VERSION 5.8 ;
BUSBITCHARS "[]" ;
DIVIDERCHAR "/" ;
UNITS
    DATABASE MICRONS 1000 ;
END UNITS

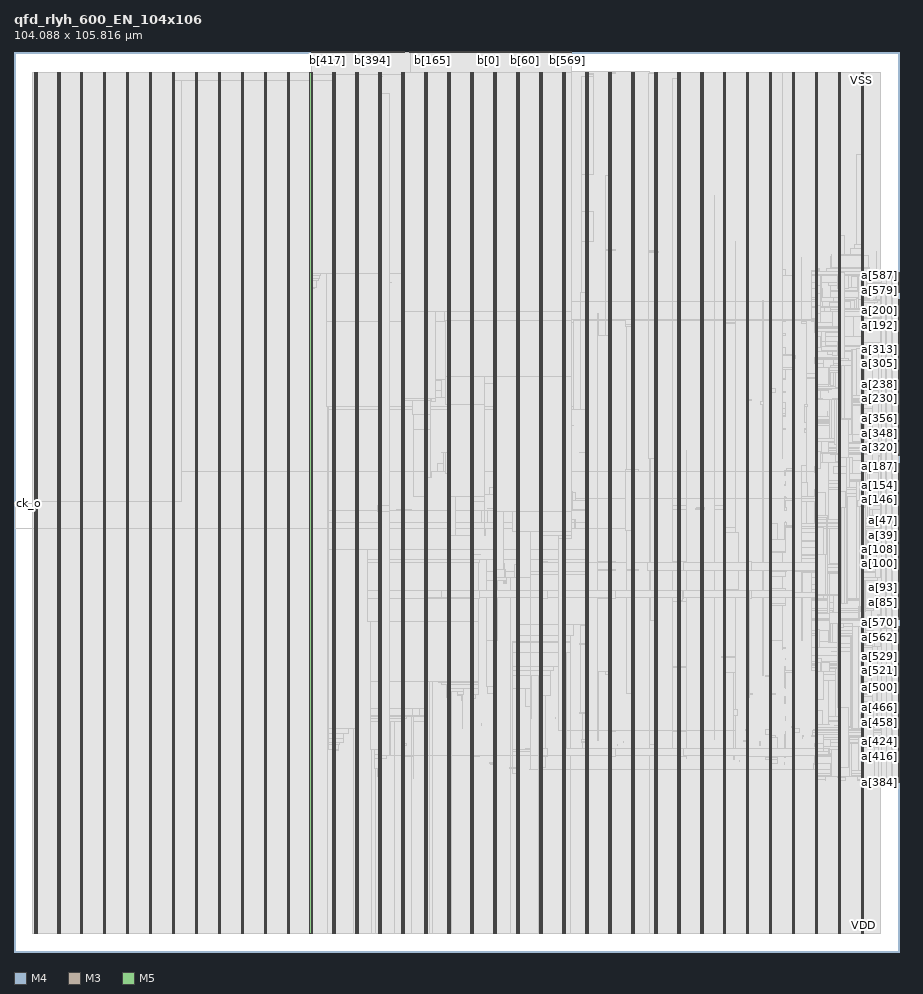
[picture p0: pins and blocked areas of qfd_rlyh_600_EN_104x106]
MACRO qfd_rlyh_600_EN_104x106
  FOREIGN qfd_rlyh_600_EN_104x106 0 0 ;
  CLASS BLOCK ;
  SIZE 104.088 BY 105.816 ;
  PIN a[0]
    DIRECTION INPUT ;
    USE SIGNAL ;
    PORT
      LAYER M4 ;
        RECT  104.004 42.192 104.088 42.216 ;
    END
  END a[0]
  PIN a[100]
    DIRECTION INPUT ;
    USE SIGNAL ;
    PORT
      LAYER M4 ;
        RECT  104.004 45.648 104.088 45.672 ;
    END
  END a[100]
  PIN a[101]
    DIRECTION INPUT ;
    USE SIGNAL ;
    PORT
      LAYER M4 ;
        RECT  104.004 45.744 104.088 45.768 ;
    END
  END a[101]
  PIN a[102]
    DIRECTION INPUT ;
    USE SIGNAL ;
    PORT
      LAYER M4 ;
        RECT  104.004 45.84 104.088 45.864 ;
    END
  END a[102]
  PIN a[103]
    DIRECTION INPUT ;
    USE SIGNAL ;
    PORT
      LAYER M4 ;
        RECT  104.004 45.936 104.088 45.96 ;
    END
  END a[103]
  PIN a[104]
    DIRECTION INPUT ;
    USE SIGNAL ;
    PORT
      LAYER M4 ;
        RECT  104.004 46.032 104.088 46.056 ;
    END
  END a[104]
  PIN a[105]
    DIRECTION INPUT ;
    USE SIGNAL ;
    PORT
      LAYER M4 ;
        RECT  104.004 46.128 104.088 46.152 ;
    END
  END a[105]
  PIN a[106]
    DIRECTION INPUT ;
    USE SIGNAL ;
    PORT
      LAYER M4 ;
        RECT  104.004 46.224 104.088 46.248 ;
    END
  END a[106]
  PIN a[107]
    DIRECTION INPUT ;
    USE SIGNAL ;
    PORT
      LAYER M4 ;
        RECT  104.004 46.32 104.088 46.344 ;
    END
  END a[107]
  PIN a[108]
    DIRECTION INPUT ;
    USE SIGNAL ;
    PORT
      LAYER M4 ;
        RECT  104.004 46.416 104.088 46.44 ;
    END
  END a[108]
  PIN a[109]
    DIRECTION INPUT ;
    USE SIGNAL ;
    PORT
      LAYER M4 ;
        RECT  104.004 46.512 104.088 46.536 ;
    END
  END a[109]
  PIN a[10]
    DIRECTION INPUT ;
    USE SIGNAL ;
    PORT
      LAYER M4 ;
        RECT  104.004 43.152 104.088 43.176 ;
    END
  END a[10]
  PIN a[110]
    DIRECTION INPUT ;
    USE SIGNAL ;
    PORT
      LAYER M4 ;
        RECT  104.004 46.608 104.088 46.632 ;
    END
  END a[110]
  PIN a[111]
    DIRECTION INPUT ;
    USE SIGNAL ;
    PORT
      LAYER M4 ;
        RECT  104.004 46.704 104.088 46.728 ;
    END
  END a[111]
  PIN a[112]
    DIRECTION INPUT ;
    USE SIGNAL ;
    PORT
      LAYER M4 ;
        RECT  104.004 46.8 104.088 46.824 ;
    END
  END a[112]
  PIN a[113]
    DIRECTION INPUT ;
    USE SIGNAL ;
    PORT
      LAYER M4 ;
        RECT  104.004 46.896 104.088 46.92 ;
    END
  END a[113]
  PIN a[114]
    DIRECTION INPUT ;
    USE SIGNAL ;
    PORT
      LAYER M4 ;
        RECT  104.004 46.992 104.088 47.016 ;
    END
  END a[114]
  PIN a[115]
    DIRECTION INPUT ;
    USE SIGNAL ;
    PORT
      LAYER M4 ;
        RECT  104.004 47.088 104.088 47.112 ;
    END
  END a[115]
  PIN a[116]
    DIRECTION INPUT ;
    USE SIGNAL ;
    PORT
      LAYER M4 ;
        RECT  104.004 47.184 104.088 47.208 ;
    END
  END a[116]
  PIN a[117]
    DIRECTION INPUT ;
    USE SIGNAL ;
    PORT
      LAYER M4 ;
        RECT  104.004 47.28 104.088 47.304 ;
    END
  END a[117]
  PIN a[118]
    DIRECTION INPUT ;
    USE SIGNAL ;
    PORT
      LAYER M4 ;
        RECT  104.004 47.376 104.088 47.4 ;
    END
  END a[118]
  PIN a[119]
    DIRECTION INPUT ;
    USE SIGNAL ;
    PORT
      LAYER M4 ;
        RECT  104.004 47.472 104.088 47.496 ;
    END
  END a[119]
  PIN a[11]
    DIRECTION INPUT ;
    USE SIGNAL ;
    PORT
      LAYER M4 ;
        RECT  104.004 43.248 104.088 43.272 ;
    END
  END a[11]
  PIN a[120]
    DIRECTION INPUT ;
    USE SIGNAL ;
    PORT
      LAYER M4 ;
        RECT  104.004 47.568 104.088 47.592 ;
    END
  END a[120]
  PIN a[121]
    DIRECTION INPUT ;
    USE SIGNAL ;
    PORT
      LAYER M4 ;
        RECT  104.004 47.664 104.088 47.688 ;
    END
  END a[121]
  PIN a[122]
    DIRECTION INPUT ;
    USE SIGNAL ;
    PORT
      LAYER M4 ;
        RECT  104.004 47.76 104.088 47.784 ;
    END
  END a[122]
  PIN a[123]
    DIRECTION INPUT ;
    USE SIGNAL ;
    PORT
      LAYER M4 ;
        RECT  104.004 47.856 104.088 47.88 ;
    END
  END a[123]
  PIN a[124]
    DIRECTION INPUT ;
    USE SIGNAL ;
    PORT
      LAYER M4 ;
        RECT  104.004 47.952 104.088 47.976 ;
    END
  END a[124]
  PIN a[125]
    DIRECTION INPUT ;
    USE SIGNAL ;
    PORT
      LAYER M4 ;
        RECT  104.004 48.048 104.088 48.072 ;
    END
  END a[125]
  PIN a[126]
    DIRECTION INPUT ;
    USE SIGNAL ;
    PORT
      LAYER M4 ;
        RECT  104.004 48.144 104.088 48.168 ;
    END
  END a[126]
  PIN a[127]
    DIRECTION INPUT ;
    USE SIGNAL ;
    PORT
      LAYER M4 ;
        RECT  104.004 48.24 104.088 48.264 ;
    END
  END a[127]
  PIN a[128]
    DIRECTION INPUT ;
    USE SIGNAL ;
    PORT
      LAYER M4 ;
        RECT  104.004 51.408 104.088 51.432 ;
    END
  END a[128]
  PIN a[129]
    DIRECTION INPUT ;
    USE SIGNAL ;
    PORT
      LAYER M4 ;
        RECT  104.004 51.504 104.088 51.528 ;
    END
  END a[129]
  PIN a[12]
    DIRECTION INPUT ;
    USE SIGNAL ;
    PORT
      LAYER M4 ;
        RECT  104.004 43.344 104.088 43.368 ;
    END
  END a[12]
  PIN a[130]
    DIRECTION INPUT ;
    USE SIGNAL ;
    PORT
      LAYER M4 ;
        RECT  104.004 51.6 104.088 51.624 ;
    END
  END a[130]
  PIN a[131]
    DIRECTION INPUT ;
    USE SIGNAL ;
    PORT
      LAYER M4 ;
        RECT  104.004 51.696 104.088 51.72 ;
    END
  END a[131]
  PIN a[132]
    DIRECTION INPUT ;
    USE SIGNAL ;
    PORT
      LAYER M4 ;
        RECT  104.004 51.792 104.088 51.816 ;
    END
  END a[132]
  PIN a[133]
    DIRECTION INPUT ;
    USE SIGNAL ;
    PORT
      LAYER M4 ;
        RECT  104.004 51.888 104.088 51.912 ;
    END
  END a[133]
  PIN a[134]
    DIRECTION INPUT ;
    USE SIGNAL ;
    PORT
      LAYER M4 ;
        RECT  104.004 51.984 104.088 52.008 ;
    END
  END a[134]
  PIN a[135]
    DIRECTION INPUT ;
    USE SIGNAL ;
    PORT
      LAYER M4 ;
        RECT  104.004 52.08 104.088 52.104 ;
    END
  END a[135]
  PIN a[136]
    DIRECTION INPUT ;
    USE SIGNAL ;
    PORT
      LAYER M4 ;
        RECT  104.004 52.176 104.088 52.2 ;
    END
  END a[136]
  PIN a[137]
    DIRECTION INPUT ;
    USE SIGNAL ;
    PORT
      LAYER M4 ;
        RECT  104.004 52.272 104.088 52.296 ;
    END
  END a[137]
  PIN a[138]
    DIRECTION INPUT ;
    USE SIGNAL ;
    PORT
      LAYER M4 ;
        RECT  104.004 52.368 104.088 52.392 ;
    END
  END a[138]
  PIN a[139]
    DIRECTION INPUT ;
    USE SIGNAL ;
    PORT
      LAYER M4 ;
        RECT  104.004 52.464 104.088 52.488 ;
    END
  END a[139]
  PIN a[13]
    DIRECTION INPUT ;
    USE SIGNAL ;
    PORT
      LAYER M4 ;
        RECT  104.004 43.44 104.088 43.464 ;
    END
  END a[13]
  PIN a[140]
    DIRECTION INPUT ;
    USE SIGNAL ;
    PORT
      LAYER M4 ;
        RECT  104.004 52.56 104.088 52.584 ;
    END
  END a[140]
  PIN a[141]
    DIRECTION INPUT ;
    USE SIGNAL ;
    PORT
      LAYER M4 ;
        RECT  104.004 52.656 104.088 52.68 ;
    END
  END a[141]
  PIN a[142]
    DIRECTION INPUT ;
    USE SIGNAL ;
    PORT
      LAYER M4 ;
        RECT  104.004 52.752 104.088 52.776 ;
    END
  END a[142]
  PIN a[143]
    DIRECTION INPUT ;
    USE SIGNAL ;
    PORT
      LAYER M4 ;
        RECT  104.004 52.848 104.088 52.872 ;
    END
  END a[143]
  PIN a[144]
    DIRECTION INPUT ;
    USE SIGNAL ;
    PORT
      LAYER M4 ;
        RECT  104.004 52.944 104.088 52.968 ;
    END
  END a[144]
  PIN a[145]
    DIRECTION INPUT ;
    USE SIGNAL ;
    PORT
      LAYER M4 ;
        RECT  104.004 53.04 104.088 53.064 ;
    END
  END a[145]
  PIN a[146]
    DIRECTION INPUT ;
    USE SIGNAL ;
    PORT
      LAYER M4 ;
        RECT  104.004 53.136 104.088 53.16 ;
    END
  END a[146]
  PIN a[147]
    DIRECTION INPUT ;
    USE SIGNAL ;
    PORT
      LAYER M4 ;
        RECT  104.004 53.232 104.088 53.256 ;
    END
  END a[147]
  PIN a[148]
    DIRECTION INPUT ;
    USE SIGNAL ;
    PORT
      LAYER M4 ;
        RECT  104.004 53.328 104.088 53.352 ;
    END
  END a[148]
  PIN a[149]
    DIRECTION INPUT ;
    USE SIGNAL ;
    PORT
      LAYER M4 ;
        RECT  104.004 53.424 104.088 53.448 ;
    END
  END a[149]
  PIN a[14]
    DIRECTION INPUT ;
    USE SIGNAL ;
    PORT
      LAYER M4 ;
        RECT  104.004 43.536 104.088 43.56 ;
    END
  END a[14]
  PIN a[150]
    DIRECTION INPUT ;
    USE SIGNAL ;
    PORT
      LAYER M4 ;
        RECT  104.004 53.52 104.088 53.544 ;
    END
  END a[150]
  PIN a[151]
    DIRECTION INPUT ;
    USE SIGNAL ;
    PORT
      LAYER M4 ;
        RECT  104.004 53.616 104.088 53.64 ;
    END
  END a[151]
  PIN a[152]
    DIRECTION INPUT ;
    USE SIGNAL ;
    PORT
      LAYER M4 ;
        RECT  104.004 53.712 104.088 53.736 ;
    END
  END a[152]
  PIN a[153]
    DIRECTION INPUT ;
    USE SIGNAL ;
    PORT
      LAYER M4 ;
        RECT  104.004 53.808 104.088 53.832 ;
    END
  END a[153]
  PIN a[154]
    DIRECTION INPUT ;
    USE SIGNAL ;
    PORT
      LAYER M4 ;
        RECT  104.004 53.904 104.088 53.928 ;
    END
  END a[154]
  PIN a[155]
    DIRECTION INPUT ;
    USE SIGNAL ;
    PORT
      LAYER M4 ;
        RECT  104.004 54 104.088 54.024 ;
    END
  END a[155]
  PIN a[156]
    DIRECTION INPUT ;
    USE SIGNAL ;
    PORT
      LAYER M4 ;
        RECT  104.004 54.096 104.088 54.12 ;
    END
  END a[156]
  PIN a[157]
    DIRECTION INPUT ;
    USE SIGNAL ;
    PORT
      LAYER M4 ;
        RECT  104.004 54.192 104.088 54.216 ;
    END
  END a[157]
  PIN a[158]
    DIRECTION INPUT ;
    USE SIGNAL ;
    PORT
      LAYER M4 ;
        RECT  104.004 54.288 104.088 54.312 ;
    END
  END a[158]
  PIN a[159]
    DIRECTION INPUT ;
    USE SIGNAL ;
    PORT
      LAYER M4 ;
        RECT  104.004 54.384 104.088 54.408 ;
    END
  END a[159]
  PIN a[15]
    DIRECTION INPUT ;
    USE SIGNAL ;
    PORT
      LAYER M4 ;
        RECT  104.004 43.632 104.088 43.656 ;
    END
  END a[15]
  PIN a[160]
    DIRECTION INPUT ;
    USE SIGNAL ;
    PORT
      LAYER M4 ;
        RECT  104.004 54.48 104.088 54.504 ;
    END
  END a[160]
  PIN a[161]
    DIRECTION INPUT ;
    USE SIGNAL ;
    PORT
      LAYER M4 ;
        RECT  104.004 54.576 104.088 54.6 ;
    END
  END a[161]
  PIN a[162]
    DIRECTION INPUT ;
    USE SIGNAL ;
    PORT
      LAYER M4 ;
        RECT  104.004 54.672 104.088 54.696 ;
    END
  END a[162]
  PIN a[163]
    DIRECTION INPUT ;
    USE SIGNAL ;
    PORT
      LAYER M4 ;
        RECT  104.004 54.768 104.088 54.792 ;
    END
  END a[163]
  PIN a[164]
    DIRECTION INPUT ;
    USE SIGNAL ;
    PORT
      LAYER M4 ;
        RECT  104.004 54.864 104.088 54.888 ;
    END
  END a[164]
  PIN a[165]
    DIRECTION INPUT ;
    USE SIGNAL ;
    PORT
      LAYER M4 ;
        RECT  104.004 54.96 104.088 54.984 ;
    END
  END a[165]
  PIN a[166]
    DIRECTION INPUT ;
    USE SIGNAL ;
    PORT
      LAYER M4 ;
        RECT  104.004 55.056 104.088 55.08 ;
    END
  END a[166]
  PIN a[167]
    DIRECTION INPUT ;
    USE SIGNAL ;
    PORT
      LAYER M4 ;
        RECT  104.004 55.152 104.088 55.176 ;
    END
  END a[167]
  PIN a[168]
    DIRECTION INPUT ;
    USE SIGNAL ;
    PORT
      LAYER M4 ;
        RECT  104.004 55.248 104.088 55.272 ;
    END
  END a[168]
  PIN a[169]
    DIRECTION INPUT ;
    USE SIGNAL ;
    PORT
      LAYER M4 ;
        RECT  104.004 55.344 104.088 55.368 ;
    END
  END a[169]
  PIN a[16]
    DIRECTION INPUT ;
    USE SIGNAL ;
    PORT
      LAYER M4 ;
        RECT  104.004 43.728 104.088 43.752 ;
    END
  END a[16]
  PIN a[170]
    DIRECTION INPUT ;
    USE SIGNAL ;
    PORT
      LAYER M4 ;
        RECT  104.004 55.44 104.088 55.464 ;
    END
  END a[170]
  PIN a[171]
    DIRECTION INPUT ;
    USE SIGNAL ;
    PORT
      LAYER M4 ;
        RECT  104.004 55.536 104.088 55.56 ;
    END
  END a[171]
  PIN a[172]
    DIRECTION INPUT ;
    USE SIGNAL ;
    PORT
      LAYER M4 ;
        RECT  104.004 55.632 104.088 55.656 ;
    END
  END a[172]
  PIN a[173]
    DIRECTION INPUT ;
    USE SIGNAL ;
    PORT
      LAYER M4 ;
        RECT  104.004 55.728 104.088 55.752 ;
    END
  END a[173]
  PIN a[174]
    DIRECTION INPUT ;
    USE SIGNAL ;
    PORT
      LAYER M4 ;
        RECT  104.004 55.824 104.088 55.848 ;
    END
  END a[174]
  PIN a[175]
    DIRECTION INPUT ;
    USE SIGNAL ;
    PORT
      LAYER M4 ;
        RECT  104.004 55.92 104.088 55.944 ;
    END
  END a[175]
  PIN a[176]
    DIRECTION INPUT ;
    USE SIGNAL ;
    PORT
      LAYER M4 ;
        RECT  104.004 56.016 104.088 56.04 ;
    END
  END a[176]
  PIN a[177]
    DIRECTION INPUT ;
    USE SIGNAL ;
    PORT
      LAYER M4 ;
        RECT  104.004 56.112 104.088 56.136 ;
    END
  END a[177]
  PIN a[178]
    DIRECTION INPUT ;
    USE SIGNAL ;
    PORT
      LAYER M4 ;
        RECT  104.004 56.208 104.088 56.232 ;
    END
  END a[178]
  PIN a[179]
    DIRECTION INPUT ;
    USE SIGNAL ;
    PORT
      LAYER M4 ;
        RECT  104.004 56.304 104.088 56.328 ;
    END
  END a[179]
  PIN a[17]
    DIRECTION INPUT ;
    USE SIGNAL ;
    PORT
      LAYER M4 ;
        RECT  104.004 43.824 104.088 43.848 ;
    END
  END a[17]
  PIN a[180]
    DIRECTION INPUT ;
    USE SIGNAL ;
    PORT
      LAYER M4 ;
        RECT  104.004 56.4 104.088 56.424 ;
    END
  END a[180]
  PIN a[181]
    DIRECTION INPUT ;
    USE SIGNAL ;
    PORT
      LAYER M4 ;
        RECT  104.004 56.496 104.088 56.52 ;
    END
  END a[181]
  PIN a[182]
    DIRECTION INPUT ;
    USE SIGNAL ;
    PORT
      LAYER M4 ;
        RECT  104.004 56.592 104.088 56.616 ;
    END
  END a[182]
  PIN a[183]
    DIRECTION INPUT ;
    USE SIGNAL ;
    PORT
      LAYER M4 ;
        RECT  104.004 56.688 104.088 56.712 ;
    END
  END a[183]
  PIN a[184]
    DIRECTION INPUT ;
    USE SIGNAL ;
    PORT
      LAYER M4 ;
        RECT  104.004 56.784 104.088 56.808 ;
    END
  END a[184]
  PIN a[185]
    DIRECTION INPUT ;
    USE SIGNAL ;
    PORT
      LAYER M4 ;
        RECT  104.004 56.88 104.088 56.904 ;
    END
  END a[185]
  PIN a[186]
    DIRECTION INPUT ;
    USE SIGNAL ;
    PORT
      LAYER M4 ;
        RECT  104.004 56.976 104.088 57 ;
    END
  END a[186]
  PIN a[187]
    DIRECTION INPUT ;
    USE SIGNAL ;
    PORT
      LAYER M4 ;
        RECT  104.004 57.072 104.088 57.096 ;
    END
  END a[187]
  PIN a[188]
    DIRECTION INPUT ;
    USE SIGNAL ;
    PORT
      LAYER M4 ;
        RECT  104.004 57.168 104.088 57.192 ;
    END
  END a[188]
  PIN a[189]
    DIRECTION INPUT ;
    USE SIGNAL ;
    PORT
      LAYER M4 ;
        RECT  104.004 57.264 104.088 57.288 ;
    END
  END a[189]
  PIN a[18]
    DIRECTION INPUT ;
    USE SIGNAL ;
    PORT
      LAYER M4 ;
        RECT  104.004 43.92 104.088 43.944 ;
    END
  END a[18]
  PIN a[190]
    DIRECTION INPUT ;
    USE SIGNAL ;
    PORT
      LAYER M4 ;
        RECT  104.004 57.36 104.088 57.384 ;
    END
  END a[190]
  PIN a[191]
    DIRECTION INPUT ;
    USE SIGNAL ;
    PORT
      LAYER M4 ;
        RECT  104.004 57.456 104.088 57.48 ;
    END
  END a[191]
  PIN a[192]
    DIRECTION INPUT ;
    USE SIGNAL ;
    PORT
      LAYER M4 ;
        RECT  104.004 73.68 104.088 73.704 ;
    END
  END a[192]
  PIN a[193]
    DIRECTION INPUT ;
    USE SIGNAL ;
    PORT
      LAYER M4 ;
        RECT  104.004 73.776 104.088 73.8 ;
    END
  END a[193]
  PIN a[194]
    DIRECTION INPUT ;
    USE SIGNAL ;
    PORT
      LAYER M4 ;
        RECT  104.004 73.872 104.088 73.896 ;
    END
  END a[194]
  PIN a[195]
    DIRECTION INPUT ;
    USE SIGNAL ;
    PORT
      LAYER M4 ;
        RECT  104.004 73.968 104.088 73.992 ;
    END
  END a[195]
  PIN a[196]
    DIRECTION INPUT ;
    USE SIGNAL ;
    PORT
      LAYER M4 ;
        RECT  104.004 74.064 104.088 74.088 ;
    END
  END a[196]
  PIN a[197]
    DIRECTION INPUT ;
    USE SIGNAL ;
    PORT
      LAYER M4 ;
        RECT  104.004 74.16 104.088 74.184 ;
    END
  END a[197]
  PIN a[198]
    DIRECTION INPUT ;
    USE SIGNAL ;
    PORT
      LAYER M4 ;
        RECT  104.004 74.256 104.088 74.28 ;
    END
  END a[198]
  PIN a[199]
    DIRECTION INPUT ;
    USE SIGNAL ;
    PORT
      LAYER M4 ;
        RECT  104.004 74.352 104.088 74.376 ;
    END
  END a[199]
  PIN a[19]
    DIRECTION INPUT ;
    USE SIGNAL ;
    PORT
      LAYER M4 ;
        RECT  104.004 44.016 104.088 44.04 ;
    END
  END a[19]
  PIN a[1]
    DIRECTION INPUT ;
    USE SIGNAL ;
    PORT
      LAYER M4 ;
        RECT  104.004 42.288 104.088 42.312 ;
    END
  END a[1]
  PIN a[200]
    DIRECTION INPUT ;
    USE SIGNAL ;
    PORT
      LAYER M4 ;
        RECT  104.004 74.448 104.088 74.472 ;
    END
  END a[200]
  PIN a[201]
    DIRECTION INPUT ;
    USE SIGNAL ;
    PORT
      LAYER M4 ;
        RECT  104.004 74.544 104.088 74.568 ;
    END
  END a[201]
  PIN a[202]
    DIRECTION INPUT ;
    USE SIGNAL ;
    PORT
      LAYER M4 ;
        RECT  104.004 74.64 104.088 74.664 ;
    END
  END a[202]
  PIN a[203]
    DIRECTION INPUT ;
    USE SIGNAL ;
    PORT
      LAYER M4 ;
        RECT  104.004 74.736 104.088 74.76 ;
    END
  END a[203]
  PIN a[204]
    DIRECTION INPUT ;
    USE SIGNAL ;
    PORT
      LAYER M4 ;
        RECT  104.004 74.832 104.088 74.856 ;
    END
  END a[204]
  PIN a[205]
    DIRECTION INPUT ;
    USE SIGNAL ;
    PORT
      LAYER M4 ;
        RECT  104.004 74.928 104.088 74.952 ;
    END
  END a[205]
  PIN a[206]
    DIRECTION INPUT ;
    USE SIGNAL ;
    PORT
      LAYER M4 ;
        RECT  104.004 75.024 104.088 75.048 ;
    END
  END a[206]
  PIN a[207]
    DIRECTION INPUT ;
    USE SIGNAL ;
    PORT
      LAYER M4 ;
        RECT  104.004 75.12 104.088 75.144 ;
    END
  END a[207]
  PIN a[208]
    DIRECTION INPUT ;
    USE SIGNAL ;
    PORT
      LAYER M4 ;
        RECT  104.004 75.216 104.088 75.24 ;
    END
  END a[208]
  PIN a[209]
    DIRECTION INPUT ;
    USE SIGNAL ;
    PORT
      LAYER M4 ;
        RECT  104.004 75.312 104.088 75.336 ;
    END
  END a[209]
  PIN a[20]
    DIRECTION INPUT ;
    USE SIGNAL ;
    PORT
      LAYER M4 ;
        RECT  104.004 44.112 104.088 44.136 ;
    END
  END a[20]
  PIN a[210]
    DIRECTION INPUT ;
    USE SIGNAL ;
    PORT
      LAYER M4 ;
        RECT  104.004 75.408 104.088 75.432 ;
    END
  END a[210]
  PIN a[211]
    DIRECTION INPUT ;
    USE SIGNAL ;
    PORT
      LAYER M4 ;
        RECT  104.004 75.504 104.088 75.528 ;
    END
  END a[211]
  PIN a[212]
    DIRECTION INPUT ;
    USE SIGNAL ;
    PORT
      LAYER M4 ;
        RECT  104.004 75.6 104.088 75.624 ;
    END
  END a[212]
  PIN a[213]
    DIRECTION INPUT ;
    USE SIGNAL ;
    PORT
      LAYER M4 ;
        RECT  104.004 75.696 104.088 75.72 ;
    END
  END a[213]
  PIN a[214]
    DIRECTION INPUT ;
    USE SIGNAL ;
    PORT
      LAYER M4 ;
        RECT  104.004 75.792 104.088 75.816 ;
    END
  END a[214]
  PIN a[215]
    DIRECTION INPUT ;
    USE SIGNAL ;
    PORT
      LAYER M4 ;
        RECT  104.004 75.888 104.088 75.912 ;
    END
  END a[215]
  PIN a[216]
    DIRECTION INPUT ;
    USE SIGNAL ;
    PORT
      LAYER M4 ;
        RECT  104.004 75.984 104.088 76.008 ;
    END
  END a[216]
  PIN a[217]
    DIRECTION INPUT ;
    USE SIGNAL ;
    PORT
      LAYER M4 ;
        RECT  104.004 76.08 104.088 76.104 ;
    END
  END a[217]
  PIN a[218]
    DIRECTION INPUT ;
    USE SIGNAL ;
    PORT
      LAYER M4 ;
        RECT  104.004 76.176 104.088 76.2 ;
    END
  END a[218]
  PIN a[219]
    DIRECTION INPUT ;
    USE SIGNAL ;
    PORT
      LAYER M4 ;
        RECT  104.004 76.272 104.088 76.296 ;
    END
  END a[219]
  PIN a[21]
    DIRECTION INPUT ;
    USE SIGNAL ;
    PORT
      LAYER M4 ;
        RECT  104.004 44.208 104.088 44.232 ;
    END
  END a[21]
  PIN a[220]
    DIRECTION INPUT ;
    USE SIGNAL ;
    PORT
      LAYER M4 ;
        RECT  104.004 76.368 104.088 76.392 ;
    END
  END a[220]
  PIN a[221]
    DIRECTION INPUT ;
    USE SIGNAL ;
    PORT
      LAYER M4 ;
        RECT  104.004 76.464 104.088 76.488 ;
    END
  END a[221]
  PIN a[222]
    DIRECTION INPUT ;
    USE SIGNAL ;
    PORT
      LAYER M4 ;
        RECT  104.004 76.56 104.088 76.584 ;
    END
  END a[222]
  PIN a[223]
    DIRECTION INPUT ;
    USE SIGNAL ;
    PORT
      LAYER M4 ;
        RECT  104.004 76.656 104.088 76.68 ;
    END
  END a[223]
  PIN a[224]
    DIRECTION INPUT ;
    USE SIGNAL ;
    PORT
      LAYER M4 ;
        RECT  104.004 64.464 104.088 64.488 ;
    END
  END a[224]
  PIN a[225]
    DIRECTION INPUT ;
    USE SIGNAL ;
    PORT
      LAYER M4 ;
        RECT  104.004 64.56 104.088 64.584 ;
    END
  END a[225]
  PIN a[226]
    DIRECTION INPUT ;
    USE SIGNAL ;
    PORT
      LAYER M4 ;
        RECT  104.004 64.656 104.088 64.68 ;
    END
  END a[226]
  PIN a[227]
    DIRECTION INPUT ;
    USE SIGNAL ;
    PORT
      LAYER M4 ;
        RECT  104.004 64.752 104.088 64.776 ;
    END
  END a[227]
  PIN a[228]
    DIRECTION INPUT ;
    USE SIGNAL ;
    PORT
      LAYER M4 ;
        RECT  104.004 64.848 104.088 64.872 ;
    END
  END a[228]
  PIN a[229]
    DIRECTION INPUT ;
    USE SIGNAL ;
    PORT
      LAYER M4 ;
        RECT  104.004 64.944 104.088 64.968 ;
    END
  END a[229]
  PIN a[22]
    DIRECTION INPUT ;
    USE SIGNAL ;
    PORT
      LAYER M4 ;
        RECT  104.004 44.304 104.088 44.328 ;
    END
  END a[22]
  PIN a[230]
    DIRECTION INPUT ;
    USE SIGNAL ;
    PORT
      LAYER M4 ;
        RECT  104.004 65.04 104.088 65.064 ;
    END
  END a[230]
  PIN a[231]
    DIRECTION INPUT ;
    USE SIGNAL ;
    PORT
      LAYER M4 ;
        RECT  104.004 65.136 104.088 65.16 ;
    END
  END a[231]
  PIN a[232]
    DIRECTION INPUT ;
    USE SIGNAL ;
    PORT
      LAYER M4 ;
        RECT  104.004 65.232 104.088 65.256 ;
    END
  END a[232]
  PIN a[233]
    DIRECTION INPUT ;
    USE SIGNAL ;
    PORT
      LAYER M4 ;
        RECT  104.004 65.328 104.088 65.352 ;
    END
  END a[233]
  PIN a[234]
    DIRECTION INPUT ;
    USE SIGNAL ;
    PORT
      LAYER M4 ;
        RECT  104.004 65.424 104.088 65.448 ;
    END
  END a[234]
  PIN a[235]
    DIRECTION INPUT ;
    USE SIGNAL ;
    PORT
      LAYER M4 ;
        RECT  104.004 65.52 104.088 65.544 ;
    END
  END a[235]
  PIN a[236]
    DIRECTION INPUT ;
    USE SIGNAL ;
    PORT
      LAYER M4 ;
        RECT  104.004 65.616 104.088 65.64 ;
    END
  END a[236]
  PIN a[237]
    DIRECTION INPUT ;
    USE SIGNAL ;
    PORT
      LAYER M4 ;
        RECT  104.004 65.712 104.088 65.736 ;
    END
  END a[237]
  PIN a[238]
    DIRECTION INPUT ;
    USE SIGNAL ;
    PORT
      LAYER M4 ;
        RECT  104.004 65.808 104.088 65.832 ;
    END
  END a[238]
  PIN a[239]
    DIRECTION INPUT ;
    USE SIGNAL ;
    PORT
      LAYER M4 ;
        RECT  104.004 65.904 104.088 65.928 ;
    END
  END a[239]
  PIN a[23]
    DIRECTION INPUT ;
    USE SIGNAL ;
    PORT
      LAYER M4 ;
        RECT  104.004 44.4 104.088 44.424 ;
    END
  END a[23]
  PIN a[240]
    DIRECTION INPUT ;
    USE SIGNAL ;
    PORT
      LAYER M4 ;
        RECT  104.004 66 104.088 66.024 ;
    END
  END a[240]
  PIN a[241]
    DIRECTION INPUT ;
    USE SIGNAL ;
    PORT
      LAYER M4 ;
        RECT  104.004 66.096 104.088 66.12 ;
    END
  END a[241]
  PIN a[242]
    DIRECTION INPUT ;
    USE SIGNAL ;
    PORT
      LAYER M4 ;
        RECT  104.004 66.192 104.088 66.216 ;
    END
  END a[242]
  PIN a[243]
    DIRECTION INPUT ;
    USE SIGNAL ;
    PORT
      LAYER M4 ;
        RECT  104.004 66.288 104.088 66.312 ;
    END
  END a[243]
  PIN a[244]
    DIRECTION INPUT ;
    USE SIGNAL ;
    PORT
      LAYER M4 ;
        RECT  104.004 66.384 104.088 66.408 ;
    END
  END a[244]
  PIN a[245]
    DIRECTION INPUT ;
    USE SIGNAL ;
    PORT
      LAYER M4 ;
        RECT  104.004 66.48 104.088 66.504 ;
    END
  END a[245]
  PIN a[246]
    DIRECTION INPUT ;
    USE SIGNAL ;
    PORT
      LAYER M4 ;
        RECT  104.004 66.576 104.088 66.6 ;
    END
  END a[246]
  PIN a[247]
    DIRECTION INPUT ;
    USE SIGNAL ;
    PORT
      LAYER M4 ;
        RECT  104.004 66.672 104.088 66.696 ;
    END
  END a[247]
  PIN a[248]
    DIRECTION INPUT ;
    USE SIGNAL ;
    PORT
      LAYER M4 ;
        RECT  104.004 66.768 104.088 66.792 ;
    END
  END a[248]
  PIN a[249]
    DIRECTION INPUT ;
    USE SIGNAL ;
    PORT
      LAYER M4 ;
        RECT  104.004 66.864 104.088 66.888 ;
    END
  END a[249]
  PIN a[24]
    DIRECTION INPUT ;
    USE SIGNAL ;
    PORT
      LAYER M4 ;
        RECT  104.004 44.496 104.088 44.52 ;
    END
  END a[24]
  PIN a[250]
    DIRECTION INPUT ;
    USE SIGNAL ;
    PORT
      LAYER M4 ;
        RECT  104.004 66.96 104.088 66.984 ;
    END
  END a[250]
  PIN a[251]
    DIRECTION INPUT ;
    USE SIGNAL ;
    PORT
      LAYER M4 ;
        RECT  104.004 67.056 104.088 67.08 ;
    END
  END a[251]
  PIN a[252]
    DIRECTION INPUT ;
    USE SIGNAL ;
    PORT
      LAYER M4 ;
        RECT  104.004 67.152 104.088 67.176 ;
    END
  END a[252]
  PIN a[253]
    DIRECTION INPUT ;
    USE SIGNAL ;
    PORT
      LAYER M4 ;
        RECT  104.004 67.248 104.088 67.272 ;
    END
  END a[253]
  PIN a[254]
    DIRECTION INPUT ;
    USE SIGNAL ;
    PORT
      LAYER M4 ;
        RECT  104.004 67.344 104.088 67.368 ;
    END
  END a[254]
  PIN a[255]
    DIRECTION INPUT ;
    USE SIGNAL ;
    PORT
      LAYER M4 ;
        RECT  104.004 67.44 104.088 67.464 ;
    END
  END a[255]
  PIN a[256]
    DIRECTION INPUT ;
    USE SIGNAL ;
    PORT
      LAYER M4 ;
        RECT  104.004 70.608 104.088 70.632 ;
    END
  END a[256]
  PIN a[257]
    DIRECTION INPUT ;
    USE SIGNAL ;
    PORT
      LAYER M4 ;
        RECT  104.004 70.704 104.088 70.728 ;
    END
  END a[257]
  PIN a[258]
    DIRECTION INPUT ;
    USE SIGNAL ;
    PORT
      LAYER M4 ;
        RECT  104.004 70.8 104.088 70.824 ;
    END
  END a[258]
  PIN a[259]
    DIRECTION INPUT ;
    USE SIGNAL ;
    PORT
      LAYER M4 ;
        RECT  104.004 70.896 104.088 70.92 ;
    END
  END a[259]
  PIN a[25]
    DIRECTION INPUT ;
    USE SIGNAL ;
    PORT
      LAYER M4 ;
        RECT  104.004 44.592 104.088 44.616 ;
    END
  END a[25]
  PIN a[260]
    DIRECTION INPUT ;
    USE SIGNAL ;
    PORT
      LAYER M4 ;
        RECT  104.004 70.992 104.088 71.016 ;
    END
  END a[260]
  PIN a[261]
    DIRECTION INPUT ;
    USE SIGNAL ;
    PORT
      LAYER M4 ;
        RECT  104.004 71.088 104.088 71.112 ;
    END
  END a[261]
  PIN a[262]
    DIRECTION INPUT ;
    USE SIGNAL ;
    PORT
      LAYER M4 ;
        RECT  104.004 71.184 104.088 71.208 ;
    END
  END a[262]
  PIN a[263]
    DIRECTION INPUT ;
    USE SIGNAL ;
    PORT
      LAYER M4 ;
        RECT  104.004 71.28 104.088 71.304 ;
    END
  END a[263]
  PIN a[264]
    DIRECTION INPUT ;
    USE SIGNAL ;
    PORT
      LAYER M4 ;
        RECT  104.004 71.376 104.088 71.4 ;
    END
  END a[264]
  PIN a[265]
    DIRECTION INPUT ;
    USE SIGNAL ;
    PORT
      LAYER M4 ;
        RECT  104.004 71.472 104.088 71.496 ;
    END
  END a[265]
  PIN a[266]
    DIRECTION INPUT ;
    USE SIGNAL ;
    PORT
      LAYER M4 ;
        RECT  104.004 71.568 104.088 71.592 ;
    END
  END a[266]
  PIN a[267]
    DIRECTION INPUT ;
    USE SIGNAL ;
    PORT
      LAYER M4 ;
        RECT  104.004 71.664 104.088 71.688 ;
    END
  END a[267]
  PIN a[268]
    DIRECTION INPUT ;
    USE SIGNAL ;
    PORT
      LAYER M4 ;
        RECT  104.004 71.76 104.088 71.784 ;
    END
  END a[268]
  PIN a[269]
    DIRECTION INPUT ;
    USE SIGNAL ;
    PORT
      LAYER M4 ;
        RECT  104.004 71.856 104.088 71.88 ;
    END
  END a[269]
  PIN a[26]
    DIRECTION INPUT ;
    USE SIGNAL ;
    PORT
      LAYER M4 ;
        RECT  104.004 44.688 104.088 44.712 ;
    END
  END a[26]
  PIN a[270]
    DIRECTION INPUT ;
    USE SIGNAL ;
    PORT
      LAYER M4 ;
        RECT  104.004 71.952 104.088 71.976 ;
    END
  END a[270]
  PIN a[271]
    DIRECTION INPUT ;
    USE SIGNAL ;
    PORT
      LAYER M4 ;
        RECT  104.004 72.048 104.088 72.072 ;
    END
  END a[271]
  PIN a[272]
    DIRECTION INPUT ;
    USE SIGNAL ;
    PORT
      LAYER M4 ;
        RECT  104.004 72.144 104.088 72.168 ;
    END
  END a[272]
  PIN a[273]
    DIRECTION INPUT ;
    USE SIGNAL ;
    PORT
      LAYER M4 ;
        RECT  104.004 72.24 104.088 72.264 ;
    END
  END a[273]
  PIN a[274]
    DIRECTION INPUT ;
    USE SIGNAL ;
    PORT
      LAYER M4 ;
        RECT  104.004 72.336 104.088 72.36 ;
    END
  END a[274]
  PIN a[275]
    DIRECTION INPUT ;
    USE SIGNAL ;
    PORT
      LAYER M4 ;
        RECT  104.004 72.432 104.088 72.456 ;
    END
  END a[275]
  PIN a[276]
    DIRECTION INPUT ;
    USE SIGNAL ;
    PORT
      LAYER M4 ;
        RECT  104.004 72.528 104.088 72.552 ;
    END
  END a[276]
  PIN a[277]
    DIRECTION INPUT ;
    USE SIGNAL ;
    PORT
      LAYER M4 ;
        RECT  104.004 72.624 104.088 72.648 ;
    END
  END a[277]
  PIN a[278]
    DIRECTION INPUT ;
    USE SIGNAL ;
    PORT
      LAYER M4 ;
        RECT  104.004 72.72 104.088 72.744 ;
    END
  END a[278]
  PIN a[279]
    DIRECTION INPUT ;
    USE SIGNAL ;
    PORT
      LAYER M4 ;
        RECT  104.004 72.816 104.088 72.84 ;
    END
  END a[279]
  PIN a[27]
    DIRECTION INPUT ;
    USE SIGNAL ;
    PORT
      LAYER M4 ;
        RECT  104.004 44.784 104.088 44.808 ;
    END
  END a[27]
  PIN a[280]
    DIRECTION INPUT ;
    USE SIGNAL ;
    PORT
      LAYER M4 ;
        RECT  104.004 72.912 104.088 72.936 ;
    END
  END a[280]
  PIN a[281]
    DIRECTION INPUT ;
    USE SIGNAL ;
    PORT
      LAYER M4 ;
        RECT  104.004 73.008 104.088 73.032 ;
    END
  END a[281]
  PIN a[282]
    DIRECTION INPUT ;
    USE SIGNAL ;
    PORT
      LAYER M4 ;
        RECT  104.004 73.104 104.088 73.128 ;
    END
  END a[282]
  PIN a[283]
    DIRECTION INPUT ;
    USE SIGNAL ;
    PORT
      LAYER M4 ;
        RECT  104.004 73.2 104.088 73.224 ;
    END
  END a[283]
  PIN a[284]
    DIRECTION INPUT ;
    USE SIGNAL ;
    PORT
      LAYER M4 ;
        RECT  104.004 73.296 104.088 73.32 ;
    END
  END a[284]
  PIN a[285]
    DIRECTION INPUT ;
    USE SIGNAL ;
    PORT
      LAYER M4 ;
        RECT  104.004 73.392 104.088 73.416 ;
    END
  END a[285]
  PIN a[286]
    DIRECTION INPUT ;
    USE SIGNAL ;
    PORT
      LAYER M4 ;
        RECT  104.004 73.488 104.088 73.512 ;
    END
  END a[286]
  PIN a[287]
    DIRECTION INPUT ;
    USE SIGNAL ;
    PORT
      LAYER M4 ;
        RECT  104.004 73.584 104.088 73.608 ;
    END
  END a[287]
  PIN a[288]
    DIRECTION INPUT ;
    USE SIGNAL ;
    PORT
      LAYER M4 ;
        RECT  104.004 67.536 104.088 67.56 ;
    END
  END a[288]
  PIN a[289]
    DIRECTION INPUT ;
    USE SIGNAL ;
    PORT
      LAYER M4 ;
        RECT  104.004 67.632 104.088 67.656 ;
    END
  END a[289]
  PIN a[28]
    DIRECTION INPUT ;
    USE SIGNAL ;
    PORT
      LAYER M4 ;
        RECT  104.004 44.88 104.088 44.904 ;
    END
  END a[28]
  PIN a[290]
    DIRECTION INPUT ;
    USE SIGNAL ;
    PORT
      LAYER M4 ;
        RECT  104.004 67.728 104.088 67.752 ;
    END
  END a[290]
  PIN a[291]
    DIRECTION INPUT ;
    USE SIGNAL ;
    PORT
      LAYER M4 ;
        RECT  104.004 67.824 104.088 67.848 ;
    END
  END a[291]
  PIN a[292]
    DIRECTION INPUT ;
    USE SIGNAL ;
    PORT
      LAYER M4 ;
        RECT  104.004 67.92 104.088 67.944 ;
    END
  END a[292]
  PIN a[293]
    DIRECTION INPUT ;
    USE SIGNAL ;
    PORT
      LAYER M4 ;
        RECT  104.004 68.016 104.088 68.04 ;
    END
  END a[293]
  PIN a[294]
    DIRECTION INPUT ;
    USE SIGNAL ;
    PORT
      LAYER M4 ;
        RECT  104.004 68.112 104.088 68.136 ;
    END
  END a[294]
  PIN a[295]
    DIRECTION INPUT ;
    USE SIGNAL ;
    PORT
      LAYER M4 ;
        RECT  104.004 68.208 104.088 68.232 ;
    END
  END a[295]
  PIN a[296]
    DIRECTION INPUT ;
    USE SIGNAL ;
    PORT
      LAYER M4 ;
        RECT  104.004 68.304 104.088 68.328 ;
    END
  END a[296]
  PIN a[297]
    DIRECTION INPUT ;
    USE SIGNAL ;
    PORT
      LAYER M4 ;
        RECT  104.004 68.4 104.088 68.424 ;
    END
  END a[297]
  PIN a[298]
    DIRECTION INPUT ;
    USE SIGNAL ;
    PORT
      LAYER M4 ;
        RECT  104.004 68.496 104.088 68.52 ;
    END
  END a[298]
  PIN a[299]
    DIRECTION INPUT ;
    USE SIGNAL ;
    PORT
      LAYER M4 ;
        RECT  104.004 68.592 104.088 68.616 ;
    END
  END a[299]
  PIN a[29]
    DIRECTION INPUT ;
    USE SIGNAL ;
    PORT
      LAYER M4 ;
        RECT  104.004 44.976 104.088 45 ;
    END
  END a[29]
  PIN a[2]
    DIRECTION INPUT ;
    USE SIGNAL ;
    PORT
      LAYER M4 ;
        RECT  104.004 42.384 104.088 42.408 ;
    END
  END a[2]
  PIN a[300]
    DIRECTION INPUT ;
    USE SIGNAL ;
    PORT
      LAYER M4 ;
        RECT  104.004 68.688 104.088 68.712 ;
    END
  END a[300]
  PIN a[301]
    DIRECTION INPUT ;
    USE SIGNAL ;
    PORT
      LAYER M4 ;
        RECT  104.004 68.784 104.088 68.808 ;
    END
  END a[301]
  PIN a[302]
    DIRECTION INPUT ;
    USE SIGNAL ;
    PORT
      LAYER M4 ;
        RECT  104.004 68.88 104.088 68.904 ;
    END
  END a[302]
  PIN a[303]
    DIRECTION INPUT ;
    USE SIGNAL ;
    PORT
      LAYER M4 ;
        RECT  104.004 68.976 104.088 69 ;
    END
  END a[303]
  PIN a[304]
    DIRECTION INPUT ;
    USE SIGNAL ;
    PORT
      LAYER M4 ;
        RECT  104.004 69.072 104.088 69.096 ;
    END
  END a[304]
  PIN a[305]
    DIRECTION INPUT ;
    USE SIGNAL ;
    PORT
      LAYER M4 ;
        RECT  104.004 69.168 104.088 69.192 ;
    END
  END a[305]
  PIN a[306]
    DIRECTION INPUT ;
    USE SIGNAL ;
    PORT
      LAYER M4 ;
        RECT  104.004 69.264 104.088 69.288 ;
    END
  END a[306]
  PIN a[307]
    DIRECTION INPUT ;
    USE SIGNAL ;
    PORT
      LAYER M4 ;
        RECT  104.004 69.36 104.088 69.384 ;
    END
  END a[307]
  PIN a[308]
    DIRECTION INPUT ;
    USE SIGNAL ;
    PORT
      LAYER M4 ;
        RECT  104.004 69.456 104.088 69.48 ;
    END
  END a[308]
  PIN a[309]
    DIRECTION INPUT ;
    USE SIGNAL ;
    PORT
      LAYER M4 ;
        RECT  104.004 69.552 104.088 69.576 ;
    END
  END a[309]
  PIN a[30]
    DIRECTION INPUT ;
    USE SIGNAL ;
    PORT
      LAYER M4 ;
        RECT  104.004 45.072 104.088 45.096 ;
    END
  END a[30]
  PIN a[310]
    DIRECTION INPUT ;
    USE SIGNAL ;
    PORT
      LAYER M4 ;
        RECT  104.004 69.648 104.088 69.672 ;
    END
  END a[310]
  PIN a[311]
    DIRECTION INPUT ;
    USE SIGNAL ;
    PORT
      LAYER M4 ;
        RECT  104.004 69.744 104.088 69.768 ;
    END
  END a[311]
  PIN a[312]
    DIRECTION INPUT ;
    USE SIGNAL ;
    PORT
      LAYER M4 ;
        RECT  104.004 69.84 104.088 69.864 ;
    END
  END a[312]
  PIN a[313]
    DIRECTION INPUT ;
    USE SIGNAL ;
    PORT
      LAYER M4 ;
        RECT  104.004 69.936 104.088 69.96 ;
    END
  END a[313]
  PIN a[314]
    DIRECTION INPUT ;
    USE SIGNAL ;
    PORT
      LAYER M4 ;
        RECT  104.004 70.032 104.088 70.056 ;
    END
  END a[314]
  PIN a[315]
    DIRECTION INPUT ;
    USE SIGNAL ;
    PORT
      LAYER M4 ;
        RECT  104.004 70.128 104.088 70.152 ;
    END
  END a[315]
  PIN a[316]
    DIRECTION INPUT ;
    USE SIGNAL ;
    PORT
      LAYER M4 ;
        RECT  104.004 70.224 104.088 70.248 ;
    END
  END a[316]
  PIN a[317]
    DIRECTION INPUT ;
    USE SIGNAL ;
    PORT
      LAYER M4 ;
        RECT  104.004 70.32 104.088 70.344 ;
    END
  END a[317]
  PIN a[318]
    DIRECTION INPUT ;
    USE SIGNAL ;
    PORT
      LAYER M4 ;
        RECT  104.004 70.416 104.088 70.44 ;
    END
  END a[318]
  PIN a[319]
    DIRECTION INPUT ;
    USE SIGNAL ;
    PORT
      LAYER M4 ;
        RECT  104.004 70.512 104.088 70.536 ;
    END
  END a[319]
  PIN a[31]
    DIRECTION INPUT ;
    USE SIGNAL ;
    PORT
      LAYER M4 ;
        RECT  104.004 45.168 104.088 45.192 ;
    END
  END a[31]
  PIN a[320]
    DIRECTION INPUT ;
    USE SIGNAL ;
    PORT
      LAYER M4 ;
        RECT  104.004 58.32 104.088 58.344 ;
    END
  END a[320]
  PIN a[321]
    DIRECTION INPUT ;
    USE SIGNAL ;
    PORT
      LAYER M4 ;
        RECT  104.004 58.416 104.088 58.44 ;
    END
  END a[321]
  PIN a[322]
    DIRECTION INPUT ;
    USE SIGNAL ;
    PORT
      LAYER M4 ;
        RECT  104.004 58.512 104.088 58.536 ;
    END
  END a[322]
  PIN a[323]
    DIRECTION INPUT ;
    USE SIGNAL ;
    PORT
      LAYER M4 ;
        RECT  104.004 58.608 104.088 58.632 ;
    END
  END a[323]
  PIN a[324]
    DIRECTION INPUT ;
    USE SIGNAL ;
    PORT
      LAYER M4 ;
        RECT  104.004 58.704 104.088 58.728 ;
    END
  END a[324]
  PIN a[325]
    DIRECTION INPUT ;
    USE SIGNAL ;
    PORT
      LAYER M4 ;
        RECT  104.004 58.8 104.088 58.824 ;
    END
  END a[325]
  PIN a[326]
    DIRECTION INPUT ;
    USE SIGNAL ;
    PORT
      LAYER M4 ;
        RECT  104.004 58.896 104.088 58.92 ;
    END
  END a[326]
  PIN a[327]
    DIRECTION INPUT ;
    USE SIGNAL ;
    PORT
      LAYER M4 ;
        RECT  104.004 58.992 104.088 59.016 ;
    END
  END a[327]
  PIN a[328]
    DIRECTION INPUT ;
    USE SIGNAL ;
    PORT
      LAYER M4 ;
        RECT  104.004 59.088 104.088 59.112 ;
    END
  END a[328]
  PIN a[329]
    DIRECTION INPUT ;
    USE SIGNAL ;
    PORT
      LAYER M4 ;
        RECT  104.004 59.184 104.088 59.208 ;
    END
  END a[329]
  PIN a[32]
    DIRECTION INPUT ;
    USE SIGNAL ;
    PORT
      LAYER M4 ;
        RECT  104.004 48.336 104.088 48.36 ;
    END
  END a[32]
  PIN a[330]
    DIRECTION INPUT ;
    USE SIGNAL ;
    PORT
      LAYER M4 ;
        RECT  104.004 59.28 104.088 59.304 ;
    END
  END a[330]
  PIN a[331]
    DIRECTION INPUT ;
    USE SIGNAL ;
    PORT
      LAYER M4 ;
        RECT  104.004 59.376 104.088 59.4 ;
    END
  END a[331]
  PIN a[332]
    DIRECTION INPUT ;
    USE SIGNAL ;
    PORT
      LAYER M4 ;
        RECT  104.004 59.472 104.088 59.496 ;
    END
  END a[332]
  PIN a[333]
    DIRECTION INPUT ;
    USE SIGNAL ;
    PORT
      LAYER M4 ;
        RECT  104.004 59.568 104.088 59.592 ;
    END
  END a[333]
  PIN a[334]
    DIRECTION INPUT ;
    USE SIGNAL ;
    PORT
      LAYER M4 ;
        RECT  104.004 59.664 104.088 59.688 ;
    END
  END a[334]
  PIN a[335]
    DIRECTION INPUT ;
    USE SIGNAL ;
    PORT
      LAYER M4 ;
        RECT  104.004 59.76 104.088 59.784 ;
    END
  END a[335]
  PIN a[336]
    DIRECTION INPUT ;
    USE SIGNAL ;
    PORT
      LAYER M4 ;
        RECT  104.004 59.856 104.088 59.88 ;
    END
  END a[336]
  PIN a[337]
    DIRECTION INPUT ;
    USE SIGNAL ;
    PORT
      LAYER M4 ;
        RECT  104.004 59.952 104.088 59.976 ;
    END
  END a[337]
  PIN a[338]
    DIRECTION INPUT ;
    USE SIGNAL ;
    PORT
      LAYER M4 ;
        RECT  104.004 60.048 104.088 60.072 ;
    END
  END a[338]
  PIN a[339]
    DIRECTION INPUT ;
    USE SIGNAL ;
    PORT
      LAYER M4 ;
        RECT  104.004 60.144 104.088 60.168 ;
    END
  END a[339]
  PIN a[33]
    DIRECTION INPUT ;
    USE SIGNAL ;
    PORT
      LAYER M4 ;
        RECT  104.004 48.432 104.088 48.456 ;
    END
  END a[33]
  PIN a[340]
    DIRECTION INPUT ;
    USE SIGNAL ;
    PORT
      LAYER M4 ;
        RECT  104.004 60.24 104.088 60.264 ;
    END
  END a[340]
  PIN a[341]
    DIRECTION INPUT ;
    USE SIGNAL ;
    PORT
      LAYER M4 ;
        RECT  104.004 60.336 104.088 60.36 ;
    END
  END a[341]
  PIN a[342]
    DIRECTION INPUT ;
    USE SIGNAL ;
    PORT
      LAYER M4 ;
        RECT  104.004 60.432 104.088 60.456 ;
    END
  END a[342]
  PIN a[343]
    DIRECTION INPUT ;
    USE SIGNAL ;
    PORT
      LAYER M4 ;
        RECT  104.004 60.528 104.088 60.552 ;
    END
  END a[343]
  PIN a[344]
    DIRECTION INPUT ;
    USE SIGNAL ;
    PORT
      LAYER M4 ;
        RECT  104.004 60.624 104.088 60.648 ;
    END
  END a[344]
  PIN a[345]
    DIRECTION INPUT ;
    USE SIGNAL ;
    PORT
      LAYER M4 ;
        RECT  104.004 60.72 104.088 60.744 ;
    END
  END a[345]
  PIN a[346]
    DIRECTION INPUT ;
    USE SIGNAL ;
    PORT
      LAYER M4 ;
        RECT  104.004 60.816 104.088 60.84 ;
    END
  END a[346]
  PIN a[347]
    DIRECTION INPUT ;
    USE SIGNAL ;
    PORT
      LAYER M4 ;
        RECT  104.004 60.912 104.088 60.936 ;
    END
  END a[347]
  PIN a[348]
    DIRECTION INPUT ;
    USE SIGNAL ;
    PORT
      LAYER M4 ;
        RECT  104.004 61.008 104.088 61.032 ;
    END
  END a[348]
  PIN a[349]
    DIRECTION INPUT ;
    USE SIGNAL ;
    PORT
      LAYER M4 ;
        RECT  104.004 61.104 104.088 61.128 ;
    END
  END a[349]
  PIN a[34]
    DIRECTION INPUT ;
    USE SIGNAL ;
    PORT
      LAYER M4 ;
        RECT  104.004 48.528 104.088 48.552 ;
    END
  END a[34]
  PIN a[350]
    DIRECTION INPUT ;
    USE SIGNAL ;
    PORT
      LAYER M4 ;
        RECT  104.004 61.2 104.088 61.224 ;
    END
  END a[350]
  PIN a[351]
    DIRECTION INPUT ;
    USE SIGNAL ;
    PORT
      LAYER M4 ;
        RECT  104.004 61.296 104.088 61.32 ;
    END
  END a[351]
  PIN a[352]
    DIRECTION INPUT ;
    USE SIGNAL ;
    PORT
      LAYER M4 ;
        RECT  104.004 61.392 104.088 61.416 ;
    END
  END a[352]
  PIN a[353]
    DIRECTION INPUT ;
    USE SIGNAL ;
    PORT
      LAYER M4 ;
        RECT  104.004 61.488 104.088 61.512 ;
    END
  END a[353]
  PIN a[354]
    DIRECTION INPUT ;
    USE SIGNAL ;
    PORT
      LAYER M4 ;
        RECT  104.004 61.584 104.088 61.608 ;
    END
  END a[354]
  PIN a[355]
    DIRECTION INPUT ;
    USE SIGNAL ;
    PORT
      LAYER M4 ;
        RECT  104.004 61.68 104.088 61.704 ;
    END
  END a[355]
  PIN a[356]
    DIRECTION INPUT ;
    USE SIGNAL ;
    PORT
      LAYER M4 ;
        RECT  104.004 61.776 104.088 61.8 ;
    END
  END a[356]
  PIN a[357]
    DIRECTION INPUT ;
    USE SIGNAL ;
    PORT
      LAYER M4 ;
        RECT  104.004 61.872 104.088 61.896 ;
    END
  END a[357]
  PIN a[358]
    DIRECTION INPUT ;
    USE SIGNAL ;
    PORT
      LAYER M4 ;
        RECT  104.004 61.968 104.088 61.992 ;
    END
  END a[358]
  PIN a[359]
    DIRECTION INPUT ;
    USE SIGNAL ;
    PORT
      LAYER M4 ;
        RECT  104.004 62.064 104.088 62.088 ;
    END
  END a[359]
  PIN a[35]
    DIRECTION INPUT ;
    USE SIGNAL ;
    PORT
      LAYER M4 ;
        RECT  104.004 48.624 104.088 48.648 ;
    END
  END a[35]
  PIN a[360]
    DIRECTION INPUT ;
    USE SIGNAL ;
    PORT
      LAYER M4 ;
        RECT  104.004 62.16 104.088 62.184 ;
    END
  END a[360]
  PIN a[361]
    DIRECTION INPUT ;
    USE SIGNAL ;
    PORT
      LAYER M4 ;
        RECT  104.004 62.256 104.088 62.28 ;
    END
  END a[361]
  PIN a[362]
    DIRECTION INPUT ;
    USE SIGNAL ;
    PORT
      LAYER M4 ;
        RECT  104.004 62.352 104.088 62.376 ;
    END
  END a[362]
  PIN a[363]
    DIRECTION INPUT ;
    USE SIGNAL ;
    PORT
      LAYER M4 ;
        RECT  104.004 62.448 104.088 62.472 ;
    END
  END a[363]
  PIN a[364]
    DIRECTION INPUT ;
    USE SIGNAL ;
    PORT
      LAYER M4 ;
        RECT  104.004 62.544 104.088 62.568 ;
    END
  END a[364]
  PIN a[365]
    DIRECTION INPUT ;
    USE SIGNAL ;
    PORT
      LAYER M4 ;
        RECT  104.004 62.64 104.088 62.664 ;
    END
  END a[365]
  PIN a[366]
    DIRECTION INPUT ;
    USE SIGNAL ;
    PORT
      LAYER M4 ;
        RECT  104.004 62.736 104.088 62.76 ;
    END
  END a[366]
  PIN a[367]
    DIRECTION INPUT ;
    USE SIGNAL ;
    PORT
      LAYER M4 ;
        RECT  104.004 62.832 104.088 62.856 ;
    END
  END a[367]
  PIN a[368]
    DIRECTION INPUT ;
    USE SIGNAL ;
    PORT
      LAYER M4 ;
        RECT  104.004 62.928 104.088 62.952 ;
    END
  END a[368]
  PIN a[369]
    DIRECTION INPUT ;
    USE SIGNAL ;
    PORT
      LAYER M4 ;
        RECT  104.004 63.024 104.088 63.048 ;
    END
  END a[369]
  PIN a[36]
    DIRECTION INPUT ;
    USE SIGNAL ;
    PORT
      LAYER M4 ;
        RECT  104.004 48.72 104.088 48.744 ;
    END
  END a[36]
  PIN a[370]
    DIRECTION INPUT ;
    USE SIGNAL ;
    PORT
      LAYER M4 ;
        RECT  104.004 63.12 104.088 63.144 ;
    END
  END a[370]
  PIN a[371]
    DIRECTION INPUT ;
    USE SIGNAL ;
    PORT
      LAYER M4 ;
        RECT  104.004 63.216 104.088 63.24 ;
    END
  END a[371]
  PIN a[372]
    DIRECTION INPUT ;
    USE SIGNAL ;
    PORT
      LAYER M4 ;
        RECT  104.004 63.312 104.088 63.336 ;
    END
  END a[372]
  PIN a[373]
    DIRECTION INPUT ;
    USE SIGNAL ;
    PORT
      LAYER M4 ;
        RECT  104.004 63.408 104.088 63.432 ;
    END
  END a[373]
  PIN a[374]
    DIRECTION INPUT ;
    USE SIGNAL ;
    PORT
      LAYER M4 ;
        RECT  104.004 63.504 104.088 63.528 ;
    END
  END a[374]
  PIN a[375]
    DIRECTION INPUT ;
    USE SIGNAL ;
    PORT
      LAYER M4 ;
        RECT  104.004 63.6 104.088 63.624 ;
    END
  END a[375]
  PIN a[376]
    DIRECTION INPUT ;
    USE SIGNAL ;
    PORT
      LAYER M4 ;
        RECT  104.004 63.696 104.088 63.72 ;
    END
  END a[376]
  PIN a[377]
    DIRECTION INPUT ;
    USE SIGNAL ;
    PORT
      LAYER M4 ;
        RECT  104.004 63.792 104.088 63.816 ;
    END
  END a[377]
  PIN a[378]
    DIRECTION INPUT ;
    USE SIGNAL ;
    PORT
      LAYER M4 ;
        RECT  104.004 63.888 104.088 63.912 ;
    END
  END a[378]
  PIN a[379]
    DIRECTION INPUT ;
    USE SIGNAL ;
    PORT
      LAYER M4 ;
        RECT  104.004 63.984 104.088 64.008 ;
    END
  END a[379]
  PIN a[37]
    DIRECTION INPUT ;
    USE SIGNAL ;
    PORT
      LAYER M4 ;
        RECT  104.004 48.816 104.088 48.84 ;
    END
  END a[37]
  PIN a[380]
    DIRECTION INPUT ;
    USE SIGNAL ;
    PORT
      LAYER M4 ;
        RECT  104.004 64.08 104.088 64.104 ;
    END
  END a[380]
  PIN a[381]
    DIRECTION INPUT ;
    USE SIGNAL ;
    PORT
      LAYER M4 ;
        RECT  104.004 64.176 104.088 64.2 ;
    END
  END a[381]
  PIN a[382]
    DIRECTION INPUT ;
    USE SIGNAL ;
    PORT
      LAYER M4 ;
        RECT  104.004 64.272 104.088 64.296 ;
    END
  END a[382]
  PIN a[383]
    DIRECTION INPUT ;
    USE SIGNAL ;
    PORT
      LAYER M4 ;
        RECT  104.004 64.368 104.088 64.392 ;
    END
  END a[383]
  PIN a[384]
    DIRECTION INPUT ;
    USE SIGNAL ;
    PORT
      LAYER M4 ;
        RECT  104.004 19.92 104.088 19.944 ;
    END
  END a[384]
  PIN a[385]
    DIRECTION INPUT ;
    USE SIGNAL ;
    PORT
      LAYER M4 ;
        RECT  104.004 20.016 104.088 20.04 ;
    END
  END a[385]
  PIN a[386]
    DIRECTION INPUT ;
    USE SIGNAL ;
    PORT
      LAYER M4 ;
        RECT  104.004 20.112 104.088 20.136 ;
    END
  END a[386]
  PIN a[387]
    DIRECTION INPUT ;
    USE SIGNAL ;
    PORT
      LAYER M4 ;
        RECT  104.004 20.208 104.088 20.232 ;
    END
  END a[387]
  PIN a[388]
    DIRECTION INPUT ;
    USE SIGNAL ;
    PORT
      LAYER M4 ;
        RECT  104.004 20.304 104.088 20.328 ;
    END
  END a[388]
  PIN a[389]
    DIRECTION INPUT ;
    USE SIGNAL ;
    PORT
      LAYER M4 ;
        RECT  104.004 20.4 104.088 20.424 ;
    END
  END a[389]
  PIN a[38]
    DIRECTION INPUT ;
    USE SIGNAL ;
    PORT
      LAYER M4 ;
        RECT  104.004 48.912 104.088 48.936 ;
    END
  END a[38]
  PIN a[390]
    DIRECTION INPUT ;
    USE SIGNAL ;
    PORT
      LAYER M4 ;
        RECT  104.004 20.496 104.088 20.52 ;
    END
  END a[390]
  PIN a[391]
    DIRECTION INPUT ;
    USE SIGNAL ;
    PORT
      LAYER M4 ;
        RECT  104.004 20.592 104.088 20.616 ;
    END
  END a[391]
  PIN a[392]
    DIRECTION INPUT ;
    USE SIGNAL ;
    PORT
      LAYER M4 ;
        RECT  104.004 20.688 104.088 20.712 ;
    END
  END a[392]
  PIN a[393]
    DIRECTION INPUT ;
    USE SIGNAL ;
    PORT
      LAYER M4 ;
        RECT  104.004 20.784 104.088 20.808 ;
    END
  END a[393]
  PIN a[394]
    DIRECTION INPUT ;
    USE SIGNAL ;
    PORT
      LAYER M4 ;
        RECT  104.004 20.88 104.088 20.904 ;
    END
  END a[394]
  PIN a[395]
    DIRECTION INPUT ;
    USE SIGNAL ;
    PORT
      LAYER M4 ;
        RECT  104.004 20.976 104.088 21 ;
    END
  END a[395]
  PIN a[396]
    DIRECTION INPUT ;
    USE SIGNAL ;
    PORT
      LAYER M4 ;
        RECT  104.004 21.072 104.088 21.096 ;
    END
  END a[396]
  PIN a[397]
    DIRECTION INPUT ;
    USE SIGNAL ;
    PORT
      LAYER M4 ;
        RECT  104.004 21.168 104.088 21.192 ;
    END
  END a[397]
  PIN a[398]
    DIRECTION INPUT ;
    USE SIGNAL ;
    PORT
      LAYER M4 ;
        RECT  104.004 21.264 104.088 21.288 ;
    END
  END a[398]
  PIN a[399]
    DIRECTION INPUT ;
    USE SIGNAL ;
    PORT
      LAYER M4 ;
        RECT  104.004 21.36 104.088 21.384 ;
    END
  END a[399]
  PIN a[39]
    DIRECTION INPUT ;
    USE SIGNAL ;
    PORT
      LAYER M4 ;
        RECT  104.004 49.008 104.088 49.032 ;
    END
  END a[39]
  PIN a[3]
    DIRECTION INPUT ;
    USE SIGNAL ;
    PORT
      LAYER M4 ;
        RECT  104.004 42.48 104.088 42.504 ;
    END
  END a[3]
  PIN a[400]
    DIRECTION INPUT ;
    USE SIGNAL ;
    PORT
      LAYER M4 ;
        RECT  104.004 21.456 104.088 21.48 ;
    END
  END a[400]
  PIN a[401]
    DIRECTION INPUT ;
    USE SIGNAL ;
    PORT
      LAYER M4 ;
        RECT  104.004 21.552 104.088 21.576 ;
    END
  END a[401]
  PIN a[402]
    DIRECTION INPUT ;
    USE SIGNAL ;
    PORT
      LAYER M4 ;
        RECT  104.004 21.648 104.088 21.672 ;
    END
  END a[402]
  PIN a[403]
    DIRECTION INPUT ;
    USE SIGNAL ;
    PORT
      LAYER M4 ;
        RECT  104.004 21.744 104.088 21.768 ;
    END
  END a[403]
  PIN a[404]
    DIRECTION INPUT ;
    USE SIGNAL ;
    PORT
      LAYER M4 ;
        RECT  104.004 21.84 104.088 21.864 ;
    END
  END a[404]
  PIN a[405]
    DIRECTION INPUT ;
    USE SIGNAL ;
    PORT
      LAYER M4 ;
        RECT  104.004 21.936 104.088 21.96 ;
    END
  END a[405]
  PIN a[406]
    DIRECTION INPUT ;
    USE SIGNAL ;
    PORT
      LAYER M4 ;
        RECT  104.004 22.032 104.088 22.056 ;
    END
  END a[406]
  PIN a[407]
    DIRECTION INPUT ;
    USE SIGNAL ;
    PORT
      LAYER M4 ;
        RECT  104.004 22.128 104.088 22.152 ;
    END
  END a[407]
  PIN a[408]
    DIRECTION INPUT ;
    USE SIGNAL ;
    PORT
      LAYER M4 ;
        RECT  104.004 22.224 104.088 22.248 ;
    END
  END a[408]
  PIN a[409]
    DIRECTION INPUT ;
    USE SIGNAL ;
    PORT
      LAYER M4 ;
        RECT  104.004 22.32 104.088 22.344 ;
    END
  END a[409]
  PIN a[40]
    DIRECTION INPUT ;
    USE SIGNAL ;
    PORT
      LAYER M4 ;
        RECT  104.004 49.104 104.088 49.128 ;
    END
  END a[40]
  PIN a[410]
    DIRECTION INPUT ;
    USE SIGNAL ;
    PORT
      LAYER M4 ;
        RECT  104.004 22.416 104.088 22.44 ;
    END
  END a[410]
  PIN a[411]
    DIRECTION INPUT ;
    USE SIGNAL ;
    PORT
      LAYER M4 ;
        RECT  104.004 22.512 104.088 22.536 ;
    END
  END a[411]
  PIN a[412]
    DIRECTION INPUT ;
    USE SIGNAL ;
    PORT
      LAYER M4 ;
        RECT  104.004 22.608 104.088 22.632 ;
    END
  END a[412]
  PIN a[413]
    DIRECTION INPUT ;
    USE SIGNAL ;
    PORT
      LAYER M4 ;
        RECT  104.004 22.704 104.088 22.728 ;
    END
  END a[413]
  PIN a[414]
    DIRECTION INPUT ;
    USE SIGNAL ;
    PORT
      LAYER M4 ;
        RECT  104.004 22.8 104.088 22.824 ;
    END
  END a[414]
  PIN a[415]
    DIRECTION INPUT ;
    USE SIGNAL ;
    PORT
      LAYER M4 ;
        RECT  104.004 22.896 104.088 22.92 ;
    END
  END a[415]
  PIN a[416]
    DIRECTION INPUT ;
    USE SIGNAL ;
    PORT
      LAYER M4 ;
        RECT  104.004 22.992 104.088 23.016 ;
    END
  END a[416]
  PIN a[417]
    DIRECTION INPUT ;
    USE SIGNAL ;
    PORT
      LAYER M4 ;
        RECT  104.004 23.088 104.088 23.112 ;
    END
  END a[417]
  PIN a[418]
    DIRECTION INPUT ;
    USE SIGNAL ;
    PORT
      LAYER M4 ;
        RECT  104.004 23.184 104.088 23.208 ;
    END
  END a[418]
  PIN a[419]
    DIRECTION INPUT ;
    USE SIGNAL ;
    PORT
      LAYER M4 ;
        RECT  104.004 23.28 104.088 23.304 ;
    END
  END a[419]
  PIN a[41]
    DIRECTION INPUT ;
    USE SIGNAL ;
    PORT
      LAYER M4 ;
        RECT  104.004 49.2 104.088 49.224 ;
    END
  END a[41]
  PIN a[420]
    DIRECTION INPUT ;
    USE SIGNAL ;
    PORT
      LAYER M4 ;
        RECT  104.004 23.376 104.088 23.4 ;
    END
  END a[420]
  PIN a[421]
    DIRECTION INPUT ;
    USE SIGNAL ;
    PORT
      LAYER M4 ;
        RECT  104.004 23.472 104.088 23.496 ;
    END
  END a[421]
  PIN a[422]
    DIRECTION INPUT ;
    USE SIGNAL ;
    PORT
      LAYER M4 ;
        RECT  104.004 23.568 104.088 23.592 ;
    END
  END a[422]
  PIN a[423]
    DIRECTION INPUT ;
    USE SIGNAL ;
    PORT
      LAYER M4 ;
        RECT  104.004 23.664 104.088 23.688 ;
    END
  END a[423]
  PIN a[424]
    DIRECTION INPUT ;
    USE SIGNAL ;
    PORT
      LAYER M4 ;
        RECT  104.004 23.76 104.088 23.784 ;
    END
  END a[424]
  PIN a[425]
    DIRECTION INPUT ;
    USE SIGNAL ;
    PORT
      LAYER M4 ;
        RECT  104.004 23.856 104.088 23.88 ;
    END
  END a[425]
  PIN a[426]
    DIRECTION INPUT ;
    USE SIGNAL ;
    PORT
      LAYER M4 ;
        RECT  104.004 23.952 104.088 23.976 ;
    END
  END a[426]
  PIN a[427]
    DIRECTION INPUT ;
    USE SIGNAL ;
    PORT
      LAYER M4 ;
        RECT  104.004 24.048 104.088 24.072 ;
    END
  END a[427]
  PIN a[428]
    DIRECTION INPUT ;
    USE SIGNAL ;
    PORT
      LAYER M4 ;
        RECT  104.004 24.144 104.088 24.168 ;
    END
  END a[428]
  PIN a[429]
    DIRECTION INPUT ;
    USE SIGNAL ;
    PORT
      LAYER M4 ;
        RECT  104.004 24.24 104.088 24.264 ;
    END
  END a[429]
  PIN a[42]
    DIRECTION INPUT ;
    USE SIGNAL ;
    PORT
      LAYER M4 ;
        RECT  104.004 49.296 104.088 49.32 ;
    END
  END a[42]
  PIN a[430]
    DIRECTION INPUT ;
    USE SIGNAL ;
    PORT
      LAYER M4 ;
        RECT  104.004 24.336 104.088 24.36 ;
    END
  END a[430]
  PIN a[431]
    DIRECTION INPUT ;
    USE SIGNAL ;
    PORT
      LAYER M4 ;
        RECT  104.004 24.432 104.088 24.456 ;
    END
  END a[431]
  PIN a[432]
    DIRECTION INPUT ;
    USE SIGNAL ;
    PORT
      LAYER M4 ;
        RECT  104.004 24.528 104.088 24.552 ;
    END
  END a[432]
  PIN a[433]
    DIRECTION INPUT ;
    USE SIGNAL ;
    PORT
      LAYER M4 ;
        RECT  104.004 24.624 104.088 24.648 ;
    END
  END a[433]
  PIN a[434]
    DIRECTION INPUT ;
    USE SIGNAL ;
    PORT
      LAYER M4 ;
        RECT  104.004 24.72 104.088 24.744 ;
    END
  END a[434]
  PIN a[435]
    DIRECTION INPUT ;
    USE SIGNAL ;
    PORT
      LAYER M4 ;
        RECT  104.004 24.816 104.088 24.84 ;
    END
  END a[435]
  PIN a[436]
    DIRECTION INPUT ;
    USE SIGNAL ;
    PORT
      LAYER M4 ;
        RECT  104.004 24.912 104.088 24.936 ;
    END
  END a[436]
  PIN a[437]
    DIRECTION INPUT ;
    USE SIGNAL ;
    PORT
      LAYER M4 ;
        RECT  104.004 25.008 104.088 25.032 ;
    END
  END a[437]
  PIN a[438]
    DIRECTION INPUT ;
    USE SIGNAL ;
    PORT
      LAYER M4 ;
        RECT  104.004 25.104 104.088 25.128 ;
    END
  END a[438]
  PIN a[439]
    DIRECTION INPUT ;
    USE SIGNAL ;
    PORT
      LAYER M4 ;
        RECT  104.004 25.2 104.088 25.224 ;
    END
  END a[439]
  PIN a[43]
    DIRECTION INPUT ;
    USE SIGNAL ;
    PORT
      LAYER M4 ;
        RECT  104.004 49.392 104.088 49.416 ;
    END
  END a[43]
  PIN a[440]
    DIRECTION INPUT ;
    USE SIGNAL ;
    PORT
      LAYER M4 ;
        RECT  104.004 25.296 104.088 25.32 ;
    END
  END a[440]
  PIN a[441]
    DIRECTION INPUT ;
    USE SIGNAL ;
    PORT
      LAYER M4 ;
        RECT  104.004 25.392 104.088 25.416 ;
    END
  END a[441]
  PIN a[442]
    DIRECTION INPUT ;
    USE SIGNAL ;
    PORT
      LAYER M4 ;
        RECT  104.004 25.488 104.088 25.512 ;
    END
  END a[442]
  PIN a[443]
    DIRECTION INPUT ;
    USE SIGNAL ;
    PORT
      LAYER M4 ;
        RECT  104.004 25.584 104.088 25.608 ;
    END
  END a[443]
  PIN a[444]
    DIRECTION INPUT ;
    USE SIGNAL ;
    PORT
      LAYER M4 ;
        RECT  104.004 25.68 104.088 25.704 ;
    END
  END a[444]
  PIN a[445]
    DIRECTION INPUT ;
    USE SIGNAL ;
    PORT
      LAYER M4 ;
        RECT  104.004 25.776 104.088 25.8 ;
    END
  END a[445]
  PIN a[446]
    DIRECTION INPUT ;
    USE SIGNAL ;
    PORT
      LAYER M4 ;
        RECT  104.004 25.872 104.088 25.896 ;
    END
  END a[446]
  PIN a[447]
    DIRECTION INPUT ;
    USE SIGNAL ;
    PORT
      LAYER M4 ;
        RECT  104.004 25.968 104.088 25.992 ;
    END
  END a[447]
  PIN a[448]
    DIRECTION INPUT ;
    USE SIGNAL ;
    PORT
      LAYER M4 ;
        RECT  104.004 26.064 104.088 26.088 ;
    END
  END a[448]
  PIN a[449]
    DIRECTION INPUT ;
    USE SIGNAL ;
    PORT
      LAYER M4 ;
        RECT  104.004 26.16 104.088 26.184 ;
    END
  END a[449]
  PIN a[44]
    DIRECTION INPUT ;
    USE SIGNAL ;
    PORT
      LAYER M4 ;
        RECT  104.004 49.488 104.088 49.512 ;
    END
  END a[44]
  PIN a[450]
    DIRECTION INPUT ;
    USE SIGNAL ;
    PORT
      LAYER M4 ;
        RECT  104.004 26.256 104.088 26.28 ;
    END
  END a[450]
  PIN a[451]
    DIRECTION INPUT ;
    USE SIGNAL ;
    PORT
      LAYER M4 ;
        RECT  104.004 26.352 104.088 26.376 ;
    END
  END a[451]
  PIN a[452]
    DIRECTION INPUT ;
    USE SIGNAL ;
    PORT
      LAYER M4 ;
        RECT  104.004 26.448 104.088 26.472 ;
    END
  END a[452]
  PIN a[453]
    DIRECTION INPUT ;
    USE SIGNAL ;
    PORT
      LAYER M4 ;
        RECT  104.004 26.544 104.088 26.568 ;
    END
  END a[453]
  PIN a[454]
    DIRECTION INPUT ;
    USE SIGNAL ;
    PORT
      LAYER M4 ;
        RECT  104.004 26.64 104.088 26.664 ;
    END
  END a[454]
  PIN a[455]
    DIRECTION INPUT ;
    USE SIGNAL ;
    PORT
      LAYER M4 ;
        RECT  104.004 26.736 104.088 26.76 ;
    END
  END a[455]
  PIN a[456]
    DIRECTION INPUT ;
    USE SIGNAL ;
    PORT
      LAYER M4 ;
        RECT  104.004 26.832 104.088 26.856 ;
    END
  END a[456]
  PIN a[457]
    DIRECTION INPUT ;
    USE SIGNAL ;
    PORT
      LAYER M4 ;
        RECT  104.004 26.928 104.088 26.952 ;
    END
  END a[457]
  PIN a[458]
    DIRECTION INPUT ;
    USE SIGNAL ;
    PORT
      LAYER M4 ;
        RECT  104.004 27.024 104.088 27.048 ;
    END
  END a[458]
  PIN a[459]
    DIRECTION INPUT ;
    USE SIGNAL ;
    PORT
      LAYER M4 ;
        RECT  104.004 27.12 104.088 27.144 ;
    END
  END a[459]
  PIN a[45]
    DIRECTION INPUT ;
    USE SIGNAL ;
    PORT
      LAYER M4 ;
        RECT  104.004 49.584 104.088 49.608 ;
    END
  END a[45]
  PIN a[460]
    DIRECTION INPUT ;
    USE SIGNAL ;
    PORT
      LAYER M4 ;
        RECT  104.004 27.216 104.088 27.24 ;
    END
  END a[460]
  PIN a[461]
    DIRECTION INPUT ;
    USE SIGNAL ;
    PORT
      LAYER M4 ;
        RECT  104.004 27.312 104.088 27.336 ;
    END
  END a[461]
  PIN a[462]
    DIRECTION INPUT ;
    USE SIGNAL ;
    PORT
      LAYER M4 ;
        RECT  104.004 27.408 104.088 27.432 ;
    END
  END a[462]
  PIN a[463]
    DIRECTION INPUT ;
    USE SIGNAL ;
    PORT
      LAYER M4 ;
        RECT  104.004 27.504 104.088 27.528 ;
    END
  END a[463]
  PIN a[464]
    DIRECTION INPUT ;
    USE SIGNAL ;
    PORT
      LAYER M4 ;
        RECT  104.004 27.6 104.088 27.624 ;
    END
  END a[464]
  PIN a[465]
    DIRECTION INPUT ;
    USE SIGNAL ;
    PORT
      LAYER M4 ;
        RECT  104.004 27.696 104.088 27.72 ;
    END
  END a[465]
  PIN a[466]
    DIRECTION INPUT ;
    USE SIGNAL ;
    PORT
      LAYER M4 ;
        RECT  104.004 27.792 104.088 27.816 ;
    END
  END a[466]
  PIN a[467]
    DIRECTION INPUT ;
    USE SIGNAL ;
    PORT
      LAYER M4 ;
        RECT  104.004 27.888 104.088 27.912 ;
    END
  END a[467]
  PIN a[468]
    DIRECTION INPUT ;
    USE SIGNAL ;
    PORT
      LAYER M4 ;
        RECT  104.004 27.984 104.088 28.008 ;
    END
  END a[468]
  PIN a[469]
    DIRECTION INPUT ;
    USE SIGNAL ;
    PORT
      LAYER M4 ;
        RECT  104.004 28.08 104.088 28.104 ;
    END
  END a[469]
  PIN a[46]
    DIRECTION INPUT ;
    USE SIGNAL ;
    PORT
      LAYER M4 ;
        RECT  104.004 49.68 104.088 49.704 ;
    END
  END a[46]
  PIN a[470]
    DIRECTION INPUT ;
    USE SIGNAL ;
    PORT
      LAYER M4 ;
        RECT  104.004 28.176 104.088 28.2 ;
    END
  END a[470]
  PIN a[471]
    DIRECTION INPUT ;
    USE SIGNAL ;
    PORT
      LAYER M4 ;
        RECT  104.004 28.272 104.088 28.296 ;
    END
  END a[471]
  PIN a[472]
    DIRECTION INPUT ;
    USE SIGNAL ;
    PORT
      LAYER M4 ;
        RECT  104.004 28.368 104.088 28.392 ;
    END
  END a[472]
  PIN a[473]
    DIRECTION INPUT ;
    USE SIGNAL ;
    PORT
      LAYER M4 ;
        RECT  104.004 28.464 104.088 28.488 ;
    END
  END a[473]
  PIN a[474]
    DIRECTION INPUT ;
    USE SIGNAL ;
    PORT
      LAYER M4 ;
        RECT  104.004 28.56 104.088 28.584 ;
    END
  END a[474]
  PIN a[475]
    DIRECTION INPUT ;
    USE SIGNAL ;
    PORT
      LAYER M4 ;
        RECT  104.004 28.656 104.088 28.68 ;
    END
  END a[475]
  PIN a[476]
    DIRECTION INPUT ;
    USE SIGNAL ;
    PORT
      LAYER M4 ;
        RECT  104.004 28.752 104.088 28.776 ;
    END
  END a[476]
  PIN a[477]
    DIRECTION INPUT ;
    USE SIGNAL ;
    PORT
      LAYER M4 ;
        RECT  104.004 28.848 104.088 28.872 ;
    END
  END a[477]
  PIN a[478]
    DIRECTION INPUT ;
    USE SIGNAL ;
    PORT
      LAYER M4 ;
        RECT  104.004 28.944 104.088 28.968 ;
    END
  END a[478]
  PIN a[479]
    DIRECTION INPUT ;
    USE SIGNAL ;
    PORT
      LAYER M4 ;
        RECT  104.004 29.04 104.088 29.064 ;
    END
  END a[479]
  PIN a[47]
    DIRECTION INPUT ;
    USE SIGNAL ;
    PORT
      LAYER M4 ;
        RECT  104.004 49.776 104.088 49.8 ;
    END
  END a[47]
  PIN a[480]
    DIRECTION INPUT ;
    USE SIGNAL ;
    PORT
      LAYER M4 ;
        RECT  104.004 29.136 104.088 29.16 ;
    END
  END a[480]
  PIN a[481]
    DIRECTION INPUT ;
    USE SIGNAL ;
    PORT
      LAYER M4 ;
        RECT  104.004 29.232 104.088 29.256 ;
    END
  END a[481]
  PIN a[482]
    DIRECTION INPUT ;
    USE SIGNAL ;
    PORT
      LAYER M4 ;
        RECT  104.004 29.328 104.088 29.352 ;
    END
  END a[482]
  PIN a[483]
    DIRECTION INPUT ;
    USE SIGNAL ;
    PORT
      LAYER M4 ;
        RECT  104.004 29.424 104.088 29.448 ;
    END
  END a[483]
  PIN a[484]
    DIRECTION INPUT ;
    USE SIGNAL ;
    PORT
      LAYER M4 ;
        RECT  104.004 29.52 104.088 29.544 ;
    END
  END a[484]
  PIN a[485]
    DIRECTION INPUT ;
    USE SIGNAL ;
    PORT
      LAYER M4 ;
        RECT  104.004 29.616 104.088 29.64 ;
    END
  END a[485]
  PIN a[486]
    DIRECTION INPUT ;
    USE SIGNAL ;
    PORT
      LAYER M4 ;
        RECT  104.004 29.712 104.088 29.736 ;
    END
  END a[486]
  PIN a[487]
    DIRECTION INPUT ;
    USE SIGNAL ;
    PORT
      LAYER M4 ;
        RECT  104.004 29.808 104.088 29.832 ;
    END
  END a[487]
  PIN a[488]
    DIRECTION INPUT ;
    USE SIGNAL ;
    PORT
      LAYER M4 ;
        RECT  104.004 29.904 104.088 29.928 ;
    END
  END a[488]
  PIN a[489]
    DIRECTION INPUT ;
    USE SIGNAL ;
    PORT
      LAYER M4 ;
        RECT  104.004 30 104.088 30.024 ;
    END
  END a[489]
  PIN a[48]
    DIRECTION INPUT ;
    USE SIGNAL ;
    PORT
      LAYER M4 ;
        RECT  104.004 49.872 104.088 49.896 ;
    END
  END a[48]
  PIN a[490]
    DIRECTION INPUT ;
    USE SIGNAL ;
    PORT
      LAYER M4 ;
        RECT  104.004 30.096 104.088 30.12 ;
    END
  END a[490]
  PIN a[491]
    DIRECTION INPUT ;
    USE SIGNAL ;
    PORT
      LAYER M4 ;
        RECT  104.004 30.192 104.088 30.216 ;
    END
  END a[491]
  PIN a[492]
    DIRECTION INPUT ;
    USE SIGNAL ;
    PORT
      LAYER M4 ;
        RECT  104.004 30.288 104.088 30.312 ;
    END
  END a[492]
  PIN a[493]
    DIRECTION INPUT ;
    USE SIGNAL ;
    PORT
      LAYER M4 ;
        RECT  104.004 30.384 104.088 30.408 ;
    END
  END a[493]
  PIN a[494]
    DIRECTION INPUT ;
    USE SIGNAL ;
    PORT
      LAYER M4 ;
        RECT  104.004 30.48 104.088 30.504 ;
    END
  END a[494]
  PIN a[495]
    DIRECTION INPUT ;
    USE SIGNAL ;
    PORT
      LAYER M4 ;
        RECT  104.004 30.576 104.088 30.6 ;
    END
  END a[495]
  PIN a[496]
    DIRECTION INPUT ;
    USE SIGNAL ;
    PORT
      LAYER M4 ;
        RECT  104.004 30.672 104.088 30.696 ;
    END
  END a[496]
  PIN a[497]
    DIRECTION INPUT ;
    USE SIGNAL ;
    PORT
      LAYER M4 ;
        RECT  104.004 30.768 104.088 30.792 ;
    END
  END a[497]
  PIN a[498]
    DIRECTION INPUT ;
    USE SIGNAL ;
    PORT
      LAYER M4 ;
        RECT  104.004 30.864 104.088 30.888 ;
    END
  END a[498]
  PIN a[499]
    DIRECTION INPUT ;
    USE SIGNAL ;
    PORT
      LAYER M4 ;
        RECT  104.004 30.96 104.088 30.984 ;
    END
  END a[499]
  PIN a[49]
    DIRECTION INPUT ;
    USE SIGNAL ;
    PORT
      LAYER M4 ;
        RECT  104.004 49.968 104.088 49.992 ;
    END
  END a[49]
  PIN a[4]
    DIRECTION INPUT ;
    USE SIGNAL ;
    PORT
      LAYER M4 ;
        RECT  104.004 42.576 104.088 42.6 ;
    END
  END a[4]
  PIN a[500]
    DIRECTION INPUT ;
    USE SIGNAL ;
    PORT
      LAYER M4 ;
        RECT  104.004 31.056 104.088 31.08 ;
    END
  END a[500]
  PIN a[501]
    DIRECTION INPUT ;
    USE SIGNAL ;
    PORT
      LAYER M4 ;
        RECT  104.004 31.152 104.088 31.176 ;
    END
  END a[501]
  PIN a[502]
    DIRECTION INPUT ;
    USE SIGNAL ;
    PORT
      LAYER M4 ;
        RECT  104.004 31.248 104.088 31.272 ;
    END
  END a[502]
  PIN a[503]
    DIRECTION INPUT ;
    USE SIGNAL ;
    PORT
      LAYER M4 ;
        RECT  104.004 31.344 104.088 31.368 ;
    END
  END a[503]
  PIN a[504]
    DIRECTION INPUT ;
    USE SIGNAL ;
    PORT
      LAYER M4 ;
        RECT  104.004 31.44 104.088 31.464 ;
    END
  END a[504]
  PIN a[505]
    DIRECTION INPUT ;
    USE SIGNAL ;
    PORT
      LAYER M4 ;
        RECT  104.004 31.536 104.088 31.56 ;
    END
  END a[505]
  PIN a[506]
    DIRECTION INPUT ;
    USE SIGNAL ;
    PORT
      LAYER M4 ;
        RECT  104.004 31.632 104.088 31.656 ;
    END
  END a[506]
  PIN a[507]
    DIRECTION INPUT ;
    USE SIGNAL ;
    PORT
      LAYER M4 ;
        RECT  104.004 31.728 104.088 31.752 ;
    END
  END a[507]
  PIN a[508]
    DIRECTION INPUT ;
    USE SIGNAL ;
    PORT
      LAYER M4 ;
        RECT  104.004 31.824 104.088 31.848 ;
    END
  END a[508]
  PIN a[509]
    DIRECTION INPUT ;
    USE SIGNAL ;
    PORT
      LAYER M4 ;
        RECT  104.004 31.92 104.088 31.944 ;
    END
  END a[509]
  PIN a[50]
    DIRECTION INPUT ;
    USE SIGNAL ;
    PORT
      LAYER M4 ;
        RECT  104.004 50.064 104.088 50.088 ;
    END
  END a[50]
  PIN a[510]
    DIRECTION INPUT ;
    USE SIGNAL ;
    PORT
      LAYER M4 ;
        RECT  104.004 32.016 104.088 32.04 ;
    END
  END a[510]
  PIN a[511]
    DIRECTION INPUT ;
    USE SIGNAL ;
    PORT
      LAYER M4 ;
        RECT  104.004 32.112 104.088 32.136 ;
    END
  END a[511]
  PIN a[512]
    DIRECTION INPUT ;
    USE SIGNAL ;
    PORT
      LAYER M4 ;
        RECT  104.004 32.208 104.088 32.232 ;
    END
  END a[512]
  PIN a[513]
    DIRECTION INPUT ;
    USE SIGNAL ;
    PORT
      LAYER M4 ;
        RECT  104.004 32.304 104.088 32.328 ;
    END
  END a[513]
  PIN a[514]
    DIRECTION INPUT ;
    USE SIGNAL ;
    PORT
      LAYER M4 ;
        RECT  104.004 32.4 104.088 32.424 ;
    END
  END a[514]
  PIN a[515]
    DIRECTION INPUT ;
    USE SIGNAL ;
    PORT
      LAYER M4 ;
        RECT  104.004 32.496 104.088 32.52 ;
    END
  END a[515]
  PIN a[516]
    DIRECTION INPUT ;
    USE SIGNAL ;
    PORT
      LAYER M4 ;
        RECT  104.004 32.592 104.088 32.616 ;
    END
  END a[516]
  PIN a[517]
    DIRECTION INPUT ;
    USE SIGNAL ;
    PORT
      LAYER M4 ;
        RECT  104.004 32.688 104.088 32.712 ;
    END
  END a[517]
  PIN a[518]
    DIRECTION INPUT ;
    USE SIGNAL ;
    PORT
      LAYER M4 ;
        RECT  104.004 32.784 104.088 32.808 ;
    END
  END a[518]
  PIN a[519]
    DIRECTION INPUT ;
    USE SIGNAL ;
    PORT
      LAYER M4 ;
        RECT  104.004 32.88 104.088 32.904 ;
    END
  END a[519]
  PIN a[51]
    DIRECTION INPUT ;
    USE SIGNAL ;
    PORT
      LAYER M4 ;
        RECT  104.004 50.16 104.088 50.184 ;
    END
  END a[51]
  PIN a[520]
    DIRECTION INPUT ;
    USE SIGNAL ;
    PORT
      LAYER M4 ;
        RECT  104.004 32.976 104.088 33 ;
    END
  END a[520]
  PIN a[521]
    DIRECTION INPUT ;
    USE SIGNAL ;
    PORT
      LAYER M4 ;
        RECT  104.004 33.072 104.088 33.096 ;
    END
  END a[521]
  PIN a[522]
    DIRECTION INPUT ;
    USE SIGNAL ;
    PORT
      LAYER M4 ;
        RECT  104.004 33.168 104.088 33.192 ;
    END
  END a[522]
  PIN a[523]
    DIRECTION INPUT ;
    USE SIGNAL ;
    PORT
      LAYER M4 ;
        RECT  104.004 33.264 104.088 33.288 ;
    END
  END a[523]
  PIN a[524]
    DIRECTION INPUT ;
    USE SIGNAL ;
    PORT
      LAYER M4 ;
        RECT  104.004 33.36 104.088 33.384 ;
    END
  END a[524]
  PIN a[525]
    DIRECTION INPUT ;
    USE SIGNAL ;
    PORT
      LAYER M4 ;
        RECT  104.004 33.456 104.088 33.48 ;
    END
  END a[525]
  PIN a[526]
    DIRECTION INPUT ;
    USE SIGNAL ;
    PORT
      LAYER M4 ;
        RECT  104.004 33.552 104.088 33.576 ;
    END
  END a[526]
  PIN a[527]
    DIRECTION INPUT ;
    USE SIGNAL ;
    PORT
      LAYER M4 ;
        RECT  104.004 33.648 104.088 33.672 ;
    END
  END a[527]
  PIN a[528]
    DIRECTION INPUT ;
    USE SIGNAL ;
    PORT
      LAYER M4 ;
        RECT  104.004 33.744 104.088 33.768 ;
    END
  END a[528]
  PIN a[529]
    DIRECTION INPUT ;
    USE SIGNAL ;
    PORT
      LAYER M4 ;
        RECT  104.004 33.84 104.088 33.864 ;
    END
  END a[529]
  PIN a[52]
    DIRECTION INPUT ;
    USE SIGNAL ;
    PORT
      LAYER M4 ;
        RECT  104.004 50.256 104.088 50.28 ;
    END
  END a[52]
  PIN a[530]
    DIRECTION INPUT ;
    USE SIGNAL ;
    PORT
      LAYER M4 ;
        RECT  104.004 33.936 104.088 33.96 ;
    END
  END a[530]
  PIN a[531]
    DIRECTION INPUT ;
    USE SIGNAL ;
    PORT
      LAYER M4 ;
        RECT  104.004 34.032 104.088 34.056 ;
    END
  END a[531]
  PIN a[532]
    DIRECTION INPUT ;
    USE SIGNAL ;
    PORT
      LAYER M4 ;
        RECT  104.004 34.128 104.088 34.152 ;
    END
  END a[532]
  PIN a[533]
    DIRECTION INPUT ;
    USE SIGNAL ;
    PORT
      LAYER M4 ;
        RECT  104.004 34.224 104.088 34.248 ;
    END
  END a[533]
  PIN a[534]
    DIRECTION INPUT ;
    USE SIGNAL ;
    PORT
      LAYER M4 ;
        RECT  104.004 34.32 104.088 34.344 ;
    END
  END a[534]
  PIN a[535]
    DIRECTION INPUT ;
    USE SIGNAL ;
    PORT
      LAYER M4 ;
        RECT  104.004 34.416 104.088 34.44 ;
    END
  END a[535]
  PIN a[536]
    DIRECTION INPUT ;
    USE SIGNAL ;
    PORT
      LAYER M4 ;
        RECT  104.004 34.512 104.088 34.536 ;
    END
  END a[536]
  PIN a[537]
    DIRECTION INPUT ;
    USE SIGNAL ;
    PORT
      LAYER M4 ;
        RECT  104.004 34.608 104.088 34.632 ;
    END
  END a[537]
  PIN a[538]
    DIRECTION INPUT ;
    USE SIGNAL ;
    PORT
      LAYER M4 ;
        RECT  104.004 34.704 104.088 34.728 ;
    END
  END a[538]
  PIN a[539]
    DIRECTION INPUT ;
    USE SIGNAL ;
    PORT
      LAYER M4 ;
        RECT  104.004 34.8 104.088 34.824 ;
    END
  END a[539]
  PIN a[53]
    DIRECTION INPUT ;
    USE SIGNAL ;
    PORT
      LAYER M4 ;
        RECT  104.004 50.352 104.088 50.376 ;
    END
  END a[53]
  PIN a[540]
    DIRECTION INPUT ;
    USE SIGNAL ;
    PORT
      LAYER M4 ;
        RECT  104.004 34.896 104.088 34.92 ;
    END
  END a[540]
  PIN a[541]
    DIRECTION INPUT ;
    USE SIGNAL ;
    PORT
      LAYER M4 ;
        RECT  104.004 34.992 104.088 35.016 ;
    END
  END a[541]
  PIN a[542]
    DIRECTION INPUT ;
    USE SIGNAL ;
    PORT
      LAYER M4 ;
        RECT  104.004 35.088 104.088 35.112 ;
    END
  END a[542]
  PIN a[543]
    DIRECTION INPUT ;
    USE SIGNAL ;
    PORT
      LAYER M4 ;
        RECT  104.004 35.184 104.088 35.208 ;
    END
  END a[543]
  PIN a[544]
    DIRECTION INPUT ;
    USE SIGNAL ;
    PORT
      LAYER M4 ;
        RECT  104.004 35.28 104.088 35.304 ;
    END
  END a[544]
  PIN a[545]
    DIRECTION INPUT ;
    USE SIGNAL ;
    PORT
      LAYER M4 ;
        RECT  104.004 35.376 104.088 35.4 ;
    END
  END a[545]
  PIN a[546]
    DIRECTION INPUT ;
    USE SIGNAL ;
    PORT
      LAYER M4 ;
        RECT  104.004 35.472 104.088 35.496 ;
    END
  END a[546]
  PIN a[547]
    DIRECTION INPUT ;
    USE SIGNAL ;
    PORT
      LAYER M4 ;
        RECT  104.004 35.568 104.088 35.592 ;
    END
  END a[547]
  PIN a[548]
    DIRECTION INPUT ;
    USE SIGNAL ;
    PORT
      LAYER M4 ;
        RECT  104.004 35.664 104.088 35.688 ;
    END
  END a[548]
  PIN a[549]
    DIRECTION INPUT ;
    USE SIGNAL ;
    PORT
      LAYER M4 ;
        RECT  104.004 35.76 104.088 35.784 ;
    END
  END a[549]
  PIN a[54]
    DIRECTION INPUT ;
    USE SIGNAL ;
    PORT
      LAYER M4 ;
        RECT  104.004 50.448 104.088 50.472 ;
    END
  END a[54]
  PIN a[550]
    DIRECTION INPUT ;
    USE SIGNAL ;
    PORT
      LAYER M4 ;
        RECT  104.004 35.856 104.088 35.88 ;
    END
  END a[550]
  PIN a[551]
    DIRECTION INPUT ;
    USE SIGNAL ;
    PORT
      LAYER M4 ;
        RECT  104.004 35.952 104.088 35.976 ;
    END
  END a[551]
  PIN a[552]
    DIRECTION INPUT ;
    USE SIGNAL ;
    PORT
      LAYER M4 ;
        RECT  104.004 36.048 104.088 36.072 ;
    END
  END a[552]
  PIN a[553]
    DIRECTION INPUT ;
    USE SIGNAL ;
    PORT
      LAYER M4 ;
        RECT  104.004 36.144 104.088 36.168 ;
    END
  END a[553]
  PIN a[554]
    DIRECTION INPUT ;
    USE SIGNAL ;
    PORT
      LAYER M4 ;
        RECT  104.004 36.24 104.088 36.264 ;
    END
  END a[554]
  PIN a[555]
    DIRECTION INPUT ;
    USE SIGNAL ;
    PORT
      LAYER M4 ;
        RECT  104.004 36.336 104.088 36.36 ;
    END
  END a[555]
  PIN a[556]
    DIRECTION INPUT ;
    USE SIGNAL ;
    PORT
      LAYER M4 ;
        RECT  104.004 36.432 104.088 36.456 ;
    END
  END a[556]
  PIN a[557]
    DIRECTION INPUT ;
    USE SIGNAL ;
    PORT
      LAYER M4 ;
        RECT  104.004 36.528 104.088 36.552 ;
    END
  END a[557]
  PIN a[558]
    DIRECTION INPUT ;
    USE SIGNAL ;
    PORT
      LAYER M4 ;
        RECT  104.004 36.624 104.088 36.648 ;
    END
  END a[558]
  PIN a[559]
    DIRECTION INPUT ;
    USE SIGNAL ;
    PORT
      LAYER M4 ;
        RECT  104.004 36.72 104.088 36.744 ;
    END
  END a[559]
  PIN a[55]
    DIRECTION INPUT ;
    USE SIGNAL ;
    PORT
      LAYER M4 ;
        RECT  104.004 50.544 104.088 50.568 ;
    END
  END a[55]
  PIN a[560]
    DIRECTION INPUT ;
    USE SIGNAL ;
    PORT
      LAYER M4 ;
        RECT  104.004 36.816 104.088 36.84 ;
    END
  END a[560]
  PIN a[561]
    DIRECTION INPUT ;
    USE SIGNAL ;
    PORT
      LAYER M4 ;
        RECT  104.004 36.912 104.088 36.936 ;
    END
  END a[561]
  PIN a[562]
    DIRECTION INPUT ;
    USE SIGNAL ;
    PORT
      LAYER M4 ;
        RECT  104.004 37.008 104.088 37.032 ;
    END
  END a[562]
  PIN a[563]
    DIRECTION INPUT ;
    USE SIGNAL ;
    PORT
      LAYER M4 ;
        RECT  104.004 37.104 104.088 37.128 ;
    END
  END a[563]
  PIN a[564]
    DIRECTION INPUT ;
    USE SIGNAL ;
    PORT
      LAYER M4 ;
        RECT  104.004 37.2 104.088 37.224 ;
    END
  END a[564]
  PIN a[565]
    DIRECTION INPUT ;
    USE SIGNAL ;
    PORT
      LAYER M4 ;
        RECT  104.004 37.296 104.088 37.32 ;
    END
  END a[565]
  PIN a[566]
    DIRECTION INPUT ;
    USE SIGNAL ;
    PORT
      LAYER M4 ;
        RECT  104.004 37.392 104.088 37.416 ;
    END
  END a[566]
  PIN a[567]
    DIRECTION INPUT ;
    USE SIGNAL ;
    PORT
      LAYER M4 ;
        RECT  104.004 37.488 104.088 37.512 ;
    END
  END a[567]
  PIN a[568]
    DIRECTION INPUT ;
    USE SIGNAL ;
    PORT
      LAYER M4 ;
        RECT  104.004 37.584 104.088 37.608 ;
    END
  END a[568]
  PIN a[569]
    DIRECTION INPUT ;
    USE SIGNAL ;
    PORT
      LAYER M4 ;
        RECT  104.004 37.68 104.088 37.704 ;
    END
  END a[569]
  PIN a[56]
    DIRECTION INPUT ;
    USE SIGNAL ;
    PORT
      LAYER M4 ;
        RECT  104.004 50.64 104.088 50.664 ;
    END
  END a[56]
  PIN a[570]
    DIRECTION INPUT ;
    USE SIGNAL ;
    PORT
      LAYER M4 ;
        RECT  104.004 37.776 104.088 37.8 ;
    END
  END a[570]
  PIN a[571]
    DIRECTION INPUT ;
    USE SIGNAL ;
    PORT
      LAYER M4 ;
        RECT  104.004 37.872 104.088 37.896 ;
    END
  END a[571]
  PIN a[572]
    DIRECTION INPUT ;
    USE SIGNAL ;
    PORT
      LAYER M4 ;
        RECT  104.004 37.968 104.088 37.992 ;
    END
  END a[572]
  PIN a[573]
    DIRECTION INPUT ;
    USE SIGNAL ;
    PORT
      LAYER M4 ;
        RECT  104.004 38.064 104.088 38.088 ;
    END
  END a[573]
  PIN a[574]
    DIRECTION INPUT ;
    USE SIGNAL ;
    PORT
      LAYER M4 ;
        RECT  104.004 38.16 104.088 38.184 ;
    END
  END a[574]
  PIN a[575]
    DIRECTION INPUT ;
    USE SIGNAL ;
    PORT
      LAYER M4 ;
        RECT  104.004 38.256 104.088 38.28 ;
    END
  END a[575]
  PIN a[576]
    DIRECTION INPUT ;
    USE SIGNAL ;
    PORT
      LAYER M4 ;
        RECT  104.004 77.52 104.088 77.544 ;
    END
  END a[576]
  PIN a[577]
    DIRECTION INPUT ;
    USE SIGNAL ;
    PORT
      LAYER M4 ;
        RECT  104.004 77.616 104.088 77.64 ;
    END
  END a[577]
  PIN a[578]
    DIRECTION INPUT ;
    USE SIGNAL ;
    PORT
      LAYER M4 ;
        RECT  104.004 77.712 104.088 77.736 ;
    END
  END a[578]
  PIN a[579]
    DIRECTION INPUT ;
    USE SIGNAL ;
    PORT
      LAYER M4 ;
        RECT  104.004 77.808 104.088 77.832 ;
    END
  END a[579]
  PIN a[57]
    DIRECTION INPUT ;
    USE SIGNAL ;
    PORT
      LAYER M4 ;
        RECT  104.004 50.736 104.088 50.76 ;
    END
  END a[57]
  PIN a[580]
    DIRECTION INPUT ;
    USE SIGNAL ;
    PORT
      LAYER M4 ;
        RECT  104.004 77.904 104.088 77.928 ;
    END
  END a[580]
  PIN a[581]
    DIRECTION INPUT ;
    USE SIGNAL ;
    PORT
      LAYER M4 ;
        RECT  104.004 78 104.088 78.024 ;
    END
  END a[581]
  PIN a[582]
    DIRECTION INPUT ;
    USE SIGNAL ;
    PORT
      LAYER M4 ;
        RECT  104.004 78.096 104.088 78.12 ;
    END
  END a[582]
  PIN a[583]
    DIRECTION INPUT ;
    USE SIGNAL ;
    PORT
      LAYER M4 ;
        RECT  104.004 78.192 104.088 78.216 ;
    END
  END a[583]
  PIN a[584]
    DIRECTION INPUT ;
    USE SIGNAL ;
    PORT
      LAYER M4 ;
        RECT  104.004 78.288 104.088 78.312 ;
    END
  END a[584]
  PIN a[585]
    DIRECTION INPUT ;
    USE SIGNAL ;
    PORT
      LAYER M4 ;
        RECT  104.004 78.384 104.088 78.408 ;
    END
  END a[585]
  PIN a[586]
    DIRECTION INPUT ;
    USE SIGNAL ;
    PORT
      LAYER M4 ;
        RECT  104.004 78.48 104.088 78.504 ;
    END
  END a[586]
  PIN a[587]
    DIRECTION INPUT ;
    USE SIGNAL ;
    PORT
      LAYER M4 ;
        RECT  104.004 78.576 104.088 78.6 ;
    END
  END a[587]
  PIN a[588]
    DIRECTION INPUT ;
    USE SIGNAL ;
    PORT
      LAYER M4 ;
        RECT  104.004 78.672 104.088 78.696 ;
    END
  END a[588]
  PIN a[589]
    DIRECTION INPUT ;
    USE SIGNAL ;
    PORT
      LAYER M4 ;
        RECT  104.004 78.768 104.088 78.792 ;
    END
  END a[589]
  PIN a[58]
    DIRECTION INPUT ;
    USE SIGNAL ;
    PORT
      LAYER M4 ;
        RECT  104.004 50.832 104.088 50.856 ;
    END
  END a[58]
  PIN a[590]
    DIRECTION INPUT ;
    USE SIGNAL ;
    PORT
      LAYER M4 ;
        RECT  104.004 78.864 104.088 78.888 ;
    END
  END a[590]
  PIN a[591]
    DIRECTION INPUT ;
    USE SIGNAL ;
    PORT
      LAYER M4 ;
        RECT  104.004 78.96 104.088 78.984 ;
    END
  END a[591]
  PIN a[592]
    DIRECTION INPUT ;
    USE SIGNAL ;
    PORT
      LAYER M4 ;
        RECT  104.004 79.056 104.088 79.08 ;
    END
  END a[592]
  PIN a[593]
    DIRECTION INPUT ;
    USE SIGNAL ;
    PORT
      LAYER M4 ;
        RECT  104.004 79.152 104.088 79.176 ;
    END
  END a[593]
  PIN a[594]
    DIRECTION INPUT ;
    USE SIGNAL ;
    PORT
      LAYER M4 ;
        RECT  104.004 79.248 104.088 79.272 ;
    END
  END a[594]
  PIN a[595]
    DIRECTION INPUT ;
    USE SIGNAL ;
    PORT
      LAYER M4 ;
        RECT  104.004 79.344 104.088 79.368 ;
    END
  END a[595]
  PIN a[596]
    DIRECTION INPUT ;
    USE SIGNAL ;
    PORT
      LAYER M4 ;
        RECT  104.004 79.44 104.088 79.464 ;
    END
  END a[596]
  PIN a[597]
    DIRECTION INPUT ;
    USE SIGNAL ;
    PORT
      LAYER M4 ;
        RECT  104.004 79.536 104.088 79.56 ;
    END
  END a[597]
  PIN a[598]
    DIRECTION INPUT ;
    USE SIGNAL ;
    PORT
      LAYER M4 ;
        RECT  104.004 79.632 104.088 79.656 ;
    END
  END a[598]
  PIN a[599]
    DIRECTION INPUT ;
    USE SIGNAL ;
    PORT
      LAYER M4 ;
        RECT  104.004 79.728 104.088 79.752 ;
    END
  END a[599]
  PIN a[59]
    DIRECTION INPUT ;
    USE SIGNAL ;
    PORT
      LAYER M4 ;
        RECT  104.004 50.928 104.088 50.952 ;
    END
  END a[59]
  PIN a[5]
    DIRECTION INPUT ;
    USE SIGNAL ;
    PORT
      LAYER M4 ;
        RECT  104.004 42.672 104.088 42.696 ;
    END
  END a[5]
  PIN a[60]
    DIRECTION INPUT ;
    USE SIGNAL ;
    PORT
      LAYER M4 ;
        RECT  104.004 51.024 104.088 51.048 ;
    END
  END a[60]
  PIN a[61]
    DIRECTION INPUT ;
    USE SIGNAL ;
    PORT
      LAYER M4 ;
        RECT  104.004 51.12 104.088 51.144 ;
    END
  END a[61]
  PIN a[62]
    DIRECTION INPUT ;
    USE SIGNAL ;
    PORT
      LAYER M4 ;
        RECT  104.004 51.216 104.088 51.24 ;
    END
  END a[62]
  PIN a[63]
    DIRECTION INPUT ;
    USE SIGNAL ;
    PORT
      LAYER M4 ;
        RECT  104.004 51.312 104.088 51.336 ;
    END
  END a[63]
  PIN a[64]
    DIRECTION INPUT ;
    USE SIGNAL ;
    PORT
      LAYER M4 ;
        RECT  104.004 39.12 104.088 39.144 ;
    END
  END a[64]
  PIN a[65]
    DIRECTION INPUT ;
    USE SIGNAL ;
    PORT
      LAYER M4 ;
        RECT  104.004 39.216 104.088 39.24 ;
    END
  END a[65]
  PIN a[66]
    DIRECTION INPUT ;
    USE SIGNAL ;
    PORT
      LAYER M4 ;
        RECT  104.004 39.312 104.088 39.336 ;
    END
  END a[66]
  PIN a[67]
    DIRECTION INPUT ;
    USE SIGNAL ;
    PORT
      LAYER M4 ;
        RECT  104.004 39.408 104.088 39.432 ;
    END
  END a[67]
  PIN a[68]
    DIRECTION INPUT ;
    USE SIGNAL ;
    PORT
      LAYER M4 ;
        RECT  104.004 39.504 104.088 39.528 ;
    END
  END a[68]
  PIN a[69]
    DIRECTION INPUT ;
    USE SIGNAL ;
    PORT
      LAYER M4 ;
        RECT  104.004 39.6 104.088 39.624 ;
    END
  END a[69]
  PIN a[6]
    DIRECTION INPUT ;
    USE SIGNAL ;
    PORT
      LAYER M4 ;
        RECT  104.004 42.768 104.088 42.792 ;
    END
  END a[6]
  PIN a[70]
    DIRECTION INPUT ;
    USE SIGNAL ;
    PORT
      LAYER M4 ;
        RECT  104.004 39.696 104.088 39.72 ;
    END
  END a[70]
  PIN a[71]
    DIRECTION INPUT ;
    USE SIGNAL ;
    PORT
      LAYER M4 ;
        RECT  104.004 39.792 104.088 39.816 ;
    END
  END a[71]
  PIN a[72]
    DIRECTION INPUT ;
    USE SIGNAL ;
    PORT
      LAYER M4 ;
        RECT  104.004 39.888 104.088 39.912 ;
    END
  END a[72]
  PIN a[73]
    DIRECTION INPUT ;
    USE SIGNAL ;
    PORT
      LAYER M4 ;
        RECT  104.004 39.984 104.088 40.008 ;
    END
  END a[73]
  PIN a[74]
    DIRECTION INPUT ;
    USE SIGNAL ;
    PORT
      LAYER M4 ;
        RECT  104.004 40.08 104.088 40.104 ;
    END
  END a[74]
  PIN a[75]
    DIRECTION INPUT ;
    USE SIGNAL ;
    PORT
      LAYER M4 ;
        RECT  104.004 40.176 104.088 40.2 ;
    END
  END a[75]
  PIN a[76]
    DIRECTION INPUT ;
    USE SIGNAL ;
    PORT
      LAYER M4 ;
        RECT  104.004 40.272 104.088 40.296 ;
    END
  END a[76]
  PIN a[77]
    DIRECTION INPUT ;
    USE SIGNAL ;
    PORT
      LAYER M4 ;
        RECT  104.004 40.368 104.088 40.392 ;
    END
  END a[77]
  PIN a[78]
    DIRECTION INPUT ;
    USE SIGNAL ;
    PORT
      LAYER M4 ;
        RECT  104.004 40.464 104.088 40.488 ;
    END
  END a[78]
  PIN a[79]
    DIRECTION INPUT ;
    USE SIGNAL ;
    PORT
      LAYER M4 ;
        RECT  104.004 40.56 104.088 40.584 ;
    END
  END a[79]
  PIN a[7]
    DIRECTION INPUT ;
    USE SIGNAL ;
    PORT
      LAYER M4 ;
        RECT  104.004 42.864 104.088 42.888 ;
    END
  END a[7]
  PIN a[80]
    DIRECTION INPUT ;
    USE SIGNAL ;
    PORT
      LAYER M4 ;
        RECT  104.004 40.656 104.088 40.68 ;
    END
  END a[80]
  PIN a[81]
    DIRECTION INPUT ;
    USE SIGNAL ;
    PORT
      LAYER M4 ;
        RECT  104.004 40.752 104.088 40.776 ;
    END
  END a[81]
  PIN a[82]
    DIRECTION INPUT ;
    USE SIGNAL ;
    PORT
      LAYER M4 ;
        RECT  104.004 40.848 104.088 40.872 ;
    END
  END a[82]
  PIN a[83]
    DIRECTION INPUT ;
    USE SIGNAL ;
    PORT
      LAYER M4 ;
        RECT  104.004 40.944 104.088 40.968 ;
    END
  END a[83]
  PIN a[84]
    DIRECTION INPUT ;
    USE SIGNAL ;
    PORT
      LAYER M4 ;
        RECT  104.004 41.04 104.088 41.064 ;
    END
  END a[84]
  PIN a[85]
    DIRECTION INPUT ;
    USE SIGNAL ;
    PORT
      LAYER M4 ;
        RECT  104.004 41.136 104.088 41.16 ;
    END
  END a[85]
  PIN a[86]
    DIRECTION INPUT ;
    USE SIGNAL ;
    PORT
      LAYER M4 ;
        RECT  104.004 41.232 104.088 41.256 ;
    END
  END a[86]
  PIN a[87]
    DIRECTION INPUT ;
    USE SIGNAL ;
    PORT
      LAYER M4 ;
        RECT  104.004 41.328 104.088 41.352 ;
    END
  END a[87]
  PIN a[88]
    DIRECTION INPUT ;
    USE SIGNAL ;
    PORT
      LAYER M4 ;
        RECT  104.004 41.424 104.088 41.448 ;
    END
  END a[88]
  PIN a[89]
    DIRECTION INPUT ;
    USE SIGNAL ;
    PORT
      LAYER M4 ;
        RECT  104.004 41.52 104.088 41.544 ;
    END
  END a[89]
  PIN a[8]
    DIRECTION INPUT ;
    USE SIGNAL ;
    PORT
      LAYER M4 ;
        RECT  104.004 42.96 104.088 42.984 ;
    END
  END a[8]
  PIN a[90]
    DIRECTION INPUT ;
    USE SIGNAL ;
    PORT
      LAYER M4 ;
        RECT  104.004 41.616 104.088 41.64 ;
    END
  END a[90]
  PIN a[91]
    DIRECTION INPUT ;
    USE SIGNAL ;
    PORT
      LAYER M4 ;
        RECT  104.004 41.712 104.088 41.736 ;
    END
  END a[91]
  PIN a[92]
    DIRECTION INPUT ;
    USE SIGNAL ;
    PORT
      LAYER M4 ;
        RECT  104.004 41.808 104.088 41.832 ;
    END
  END a[92]
  PIN a[93]
    DIRECTION INPUT ;
    USE SIGNAL ;
    PORT
      LAYER M4 ;
        RECT  104.004 41.904 104.088 41.928 ;
    END
  END a[93]
  PIN a[94]
    DIRECTION INPUT ;
    USE SIGNAL ;
    PORT
      LAYER M4 ;
        RECT  104.004 42 104.088 42.024 ;
    END
  END a[94]
  PIN a[95]
    DIRECTION INPUT ;
    USE SIGNAL ;
    PORT
      LAYER M4 ;
        RECT  104.004 42.096 104.088 42.12 ;
    END
  END a[95]
  PIN a[96]
    DIRECTION INPUT ;
    USE SIGNAL ;
    PORT
      LAYER M4 ;
        RECT  104.004 45.264 104.088 45.288 ;
    END
  END a[96]
  PIN a[97]
    DIRECTION INPUT ;
    USE SIGNAL ;
    PORT
      LAYER M4 ;
        RECT  104.004 45.36 104.088 45.384 ;
    END
  END a[97]
  PIN a[98]
    DIRECTION INPUT ;
    USE SIGNAL ;
    PORT
      LAYER M4 ;
        RECT  104.004 45.456 104.088 45.48 ;
    END
  END a[98]
  PIN a[99]
    DIRECTION INPUT ;
    USE SIGNAL ;
    PORT
      LAYER M4 ;
        RECT  104.004 45.552 104.088 45.576 ;
    END
  END a[99]
  PIN a[9]
    DIRECTION INPUT ;
    USE SIGNAL ;
    PORT
      LAYER M4 ;
        RECT  104.004 43.056 104.088 43.08 ;
    END
  END a[9]
  PIN b[0]
    DIRECTION OUTPUT ;
    USE SIGNAL ;
    PORT
      LAYER M3 ;
        RECT  55.764 105.779 55.782 105.816 ;
    END
  END b[0]
  PIN b[100]
    DIRECTION OUTPUT ;
    USE SIGNAL ;
    PORT
      LAYER M3 ;
        RECT  51.444 105.779 51.462 105.816 ;
    END
  END b[100]
  PIN b[101]
    DIRECTION OUTPUT ;
    USE SIGNAL ;
    PORT
      LAYER M3 ;
        RECT  51.516 105.779 51.534 105.816 ;
    END
  END b[101]
  PIN b[102]
    DIRECTION OUTPUT ;
    USE SIGNAL ;
    PORT
      LAYER M3 ;
        RECT  51.588 105.779 51.606 105.816 ;
    END
  END b[102]
  PIN b[103]
    DIRECTION OUTPUT ;
    USE SIGNAL ;
    PORT
      LAYER M3 ;
        RECT  51.66 105.779 51.678 105.816 ;
    END
  END b[103]
  PIN b[104]
    DIRECTION OUTPUT ;
    USE SIGNAL ;
    PORT
      LAYER M3 ;
        RECT  51.732 105.779 51.75 105.816 ;
    END
  END b[104]
  PIN b[105]
    DIRECTION OUTPUT ;
    USE SIGNAL ;
    PORT
      LAYER M3 ;
        RECT  51.804 105.779 51.822 105.816 ;
    END
  END b[105]
  PIN b[106]
    DIRECTION OUTPUT ;
    USE SIGNAL ;
    PORT
      LAYER M3 ;
        RECT  51.876 105.779 51.894 105.816 ;
    END
  END b[106]
  PIN b[107]
    DIRECTION OUTPUT ;
    USE SIGNAL ;
    PORT
      LAYER M3 ;
        RECT  51.948 105.779 51.966 105.816 ;
    END
  END b[107]
  PIN b[108]
    DIRECTION OUTPUT ;
    USE SIGNAL ;
    PORT
      LAYER M3 ;
        RECT  52.02 105.779 52.038 105.816 ;
    END
  END b[108]
  PIN b[109]
    DIRECTION OUTPUT ;
    USE SIGNAL ;
    PORT
      LAYER M3 ;
        RECT  52.092 105.779 52.11 105.816 ;
    END
  END b[109]
  PIN b[10]
    DIRECTION OUTPUT ;
    USE SIGNAL ;
    PORT
      LAYER M3 ;
        RECT  56.484 105.779 56.502 105.816 ;
    END
  END b[10]
  PIN b[110]
    DIRECTION OUTPUT ;
    USE SIGNAL ;
    PORT
      LAYER M3 ;
        RECT  52.164 105.779 52.182 105.816 ;
    END
  END b[110]
  PIN b[111]
    DIRECTION OUTPUT ;
    USE SIGNAL ;
    PORT
      LAYER M3 ;
        RECT  52.236 105.779 52.254 105.816 ;
    END
  END b[111]
  PIN b[112]
    DIRECTION OUTPUT ;
    USE SIGNAL ;
    PORT
      LAYER M3 ;
        RECT  52.308 105.779 52.326 105.816 ;
    END
  END b[112]
  PIN b[113]
    DIRECTION OUTPUT ;
    USE SIGNAL ;
    PORT
      LAYER M3 ;
        RECT  52.38 105.779 52.398 105.816 ;
    END
  END b[113]
  PIN b[114]
    DIRECTION OUTPUT ;
    USE SIGNAL ;
    PORT
      LAYER M3 ;
        RECT  52.452 105.779 52.47 105.816 ;
    END
  END b[114]
  PIN b[115]
    DIRECTION OUTPUT ;
    USE SIGNAL ;
    PORT
      LAYER M3 ;
        RECT  52.524 105.779 52.542 105.816 ;
    END
  END b[115]
  PIN b[116]
    DIRECTION OUTPUT ;
    USE SIGNAL ;
    PORT
      LAYER M3 ;
        RECT  52.596 105.779 52.614 105.816 ;
    END
  END b[116]
  PIN b[117]
    DIRECTION OUTPUT ;
    USE SIGNAL ;
    PORT
      LAYER M3 ;
        RECT  52.668 105.779 52.686 105.816 ;
    END
  END b[117]
  PIN b[118]
    DIRECTION OUTPUT ;
    USE SIGNAL ;
    PORT
      LAYER M3 ;
        RECT  52.74 105.779 52.758 105.816 ;
    END
  END b[118]
  PIN b[119]
    DIRECTION OUTPUT ;
    USE SIGNAL ;
    PORT
      LAYER M3 ;
        RECT  52.812 105.779 52.83 105.816 ;
    END
  END b[119]
  PIN b[11]
    DIRECTION OUTPUT ;
    USE SIGNAL ;
    PORT
      LAYER M3 ;
        RECT  56.556 105.779 56.574 105.816 ;
    END
  END b[11]
  PIN b[120]
    DIRECTION OUTPUT ;
    USE SIGNAL ;
    PORT
      LAYER M3 ;
        RECT  52.884 105.779 52.902 105.816 ;
    END
  END b[120]
  PIN b[121]
    DIRECTION OUTPUT ;
    USE SIGNAL ;
    PORT
      LAYER M3 ;
        RECT  52.956 105.779 52.974 105.816 ;
    END
  END b[121]
  PIN b[122]
    DIRECTION OUTPUT ;
    USE SIGNAL ;
    PORT
      LAYER M3 ;
        RECT  53.028 105.779 53.046 105.816 ;
    END
  END b[122]
  PIN b[123]
    DIRECTION OUTPUT ;
    USE SIGNAL ;
    PORT
      LAYER M3 ;
        RECT  53.1 105.779 53.118 105.816 ;
    END
  END b[123]
  PIN b[124]
    DIRECTION OUTPUT ;
    USE SIGNAL ;
    PORT
      LAYER M3 ;
        RECT  53.172 105.779 53.19 105.816 ;
    END
  END b[124]
  PIN b[125]
    DIRECTION OUTPUT ;
    USE SIGNAL ;
    PORT
      LAYER M3 ;
        RECT  53.244 105.779 53.262 105.816 ;
    END
  END b[125]
  PIN b[126]
    DIRECTION OUTPUT ;
    USE SIGNAL ;
    PORT
      LAYER M3 ;
        RECT  53.316 105.779 53.334 105.816 ;
    END
  END b[126]
  PIN b[127]
    DIRECTION OUTPUT ;
    USE SIGNAL ;
    PORT
      LAYER M3 ;
        RECT  53.388 105.779 53.406 105.816 ;
    END
  END b[127]
  PIN b[128]
    DIRECTION OUTPUT ;
    USE SIGNAL ;
    PORT
      LAYER M3 ;
        RECT  53.46 105.779 53.478 105.816 ;
    END
  END b[128]
  PIN b[129]
    DIRECTION OUTPUT ;
    USE SIGNAL ;
    PORT
      LAYER M3 ;
        RECT  53.532 105.779 53.55 105.816 ;
    END
  END b[129]
  PIN b[12]
    DIRECTION OUTPUT ;
    USE SIGNAL ;
    PORT
      LAYER M3 ;
        RECT  56.628 105.779 56.646 105.816 ;
    END
  END b[12]
  PIN b[130]
    DIRECTION OUTPUT ;
    USE SIGNAL ;
    PORT
      LAYER M3 ;
        RECT  53.604 105.779 53.622 105.816 ;
    END
  END b[130]
  PIN b[131]
    DIRECTION OUTPUT ;
    USE SIGNAL ;
    PORT
      LAYER M3 ;
        RECT  53.676 105.779 53.694 105.816 ;
    END
  END b[131]
  PIN b[132]
    DIRECTION OUTPUT ;
    USE SIGNAL ;
    PORT
      LAYER M3 ;
        RECT  53.748 105.779 53.766 105.816 ;
    END
  END b[132]
  PIN b[133]
    DIRECTION OUTPUT ;
    USE SIGNAL ;
    PORT
      LAYER M3 ;
        RECT  53.82 105.779 53.838 105.816 ;
    END
  END b[133]
  PIN b[134]
    DIRECTION OUTPUT ;
    USE SIGNAL ;
    PORT
      LAYER M3 ;
        RECT  53.892 105.779 53.91 105.816 ;
    END
  END b[134]
  PIN b[135]
    DIRECTION OUTPUT ;
    USE SIGNAL ;
    PORT
      LAYER M3 ;
        RECT  53.964 105.779 53.982 105.816 ;
    END
  END b[135]
  PIN b[136]
    DIRECTION OUTPUT ;
    USE SIGNAL ;
    PORT
      LAYER M3 ;
        RECT  54.036 105.779 54.054 105.816 ;
    END
  END b[136]
  PIN b[137]
    DIRECTION OUTPUT ;
    USE SIGNAL ;
    PORT
      LAYER M3 ;
        RECT  54.108 105.779 54.126 105.816 ;
    END
  END b[137]
  PIN b[138]
    DIRECTION OUTPUT ;
    USE SIGNAL ;
    PORT
      LAYER M3 ;
        RECT  54.18 105.779 54.198 105.816 ;
    END
  END b[138]
  PIN b[139]
    DIRECTION OUTPUT ;
    USE SIGNAL ;
    PORT
      LAYER M3 ;
        RECT  54.252 105.779 54.27 105.816 ;
    END
  END b[139]
  PIN b[13]
    DIRECTION OUTPUT ;
    USE SIGNAL ;
    PORT
      LAYER M3 ;
        RECT  56.7 105.779 56.718 105.816 ;
    END
  END b[13]
  PIN b[140]
    DIRECTION OUTPUT ;
    USE SIGNAL ;
    PORT
      LAYER M3 ;
        RECT  54.324 105.779 54.342 105.816 ;
    END
  END b[140]
  PIN b[141]
    DIRECTION OUTPUT ;
    USE SIGNAL ;
    PORT
      LAYER M3 ;
        RECT  54.396 105.779 54.414 105.816 ;
    END
  END b[141]
  PIN b[142]
    DIRECTION OUTPUT ;
    USE SIGNAL ;
    PORT
      LAYER M3 ;
        RECT  54.468 105.779 54.486 105.816 ;
    END
  END b[142]
  PIN b[143]
    DIRECTION OUTPUT ;
    USE SIGNAL ;
    PORT
      LAYER M3 ;
        RECT  54.54 105.779 54.558 105.816 ;
    END
  END b[143]
  PIN b[144]
    DIRECTION OUTPUT ;
    USE SIGNAL ;
    PORT
      LAYER M3 ;
        RECT  54.612 105.779 54.63 105.816 ;
    END
  END b[144]
  PIN b[145]
    DIRECTION OUTPUT ;
    USE SIGNAL ;
    PORT
      LAYER M3 ;
        RECT  54.684 105.779 54.702 105.816 ;
    END
  END b[145]
  PIN b[146]
    DIRECTION OUTPUT ;
    USE SIGNAL ;
    PORT
      LAYER M3 ;
        RECT  54.756 105.779 54.774 105.816 ;
    END
  END b[146]
  PIN b[147]
    DIRECTION OUTPUT ;
    USE SIGNAL ;
    PORT
      LAYER M3 ;
        RECT  54.828 105.779 54.846 105.816 ;
    END
  END b[147]
  PIN b[148]
    DIRECTION OUTPUT ;
    USE SIGNAL ;
    PORT
      LAYER M3 ;
        RECT  54.9 105.779 54.918 105.816 ;
    END
  END b[148]
  PIN b[149]
    DIRECTION OUTPUT ;
    USE SIGNAL ;
    PORT
      LAYER M3 ;
        RECT  54.972 105.779 54.99 105.816 ;
    END
  END b[149]
  PIN b[14]
    DIRECTION OUTPUT ;
    USE SIGNAL ;
    PORT
      LAYER M3 ;
        RECT  56.772 105.779 56.79 105.816 ;
    END
  END b[14]
  PIN b[150]
    DIRECTION OUTPUT ;
    USE SIGNAL ;
    PORT
      LAYER M3 ;
        RECT  55.044 105.779 55.062 105.816 ;
    END
  END b[150]
  PIN b[151]
    DIRECTION OUTPUT ;
    USE SIGNAL ;
    PORT
      LAYER M3 ;
        RECT  55.116 105.779 55.134 105.816 ;
    END
  END b[151]
  PIN b[152]
    DIRECTION OUTPUT ;
    USE SIGNAL ;
    PORT
      LAYER M3 ;
        RECT  55.188 105.779 55.206 105.816 ;
    END
  END b[152]
  PIN b[153]
    DIRECTION OUTPUT ;
    USE SIGNAL ;
    PORT
      LAYER M3 ;
        RECT  55.26 105.779 55.278 105.816 ;
    END
  END b[153]
  PIN b[154]
    DIRECTION OUTPUT ;
    USE SIGNAL ;
    PORT
      LAYER M3 ;
        RECT  55.332 105.779 55.35 105.816 ;
    END
  END b[154]
  PIN b[155]
    DIRECTION OUTPUT ;
    USE SIGNAL ;
    PORT
      LAYER M3 ;
        RECT  55.404 105.779 55.422 105.816 ;
    END
  END b[155]
  PIN b[156]
    DIRECTION OUTPUT ;
    USE SIGNAL ;
    PORT
      LAYER M3 ;
        RECT  55.476 105.779 55.494 105.816 ;
    END
  END b[156]
  PIN b[157]
    DIRECTION OUTPUT ;
    USE SIGNAL ;
    PORT
      LAYER M3 ;
        RECT  55.548 105.779 55.566 105.816 ;
    END
  END b[157]
  PIN b[158]
    DIRECTION OUTPUT ;
    USE SIGNAL ;
    PORT
      LAYER M3 ;
        RECT  55.62 105.779 55.638 105.816 ;
    END
  END b[158]
  PIN b[159]
    DIRECTION OUTPUT ;
    USE SIGNAL ;
    PORT
      LAYER M3 ;
        RECT  55.692 105.779 55.71 105.816 ;
    END
  END b[159]
  PIN b[15]
    DIRECTION OUTPUT ;
    USE SIGNAL ;
    PORT
      LAYER M3 ;
        RECT  56.844 105.779 56.862 105.816 ;
    END
  END b[15]
  PIN b[160]
    DIRECTION OUTPUT ;
    USE SIGNAL ;
    PORT
      LAYER M3 ;
        RECT  48.852 105.779 48.87 105.816 ;
    END
  END b[160]
  PIN b[161]
    DIRECTION OUTPUT ;
    USE SIGNAL ;
    PORT
      LAYER M3 ;
        RECT  48.924 105.779 48.942 105.816 ;
    END
  END b[161]
  PIN b[162]
    DIRECTION OUTPUT ;
    USE SIGNAL ;
    PORT
      LAYER M3 ;
        RECT  48.996 105.779 49.014 105.816 ;
    END
  END b[162]
  PIN b[163]
    DIRECTION OUTPUT ;
    USE SIGNAL ;
    PORT
      LAYER M3 ;
        RECT  49.068 105.779 49.086 105.816 ;
    END
  END b[163]
  PIN b[164]
    DIRECTION OUTPUT ;
    USE SIGNAL ;
    PORT
      LAYER M3 ;
        RECT  49.14 105.779 49.158 105.816 ;
    END
  END b[164]
  PIN b[165]
    DIRECTION OUTPUT ;
    USE SIGNAL ;
    PORT
      LAYER M3 ;
        RECT  49.212 105.779 49.23 105.816 ;
    END
  END b[165]
  PIN b[166]
    DIRECTION OUTPUT ;
    USE SIGNAL ;
    PORT
      LAYER M3 ;
        RECT  49.284 105.779 49.302 105.816 ;
    END
  END b[166]
  PIN b[167]
    DIRECTION OUTPUT ;
    USE SIGNAL ;
    PORT
      LAYER M3 ;
        RECT  49.356 105.779 49.374 105.816 ;
    END
  END b[167]
  PIN b[168]
    DIRECTION OUTPUT ;
    USE SIGNAL ;
    PORT
      LAYER M3 ;
        RECT  49.428 105.779 49.446 105.816 ;
    END
  END b[168]
  PIN b[169]
    DIRECTION OUTPUT ;
    USE SIGNAL ;
    PORT
      LAYER M3 ;
        RECT  49.5 105.779 49.518 105.816 ;
    END
  END b[169]
  PIN b[16]
    DIRECTION OUTPUT ;
    USE SIGNAL ;
    PORT
      LAYER M3 ;
        RECT  56.916 105.779 56.934 105.816 ;
    END
  END b[16]
  PIN b[170]
    DIRECTION OUTPUT ;
    USE SIGNAL ;
    PORT
      LAYER M3 ;
        RECT  49.572 105.779 49.59 105.816 ;
    END
  END b[170]
  PIN b[171]
    DIRECTION OUTPUT ;
    USE SIGNAL ;
    PORT
      LAYER M3 ;
        RECT  49.644 105.779 49.662 105.816 ;
    END
  END b[171]
  PIN b[172]
    DIRECTION OUTPUT ;
    USE SIGNAL ;
    PORT
      LAYER M3 ;
        RECT  49.716 105.779 49.734 105.816 ;
    END
  END b[172]
  PIN b[173]
    DIRECTION OUTPUT ;
    USE SIGNAL ;
    PORT
      LAYER M3 ;
        RECT  49.788 105.779 49.806 105.816 ;
    END
  END b[173]
  PIN b[174]
    DIRECTION OUTPUT ;
    USE SIGNAL ;
    PORT
      LAYER M3 ;
        RECT  49.86 105.779 49.878 105.816 ;
    END
  END b[174]
  PIN b[175]
    DIRECTION OUTPUT ;
    USE SIGNAL ;
    PORT
      LAYER M3 ;
        RECT  49.932 105.779 49.95 105.816 ;
    END
  END b[175]
  PIN b[176]
    DIRECTION OUTPUT ;
    USE SIGNAL ;
    PORT
      LAYER M3 ;
        RECT  50.004 105.779 50.022 105.816 ;
    END
  END b[176]
  PIN b[177]
    DIRECTION OUTPUT ;
    USE SIGNAL ;
    PORT
      LAYER M3 ;
        RECT  50.076 105.779 50.094 105.816 ;
    END
  END b[177]
  PIN b[178]
    DIRECTION OUTPUT ;
    USE SIGNAL ;
    PORT
      LAYER M3 ;
        RECT  50.148 105.779 50.166 105.816 ;
    END
  END b[178]
  PIN b[179]
    DIRECTION OUTPUT ;
    USE SIGNAL ;
    PORT
      LAYER M3 ;
        RECT  50.22 105.779 50.238 105.816 ;
    END
  END b[179]
  PIN b[17]
    DIRECTION OUTPUT ;
    USE SIGNAL ;
    PORT
      LAYER M3 ;
        RECT  56.988 105.779 57.006 105.816 ;
    END
  END b[17]
  PIN b[180]
    DIRECTION OUTPUT ;
    USE SIGNAL ;
    PORT
      LAYER M3 ;
        RECT  50.292 105.779 50.31 105.816 ;
    END
  END b[180]
  PIN b[181]
    DIRECTION OUTPUT ;
    USE SIGNAL ;
    PORT
      LAYER M3 ;
        RECT  50.364 105.779 50.382 105.816 ;
    END
  END b[181]
  PIN b[182]
    DIRECTION OUTPUT ;
    USE SIGNAL ;
    PORT
      LAYER M3 ;
        RECT  50.436 105.779 50.454 105.816 ;
    END
  END b[182]
  PIN b[183]
    DIRECTION OUTPUT ;
    USE SIGNAL ;
    PORT
      LAYER M3 ;
        RECT  50.508 105.779 50.526 105.816 ;
    END
  END b[183]
  PIN b[184]
    DIRECTION OUTPUT ;
    USE SIGNAL ;
    PORT
      LAYER M3 ;
        RECT  50.58 105.779 50.598 105.816 ;
    END
  END b[184]
  PIN b[185]
    DIRECTION OUTPUT ;
    USE SIGNAL ;
    PORT
      LAYER M3 ;
        RECT  50.652 105.779 50.67 105.816 ;
    END
  END b[185]
  PIN b[186]
    DIRECTION OUTPUT ;
    USE SIGNAL ;
    PORT
      LAYER M3 ;
        RECT  50.724 105.779 50.742 105.816 ;
    END
  END b[186]
  PIN b[187]
    DIRECTION OUTPUT ;
    USE SIGNAL ;
    PORT
      LAYER M3 ;
        RECT  50.796 105.779 50.814 105.816 ;
    END
  END b[187]
  PIN b[188]
    DIRECTION OUTPUT ;
    USE SIGNAL ;
    PORT
      LAYER M3 ;
        RECT  50.868 105.779 50.886 105.816 ;
    END
  END b[188]
  PIN b[189]
    DIRECTION OUTPUT ;
    USE SIGNAL ;
    PORT
      LAYER M3 ;
        RECT  50.94 105.779 50.958 105.816 ;
    END
  END b[189]
  PIN b[18]
    DIRECTION OUTPUT ;
    USE SIGNAL ;
    PORT
      LAYER M3 ;
        RECT  57.06 105.779 57.078 105.816 ;
    END
  END b[18]
  PIN b[190]
    DIRECTION OUTPUT ;
    USE SIGNAL ;
    PORT
      LAYER M3 ;
        RECT  51.012 105.779 51.03 105.816 ;
    END
  END b[190]
  PIN b[191]
    DIRECTION OUTPUT ;
    USE SIGNAL ;
    PORT
      LAYER M3 ;
        RECT  51.084 105.779 51.102 105.816 ;
    END
  END b[191]
  PIN b[192]
    DIRECTION OUTPUT ;
    USE SIGNAL ;
    PORT
      LAYER M5 ;
        RECT  49.68 105.732 49.704 105.816 ;
    END
  END b[192]
  PIN b[193]
    DIRECTION OUTPUT ;
    USE SIGNAL ;
    PORT
      LAYER M5 ;
        RECT  49.776 105.732 49.8 105.816 ;
    END
  END b[193]
  PIN b[194]
    DIRECTION OUTPUT ;
    USE SIGNAL ;
    PORT
      LAYER M5 ;
        RECT  49.872 105.732 49.896 105.816 ;
    END
  END b[194]
  PIN b[195]
    DIRECTION OUTPUT ;
    USE SIGNAL ;
    PORT
      LAYER M5 ;
        RECT  49.968 105.732 49.992 105.816 ;
    END
  END b[195]
  PIN b[196]
    DIRECTION OUTPUT ;
    USE SIGNAL ;
    PORT
      LAYER M5 ;
        RECT  50.064 105.732 50.088 105.816 ;
    END
  END b[196]
  PIN b[197]
    DIRECTION OUTPUT ;
    USE SIGNAL ;
    PORT
      LAYER M5 ;
        RECT  50.16 105.732 50.184 105.816 ;
    END
  END b[197]
  PIN b[198]
    DIRECTION OUTPUT ;
    USE SIGNAL ;
    PORT
      LAYER M5 ;
        RECT  50.256 105.732 50.28 105.816 ;
    END
  END b[198]
  PIN b[199]
    DIRECTION OUTPUT ;
    USE SIGNAL ;
    PORT
      LAYER M5 ;
        RECT  50.352 105.732 50.376 105.816 ;
    END
  END b[199]
  PIN b[19]
    DIRECTION OUTPUT ;
    USE SIGNAL ;
    PORT
      LAYER M3 ;
        RECT  57.132 105.779 57.15 105.816 ;
    END
  END b[19]
  PIN b[1]
    DIRECTION OUTPUT ;
    USE SIGNAL ;
    PORT
      LAYER M3 ;
        RECT  55.836 105.779 55.854 105.816 ;
    END
  END b[1]
  PIN b[200]
    DIRECTION OUTPUT ;
    USE SIGNAL ;
    PORT
      LAYER M5 ;
        RECT  50.448 105.732 50.472 105.816 ;
    END
  END b[200]
  PIN b[201]
    DIRECTION OUTPUT ;
    USE SIGNAL ;
    PORT
      LAYER M5 ;
        RECT  50.544 105.732 50.568 105.816 ;
    END
  END b[201]
  PIN b[202]
    DIRECTION OUTPUT ;
    USE SIGNAL ;
    PORT
      LAYER M5 ;
        RECT  50.64 105.732 50.664 105.816 ;
    END
  END b[202]
  PIN b[203]
    DIRECTION OUTPUT ;
    USE SIGNAL ;
    PORT
      LAYER M5 ;
        RECT  50.736 105.732 50.76 105.816 ;
    END
  END b[203]
  PIN b[204]
    DIRECTION OUTPUT ;
    USE SIGNAL ;
    PORT
      LAYER M5 ;
        RECT  50.832 105.732 50.856 105.816 ;
    END
  END b[204]
  PIN b[205]
    DIRECTION OUTPUT ;
    USE SIGNAL ;
    PORT
      LAYER M5 ;
        RECT  50.928 105.732 50.952 105.816 ;
    END
  END b[205]
  PIN b[206]
    DIRECTION OUTPUT ;
    USE SIGNAL ;
    PORT
      LAYER M5 ;
        RECT  51.024 105.732 51.048 105.816 ;
    END
  END b[206]
  PIN b[207]
    DIRECTION OUTPUT ;
    USE SIGNAL ;
    PORT
      LAYER M5 ;
        RECT  51.12 105.732 51.144 105.816 ;
    END
  END b[207]
  PIN b[208]
    DIRECTION OUTPUT ;
    USE SIGNAL ;
    PORT
      LAYER M5 ;
        RECT  51.216 105.732 51.24 105.816 ;
    END
  END b[208]
  PIN b[209]
    DIRECTION OUTPUT ;
    USE SIGNAL ;
    PORT
      LAYER M5 ;
        RECT  51.312 105.732 51.336 105.816 ;
    END
  END b[209]
  PIN b[20]
    DIRECTION OUTPUT ;
    USE SIGNAL ;
    PORT
      LAYER M3 ;
        RECT  57.204 105.779 57.222 105.816 ;
    END
  END b[20]
  PIN b[210]
    DIRECTION OUTPUT ;
    USE SIGNAL ;
    PORT
      LAYER M5 ;
        RECT  51.408 105.732 51.432 105.816 ;
    END
  END b[210]
  PIN b[211]
    DIRECTION OUTPUT ;
    USE SIGNAL ;
    PORT
      LAYER M5 ;
        RECT  51.504 105.732 51.528 105.816 ;
    END
  END b[211]
  PIN b[212]
    DIRECTION OUTPUT ;
    USE SIGNAL ;
    PORT
      LAYER M5 ;
        RECT  51.6 105.732 51.624 105.816 ;
    END
  END b[212]
  PIN b[213]
    DIRECTION OUTPUT ;
    USE SIGNAL ;
    PORT
      LAYER M5 ;
        RECT  51.696 105.732 51.72 105.816 ;
    END
  END b[213]
  PIN b[214]
    DIRECTION OUTPUT ;
    USE SIGNAL ;
    PORT
      LAYER M5 ;
        RECT  51.792 105.732 51.816 105.816 ;
    END
  END b[214]
  PIN b[215]
    DIRECTION OUTPUT ;
    USE SIGNAL ;
    PORT
      LAYER M5 ;
        RECT  51.888 105.732 51.912 105.816 ;
    END
  END b[215]
  PIN b[216]
    DIRECTION OUTPUT ;
    USE SIGNAL ;
    PORT
      LAYER M5 ;
        RECT  51.984 105.732 52.008 105.816 ;
    END
  END b[216]
  PIN b[217]
    DIRECTION OUTPUT ;
    USE SIGNAL ;
    PORT
      LAYER M5 ;
        RECT  52.08 105.732 52.104 105.816 ;
    END
  END b[217]
  PIN b[218]
    DIRECTION OUTPUT ;
    USE SIGNAL ;
    PORT
      LAYER M5 ;
        RECT  52.176 105.732 52.2 105.816 ;
    END
  END b[218]
  PIN b[219]
    DIRECTION OUTPUT ;
    USE SIGNAL ;
    PORT
      LAYER M5 ;
        RECT  52.272 105.732 52.296 105.816 ;
    END
  END b[219]
  PIN b[21]
    DIRECTION OUTPUT ;
    USE SIGNAL ;
    PORT
      LAYER M3 ;
        RECT  57.276 105.779 57.294 105.816 ;
    END
  END b[21]
  PIN b[220]
    DIRECTION OUTPUT ;
    USE SIGNAL ;
    PORT
      LAYER M5 ;
        RECT  52.368 105.732 52.392 105.816 ;
    END
  END b[220]
  PIN b[221]
    DIRECTION OUTPUT ;
    USE SIGNAL ;
    PORT
      LAYER M5 ;
        RECT  52.464 105.732 52.488 105.816 ;
    END
  END b[221]
  PIN b[222]
    DIRECTION OUTPUT ;
    USE SIGNAL ;
    PORT
      LAYER M5 ;
        RECT  52.56 105.732 52.584 105.816 ;
    END
  END b[222]
  PIN b[223]
    DIRECTION OUTPUT ;
    USE SIGNAL ;
    PORT
      LAYER M5 ;
        RECT  52.656 105.732 52.68 105.816 ;
    END
  END b[223]
  PIN b[224]
    DIRECTION OUTPUT ;
    USE SIGNAL ;
    PORT
      LAYER M5 ;
        RECT  52.752 105.732 52.776 105.816 ;
    END
  END b[224]
  PIN b[225]
    DIRECTION OUTPUT ;
    USE SIGNAL ;
    PORT
      LAYER M5 ;
        RECT  52.848 105.732 52.872 105.816 ;
    END
  END b[225]
  PIN b[226]
    DIRECTION OUTPUT ;
    USE SIGNAL ;
    PORT
      LAYER M5 ;
        RECT  52.944 105.732 52.968 105.816 ;
    END
  END b[226]
  PIN b[227]
    DIRECTION OUTPUT ;
    USE SIGNAL ;
    PORT
      LAYER M5 ;
        RECT  53.04 105.732 53.064 105.816 ;
    END
  END b[227]
  PIN b[228]
    DIRECTION OUTPUT ;
    USE SIGNAL ;
    PORT
      LAYER M5 ;
        RECT  53.136 105.732 53.16 105.816 ;
    END
  END b[228]
  PIN b[229]
    DIRECTION OUTPUT ;
    USE SIGNAL ;
    PORT
      LAYER M5 ;
        RECT  53.232 105.732 53.256 105.816 ;
    END
  END b[229]
  PIN b[22]
    DIRECTION OUTPUT ;
    USE SIGNAL ;
    PORT
      LAYER M3 ;
        RECT  57.348 105.779 57.366 105.816 ;
    END
  END b[22]
  PIN b[230]
    DIRECTION OUTPUT ;
    USE SIGNAL ;
    PORT
      LAYER M5 ;
        RECT  53.328 105.732 53.352 105.816 ;
    END
  END b[230]
  PIN b[231]
    DIRECTION OUTPUT ;
    USE SIGNAL ;
    PORT
      LAYER M5 ;
        RECT  53.424 105.732 53.448 105.816 ;
    END
  END b[231]
  PIN b[232]
    DIRECTION OUTPUT ;
    USE SIGNAL ;
    PORT
      LAYER M5 ;
        RECT  53.52 105.732 53.544 105.816 ;
    END
  END b[232]
  PIN b[233]
    DIRECTION OUTPUT ;
    USE SIGNAL ;
    PORT
      LAYER M5 ;
        RECT  53.616 105.732 53.64 105.816 ;
    END
  END b[233]
  PIN b[234]
    DIRECTION OUTPUT ;
    USE SIGNAL ;
    PORT
      LAYER M5 ;
        RECT  53.712 105.732 53.736 105.816 ;
    END
  END b[234]
  PIN b[235]
    DIRECTION OUTPUT ;
    USE SIGNAL ;
    PORT
      LAYER M5 ;
        RECT  53.808 105.732 53.832 105.816 ;
    END
  END b[235]
  PIN b[236]
    DIRECTION OUTPUT ;
    USE SIGNAL ;
    PORT
      LAYER M5 ;
        RECT  53.904 105.732 53.928 105.816 ;
    END
  END b[236]
  PIN b[237]
    DIRECTION OUTPUT ;
    USE SIGNAL ;
    PORT
      LAYER M5 ;
        RECT  54 105.732 54.024 105.816 ;
    END
  END b[237]
  PIN b[238]
    DIRECTION OUTPUT ;
    USE SIGNAL ;
    PORT
      LAYER M5 ;
        RECT  54.096 105.732 54.12 105.816 ;
    END
  END b[238]
  PIN b[239]
    DIRECTION OUTPUT ;
    USE SIGNAL ;
    PORT
      LAYER M5 ;
        RECT  54.192 105.732 54.216 105.816 ;
    END
  END b[239]
  PIN b[23]
    DIRECTION OUTPUT ;
    USE SIGNAL ;
    PORT
      LAYER M3 ;
        RECT  57.42 105.779 57.438 105.816 ;
    END
  END b[23]
  PIN b[240]
    DIRECTION OUTPUT ;
    USE SIGNAL ;
    PORT
      LAYER M5 ;
        RECT  54.288 105.732 54.312 105.816 ;
    END
  END b[240]
  PIN b[241]
    DIRECTION OUTPUT ;
    USE SIGNAL ;
    PORT
      LAYER M5 ;
        RECT  54.384 105.732 54.408 105.816 ;
    END
  END b[241]
  PIN b[242]
    DIRECTION OUTPUT ;
    USE SIGNAL ;
    PORT
      LAYER M5 ;
        RECT  54.48 105.732 54.504 105.816 ;
    END
  END b[242]
  PIN b[243]
    DIRECTION OUTPUT ;
    USE SIGNAL ;
    PORT
      LAYER M5 ;
        RECT  54.576 105.732 54.6 105.816 ;
    END
  END b[243]
  PIN b[244]
    DIRECTION OUTPUT ;
    USE SIGNAL ;
    PORT
      LAYER M5 ;
        RECT  54.672 105.732 54.696 105.816 ;
    END
  END b[244]
  PIN b[245]
    DIRECTION OUTPUT ;
    USE SIGNAL ;
    PORT
      LAYER M5 ;
        RECT  54.768 105.732 54.792 105.816 ;
    END
  END b[245]
  PIN b[246]
    DIRECTION OUTPUT ;
    USE SIGNAL ;
    PORT
      LAYER M5 ;
        RECT  54.864 105.732 54.888 105.816 ;
    END
  END b[246]
  PIN b[247]
    DIRECTION OUTPUT ;
    USE SIGNAL ;
    PORT
      LAYER M5 ;
        RECT  54.96 105.732 54.984 105.816 ;
    END
  END b[247]
  PIN b[248]
    DIRECTION OUTPUT ;
    USE SIGNAL ;
    PORT
      LAYER M5 ;
        RECT  55.056 105.732 55.08 105.816 ;
    END
  END b[248]
  PIN b[249]
    DIRECTION OUTPUT ;
    USE SIGNAL ;
    PORT
      LAYER M5 ;
        RECT  55.152 105.732 55.176 105.816 ;
    END
  END b[249]
  PIN b[24]
    DIRECTION OUTPUT ;
    USE SIGNAL ;
    PORT
      LAYER M3 ;
        RECT  57.492 105.779 57.51 105.816 ;
    END
  END b[24]
  PIN b[250]
    DIRECTION OUTPUT ;
    USE SIGNAL ;
    PORT
      LAYER M5 ;
        RECT  55.248 105.732 55.272 105.816 ;
    END
  END b[250]
  PIN b[251]
    DIRECTION OUTPUT ;
    USE SIGNAL ;
    PORT
      LAYER M5 ;
        RECT  55.344 105.732 55.368 105.816 ;
    END
  END b[251]
  PIN b[252]
    DIRECTION OUTPUT ;
    USE SIGNAL ;
    PORT
      LAYER M5 ;
        RECT  55.44 105.732 55.464 105.816 ;
    END
  END b[252]
  PIN b[253]
    DIRECTION OUTPUT ;
    USE SIGNAL ;
    PORT
      LAYER M5 ;
        RECT  55.536 105.732 55.56 105.816 ;
    END
  END b[253]
  PIN b[254]
    DIRECTION OUTPUT ;
    USE SIGNAL ;
    PORT
      LAYER M5 ;
        RECT  55.632 105.732 55.656 105.816 ;
    END
  END b[254]
  PIN b[255]
    DIRECTION OUTPUT ;
    USE SIGNAL ;
    PORT
      LAYER M5 ;
        RECT  55.728 105.732 55.752 105.816 ;
    END
  END b[255]
  PIN b[256]
    DIRECTION OUTPUT ;
    USE SIGNAL ;
    PORT
      LAYER M5 ;
        RECT  55.824 105.732 55.848 105.816 ;
    END
  END b[256]
  PIN b[257]
    DIRECTION OUTPUT ;
    USE SIGNAL ;
    PORT
      LAYER M5 ;
        RECT  55.92 105.732 55.944 105.816 ;
    END
  END b[257]
  PIN b[258]
    DIRECTION OUTPUT ;
    USE SIGNAL ;
    PORT
      LAYER M5 ;
        RECT  56.016 105.732 56.04 105.816 ;
    END
  END b[258]
  PIN b[259]
    DIRECTION OUTPUT ;
    USE SIGNAL ;
    PORT
      LAYER M5 ;
        RECT  56.112 105.732 56.136 105.816 ;
    END
  END b[259]
  PIN b[25]
    DIRECTION OUTPUT ;
    USE SIGNAL ;
    PORT
      LAYER M3 ;
        RECT  57.564 105.779 57.582 105.816 ;
    END
  END b[25]
  PIN b[260]
    DIRECTION OUTPUT ;
    USE SIGNAL ;
    PORT
      LAYER M5 ;
        RECT  56.208 105.732 56.232 105.816 ;
    END
  END b[260]
  PIN b[261]
    DIRECTION OUTPUT ;
    USE SIGNAL ;
    PORT
      LAYER M5 ;
        RECT  56.304 105.732 56.328 105.816 ;
    END
  END b[261]
  PIN b[262]
    DIRECTION OUTPUT ;
    USE SIGNAL ;
    PORT
      LAYER M5 ;
        RECT  56.4 105.732 56.424 105.816 ;
    END
  END b[262]
  PIN b[263]
    DIRECTION OUTPUT ;
    USE SIGNAL ;
    PORT
      LAYER M5 ;
        RECT  56.496 105.732 56.52 105.816 ;
    END
  END b[263]
  PIN b[264]
    DIRECTION OUTPUT ;
    USE SIGNAL ;
    PORT
      LAYER M5 ;
        RECT  56.592 105.732 56.616 105.816 ;
    END
  END b[264]
  PIN b[265]
    DIRECTION OUTPUT ;
    USE SIGNAL ;
    PORT
      LAYER M5 ;
        RECT  56.688 105.732 56.712 105.816 ;
    END
  END b[265]
  PIN b[266]
    DIRECTION OUTPUT ;
    USE SIGNAL ;
    PORT
      LAYER M5 ;
        RECT  56.784 105.732 56.808 105.816 ;
    END
  END b[266]
  PIN b[267]
    DIRECTION OUTPUT ;
    USE SIGNAL ;
    PORT
      LAYER M5 ;
        RECT  56.88 105.732 56.904 105.816 ;
    END
  END b[267]
  PIN b[268]
    DIRECTION OUTPUT ;
    USE SIGNAL ;
    PORT
      LAYER M5 ;
        RECT  56.976 105.732 57 105.816 ;
    END
  END b[268]
  PIN b[269]
    DIRECTION OUTPUT ;
    USE SIGNAL ;
    PORT
      LAYER M5 ;
        RECT  57.072 105.732 57.096 105.816 ;
    END
  END b[269]
  PIN b[26]
    DIRECTION OUTPUT ;
    USE SIGNAL ;
    PORT
      LAYER M3 ;
        RECT  57.636 105.779 57.654 105.816 ;
    END
  END b[26]
  PIN b[270]
    DIRECTION OUTPUT ;
    USE SIGNAL ;
    PORT
      LAYER M5 ;
        RECT  57.168 105.732 57.192 105.816 ;
    END
  END b[270]
  PIN b[271]
    DIRECTION OUTPUT ;
    USE SIGNAL ;
    PORT
      LAYER M5 ;
        RECT  57.264 105.732 57.288 105.816 ;
    END
  END b[271]
  PIN b[272]
    DIRECTION OUTPUT ;
    USE SIGNAL ;
    PORT
      LAYER M5 ;
        RECT  57.36 105.732 57.384 105.816 ;
    END
  END b[272]
  PIN b[273]
    DIRECTION OUTPUT ;
    USE SIGNAL ;
    PORT
      LAYER M5 ;
        RECT  57.456 105.732 57.48 105.816 ;
    END
  END b[273]
  PIN b[274]
    DIRECTION OUTPUT ;
    USE SIGNAL ;
    PORT
      LAYER M5 ;
        RECT  57.552 105.732 57.576 105.816 ;
    END
  END b[274]
  PIN b[275]
    DIRECTION OUTPUT ;
    USE SIGNAL ;
    PORT
      LAYER M5 ;
        RECT  57.648 105.732 57.672 105.816 ;
    END
  END b[275]
  PIN b[276]
    DIRECTION OUTPUT ;
    USE SIGNAL ;
    PORT
      LAYER M5 ;
        RECT  57.744 105.732 57.768 105.816 ;
    END
  END b[276]
  PIN b[277]
    DIRECTION OUTPUT ;
    USE SIGNAL ;
    PORT
      LAYER M5 ;
        RECT  57.84 105.732 57.864 105.816 ;
    END
  END b[277]
  PIN b[278]
    DIRECTION OUTPUT ;
    USE SIGNAL ;
    PORT
      LAYER M5 ;
        RECT  57.936 105.732 57.96 105.816 ;
    END
  END b[278]
  PIN b[279]
    DIRECTION OUTPUT ;
    USE SIGNAL ;
    PORT
      LAYER M5 ;
        RECT  58.032 105.732 58.056 105.816 ;
    END
  END b[279]
  PIN b[27]
    DIRECTION OUTPUT ;
    USE SIGNAL ;
    PORT
      LAYER M3 ;
        RECT  57.708 105.779 57.726 105.816 ;
    END
  END b[27]
  PIN b[280]
    DIRECTION OUTPUT ;
    USE SIGNAL ;
    PORT
      LAYER M5 ;
        RECT  58.128 105.732 58.152 105.816 ;
    END
  END b[280]
  PIN b[281]
    DIRECTION OUTPUT ;
    USE SIGNAL ;
    PORT
      LAYER M5 ;
        RECT  58.224 105.732 58.248 105.816 ;
    END
  END b[281]
  PIN b[282]
    DIRECTION OUTPUT ;
    USE SIGNAL ;
    PORT
      LAYER M5 ;
        RECT  58.32 105.732 58.344 105.816 ;
    END
  END b[282]
  PIN b[283]
    DIRECTION OUTPUT ;
    USE SIGNAL ;
    PORT
      LAYER M5 ;
        RECT  58.416 105.732 58.44 105.816 ;
    END
  END b[283]
  PIN b[284]
    DIRECTION OUTPUT ;
    USE SIGNAL ;
    PORT
      LAYER M5 ;
        RECT  58.512 105.732 58.536 105.816 ;
    END
  END b[284]
  PIN b[285]
    DIRECTION OUTPUT ;
    USE SIGNAL ;
    PORT
      LAYER M5 ;
        RECT  58.608 105.732 58.632 105.816 ;
    END
  END b[285]
  PIN b[286]
    DIRECTION OUTPUT ;
    USE SIGNAL ;
    PORT
      LAYER M5 ;
        RECT  58.704 105.732 58.728 105.816 ;
    END
  END b[286]
  PIN b[287]
    DIRECTION OUTPUT ;
    USE SIGNAL ;
    PORT
      LAYER M5 ;
        RECT  58.8 105.732 58.824 105.816 ;
    END
  END b[287]
  PIN b[288]
    DIRECTION OUTPUT ;
    USE SIGNAL ;
    PORT
      LAYER M5 ;
        RECT  58.896 105.732 58.92 105.816 ;
    END
  END b[288]
  PIN b[289]
    DIRECTION OUTPUT ;
    USE SIGNAL ;
    PORT
      LAYER M5 ;
        RECT  58.992 105.732 59.016 105.816 ;
    END
  END b[289]
  PIN b[28]
    DIRECTION OUTPUT ;
    USE SIGNAL ;
    PORT
      LAYER M3 ;
        RECT  57.78 105.779 57.798 105.816 ;
    END
  END b[28]
  PIN b[290]
    DIRECTION OUTPUT ;
    USE SIGNAL ;
    PORT
      LAYER M5 ;
        RECT  59.088 105.732 59.112 105.816 ;
    END
  END b[290]
  PIN b[291]
    DIRECTION OUTPUT ;
    USE SIGNAL ;
    PORT
      LAYER M5 ;
        RECT  59.184 105.732 59.208 105.816 ;
    END
  END b[291]
  PIN b[292]
    DIRECTION OUTPUT ;
    USE SIGNAL ;
    PORT
      LAYER M5 ;
        RECT  59.28 105.732 59.304 105.816 ;
    END
  END b[292]
  PIN b[293]
    DIRECTION OUTPUT ;
    USE SIGNAL ;
    PORT
      LAYER M5 ;
        RECT  59.376 105.732 59.4 105.816 ;
    END
  END b[293]
  PIN b[294]
    DIRECTION OUTPUT ;
    USE SIGNAL ;
    PORT
      LAYER M5 ;
        RECT  59.472 105.732 59.496 105.816 ;
    END
  END b[294]
  PIN b[295]
    DIRECTION OUTPUT ;
    USE SIGNAL ;
    PORT
      LAYER M5 ;
        RECT  59.568 105.732 59.592 105.816 ;
    END
  END b[295]
  PIN b[296]
    DIRECTION OUTPUT ;
    USE SIGNAL ;
    PORT
      LAYER M5 ;
        RECT  59.664 105.732 59.688 105.816 ;
    END
  END b[296]
  PIN b[297]
    DIRECTION OUTPUT ;
    USE SIGNAL ;
    PORT
      LAYER M5 ;
        RECT  59.76 105.732 59.784 105.816 ;
    END
  END b[297]
  PIN b[298]
    DIRECTION OUTPUT ;
    USE SIGNAL ;
    PORT
      LAYER M5 ;
        RECT  59.856 105.732 59.88 105.816 ;
    END
  END b[298]
  PIN b[299]
    DIRECTION OUTPUT ;
    USE SIGNAL ;
    PORT
      LAYER M5 ;
        RECT  59.952 105.732 59.976 105.816 ;
    END
  END b[299]
  PIN b[29]
    DIRECTION OUTPUT ;
    USE SIGNAL ;
    PORT
      LAYER M3 ;
        RECT  57.852 105.779 57.87 105.816 ;
    END
  END b[29]
  PIN b[2]
    DIRECTION OUTPUT ;
    USE SIGNAL ;
    PORT
      LAYER M3 ;
        RECT  55.908 105.779 55.926 105.816 ;
    END
  END b[2]
  PIN b[300]
    DIRECTION OUTPUT ;
    USE SIGNAL ;
    PORT
      LAYER M5 ;
        RECT  60.048 105.732 60.072 105.816 ;
    END
  END b[300]
  PIN b[301]
    DIRECTION OUTPUT ;
    USE SIGNAL ;
    PORT
      LAYER M5 ;
        RECT  60.144 105.732 60.168 105.816 ;
    END
  END b[301]
  PIN b[302]
    DIRECTION OUTPUT ;
    USE SIGNAL ;
    PORT
      LAYER M5 ;
        RECT  60.24 105.732 60.264 105.816 ;
    END
  END b[302]
  PIN b[303]
    DIRECTION OUTPUT ;
    USE SIGNAL ;
    PORT
      LAYER M5 ;
        RECT  60.336 105.732 60.36 105.816 ;
    END
  END b[303]
  PIN b[304]
    DIRECTION OUTPUT ;
    USE SIGNAL ;
    PORT
      LAYER M5 ;
        RECT  60.432 105.732 60.456 105.816 ;
    END
  END b[304]
  PIN b[305]
    DIRECTION OUTPUT ;
    USE SIGNAL ;
    PORT
      LAYER M5 ;
        RECT  60.528 105.732 60.552 105.816 ;
    END
  END b[305]
  PIN b[306]
    DIRECTION OUTPUT ;
    USE SIGNAL ;
    PORT
      LAYER M5 ;
        RECT  60.624 105.732 60.648 105.816 ;
    END
  END b[306]
  PIN b[307]
    DIRECTION OUTPUT ;
    USE SIGNAL ;
    PORT
      LAYER M5 ;
        RECT  60.72 105.732 60.744 105.816 ;
    END
  END b[307]
  PIN b[308]
    DIRECTION OUTPUT ;
    USE SIGNAL ;
    PORT
      LAYER M5 ;
        RECT  60.816 105.732 60.84 105.816 ;
    END
  END b[308]
  PIN b[309]
    DIRECTION OUTPUT ;
    USE SIGNAL ;
    PORT
      LAYER M5 ;
        RECT  60.912 105.732 60.936 105.816 ;
    END
  END b[309]
  PIN b[30]
    DIRECTION OUTPUT ;
    USE SIGNAL ;
    PORT
      LAYER M3 ;
        RECT  57.924 105.779 57.942 105.816 ;
    END
  END b[30]
  PIN b[310]
    DIRECTION OUTPUT ;
    USE SIGNAL ;
    PORT
      LAYER M5 ;
        RECT  61.008 105.732 61.032 105.816 ;
    END
  END b[310]
  PIN b[311]
    DIRECTION OUTPUT ;
    USE SIGNAL ;
    PORT
      LAYER M5 ;
        RECT  61.104 105.732 61.128 105.816 ;
    END
  END b[311]
  PIN b[312]
    DIRECTION OUTPUT ;
    USE SIGNAL ;
    PORT
      LAYER M5 ;
        RECT  61.2 105.732 61.224 105.816 ;
    END
  END b[312]
  PIN b[313]
    DIRECTION OUTPUT ;
    USE SIGNAL ;
    PORT
      LAYER M5 ;
        RECT  61.296 105.732 61.32 105.816 ;
    END
  END b[313]
  PIN b[314]
    DIRECTION OUTPUT ;
    USE SIGNAL ;
    PORT
      LAYER M5 ;
        RECT  61.392 105.732 61.416 105.816 ;
    END
  END b[314]
  PIN b[315]
    DIRECTION OUTPUT ;
    USE SIGNAL ;
    PORT
      LAYER M5 ;
        RECT  61.488 105.732 61.512 105.816 ;
    END
  END b[315]
  PIN b[316]
    DIRECTION OUTPUT ;
    USE SIGNAL ;
    PORT
      LAYER M5 ;
        RECT  61.584 105.732 61.608 105.816 ;
    END
  END b[316]
  PIN b[317]
    DIRECTION OUTPUT ;
    USE SIGNAL ;
    PORT
      LAYER M5 ;
        RECT  61.68 105.732 61.704 105.816 ;
    END
  END b[317]
  PIN b[318]
    DIRECTION OUTPUT ;
    USE SIGNAL ;
    PORT
      LAYER M5 ;
        RECT  61.776 105.732 61.8 105.816 ;
    END
  END b[318]
  PIN b[319]
    DIRECTION OUTPUT ;
    USE SIGNAL ;
    PORT
      LAYER M5 ;
        RECT  61.872 105.732 61.896 105.816 ;
    END
  END b[319]
  PIN b[31]
    DIRECTION OUTPUT ;
    USE SIGNAL ;
    PORT
      LAYER M3 ;
        RECT  57.996 105.779 58.014 105.816 ;
    END
  END b[31]
  PIN b[320]
    DIRECTION OUTPUT ;
    USE SIGNAL ;
    PORT
      LAYER M5 ;
        RECT  61.968 105.732 61.992 105.816 ;
    END
  END b[320]
  PIN b[321]
    DIRECTION OUTPUT ;
    USE SIGNAL ;
    PORT
      LAYER M5 ;
        RECT  62.064 105.732 62.088 105.816 ;
    END
  END b[321]
  PIN b[322]
    DIRECTION OUTPUT ;
    USE SIGNAL ;
    PORT
      LAYER M5 ;
        RECT  62.16 105.732 62.184 105.816 ;
    END
  END b[322]
  PIN b[323]
    DIRECTION OUTPUT ;
    USE SIGNAL ;
    PORT
      LAYER M5 ;
        RECT  62.256 105.732 62.28 105.816 ;
    END
  END b[323]
  PIN b[324]
    DIRECTION OUTPUT ;
    USE SIGNAL ;
    PORT
      LAYER M5 ;
        RECT  62.352 105.732 62.376 105.816 ;
    END
  END b[324]
  PIN b[325]
    DIRECTION OUTPUT ;
    USE SIGNAL ;
    PORT
      LAYER M5 ;
        RECT  62.448 105.732 62.472 105.816 ;
    END
  END b[325]
  PIN b[326]
    DIRECTION OUTPUT ;
    USE SIGNAL ;
    PORT
      LAYER M5 ;
        RECT  62.544 105.732 62.568 105.816 ;
    END
  END b[326]
  PIN b[327]
    DIRECTION OUTPUT ;
    USE SIGNAL ;
    PORT
      LAYER M5 ;
        RECT  62.64 105.732 62.664 105.816 ;
    END
  END b[327]
  PIN b[328]
    DIRECTION OUTPUT ;
    USE SIGNAL ;
    PORT
      LAYER M5 ;
        RECT  62.736 105.732 62.76 105.816 ;
    END
  END b[328]
  PIN b[329]
    DIRECTION OUTPUT ;
    USE SIGNAL ;
    PORT
      LAYER M5 ;
        RECT  62.832 105.732 62.856 105.816 ;
    END
  END b[329]
  PIN b[32]
    DIRECTION OUTPUT ;
    USE SIGNAL ;
    PORT
      LAYER M3 ;
        RECT  58.068 105.779 58.086 105.816 ;
    END
  END b[32]
  PIN b[330]
    DIRECTION OUTPUT ;
    USE SIGNAL ;
    PORT
      LAYER M5 ;
        RECT  62.928 105.732 62.952 105.816 ;
    END
  END b[330]
  PIN b[331]
    DIRECTION OUTPUT ;
    USE SIGNAL ;
    PORT
      LAYER M5 ;
        RECT  63.024 105.732 63.048 105.816 ;
    END
  END b[331]
  PIN b[332]
    DIRECTION OUTPUT ;
    USE SIGNAL ;
    PORT
      LAYER M5 ;
        RECT  63.12 105.732 63.144 105.816 ;
    END
  END b[332]
  PIN b[333]
    DIRECTION OUTPUT ;
    USE SIGNAL ;
    PORT
      LAYER M5 ;
        RECT  63.216 105.732 63.24 105.816 ;
    END
  END b[333]
  PIN b[334]
    DIRECTION OUTPUT ;
    USE SIGNAL ;
    PORT
      LAYER M5 ;
        RECT  63.312 105.732 63.336 105.816 ;
    END
  END b[334]
  PIN b[335]
    DIRECTION OUTPUT ;
    USE SIGNAL ;
    PORT
      LAYER M5 ;
        RECT  63.408 105.732 63.432 105.816 ;
    END
  END b[335]
  PIN b[336]
    DIRECTION OUTPUT ;
    USE SIGNAL ;
    PORT
      LAYER M5 ;
        RECT  63.504 105.732 63.528 105.816 ;
    END
  END b[336]
  PIN b[337]
    DIRECTION OUTPUT ;
    USE SIGNAL ;
    PORT
      LAYER M5 ;
        RECT  63.6 105.732 63.624 105.816 ;
    END
  END b[337]
  PIN b[338]
    DIRECTION OUTPUT ;
    USE SIGNAL ;
    PORT
      LAYER M5 ;
        RECT  63.696 105.732 63.72 105.816 ;
    END
  END b[338]
  PIN b[339]
    DIRECTION OUTPUT ;
    USE SIGNAL ;
    PORT
      LAYER M5 ;
        RECT  63.792 105.732 63.816 105.816 ;
    END
  END b[339]
  PIN b[33]
    DIRECTION OUTPUT ;
    USE SIGNAL ;
    PORT
      LAYER M3 ;
        RECT  58.14 105.779 58.158 105.816 ;
    END
  END b[33]
  PIN b[340]
    DIRECTION OUTPUT ;
    USE SIGNAL ;
    PORT
      LAYER M5 ;
        RECT  63.888 105.732 63.912 105.816 ;
    END
  END b[340]
  PIN b[341]
    DIRECTION OUTPUT ;
    USE SIGNAL ;
    PORT
      LAYER M5 ;
        RECT  63.984 105.732 64.008 105.816 ;
    END
  END b[341]
  PIN b[342]
    DIRECTION OUTPUT ;
    USE SIGNAL ;
    PORT
      LAYER M5 ;
        RECT  64.08 105.732 64.104 105.816 ;
    END
  END b[342]
  PIN b[343]
    DIRECTION OUTPUT ;
    USE SIGNAL ;
    PORT
      LAYER M5 ;
        RECT  64.176 105.732 64.2 105.816 ;
    END
  END b[343]
  PIN b[344]
    DIRECTION OUTPUT ;
    USE SIGNAL ;
    PORT
      LAYER M5 ;
        RECT  64.272 105.732 64.296 105.816 ;
    END
  END b[344]
  PIN b[345]
    DIRECTION OUTPUT ;
    USE SIGNAL ;
    PORT
      LAYER M5 ;
        RECT  64.368 105.732 64.392 105.816 ;
    END
  END b[345]
  PIN b[346]
    DIRECTION OUTPUT ;
    USE SIGNAL ;
    PORT
      LAYER M5 ;
        RECT  64.464 105.732 64.488 105.816 ;
    END
  END b[346]
  PIN b[347]
    DIRECTION OUTPUT ;
    USE SIGNAL ;
    PORT
      LAYER M5 ;
        RECT  64.56 105.732 64.584 105.816 ;
    END
  END b[347]
  PIN b[348]
    DIRECTION OUTPUT ;
    USE SIGNAL ;
    PORT
      LAYER M5 ;
        RECT  64.656 105.732 64.68 105.816 ;
    END
  END b[348]
  PIN b[349]
    DIRECTION OUTPUT ;
    USE SIGNAL ;
    PORT
      LAYER M5 ;
        RECT  64.752 105.732 64.776 105.816 ;
    END
  END b[349]
  PIN b[34]
    DIRECTION OUTPUT ;
    USE SIGNAL ;
    PORT
      LAYER M3 ;
        RECT  58.212 105.779 58.23 105.816 ;
    END
  END b[34]
  PIN b[350]
    DIRECTION OUTPUT ;
    USE SIGNAL ;
    PORT
      LAYER M5 ;
        RECT  64.848 105.732 64.872 105.816 ;
    END
  END b[350]
  PIN b[351]
    DIRECTION OUTPUT ;
    USE SIGNAL ;
    PORT
      LAYER M5 ;
        RECT  64.944 105.732 64.968 105.816 ;
    END
  END b[351]
  PIN b[352]
    DIRECTION OUTPUT ;
    USE SIGNAL ;
    PORT
      LAYER M5 ;
        RECT  46.608 105.732 46.632 105.816 ;
    END
  END b[352]
  PIN b[353]
    DIRECTION OUTPUT ;
    USE SIGNAL ;
    PORT
      LAYER M5 ;
        RECT  46.704 105.732 46.728 105.816 ;
    END
  END b[353]
  PIN b[354]
    DIRECTION OUTPUT ;
    USE SIGNAL ;
    PORT
      LAYER M5 ;
        RECT  46.8 105.732 46.824 105.816 ;
    END
  END b[354]
  PIN b[355]
    DIRECTION OUTPUT ;
    USE SIGNAL ;
    PORT
      LAYER M5 ;
        RECT  46.896 105.732 46.92 105.816 ;
    END
  END b[355]
  PIN b[356]
    DIRECTION OUTPUT ;
    USE SIGNAL ;
    PORT
      LAYER M5 ;
        RECT  46.992 105.732 47.016 105.816 ;
    END
  END b[356]
  PIN b[357]
    DIRECTION OUTPUT ;
    USE SIGNAL ;
    PORT
      LAYER M5 ;
        RECT  47.088 105.732 47.112 105.816 ;
    END
  END b[357]
  PIN b[358]
    DIRECTION OUTPUT ;
    USE SIGNAL ;
    PORT
      LAYER M5 ;
        RECT  47.184 105.732 47.208 105.816 ;
    END
  END b[358]
  PIN b[359]
    DIRECTION OUTPUT ;
    USE SIGNAL ;
    PORT
      LAYER M5 ;
        RECT  47.28 105.732 47.304 105.816 ;
    END
  END b[359]
  PIN b[35]
    DIRECTION OUTPUT ;
    USE SIGNAL ;
    PORT
      LAYER M3 ;
        RECT  58.284 105.779 58.302 105.816 ;
    END
  END b[35]
  PIN b[360]
    DIRECTION OUTPUT ;
    USE SIGNAL ;
    PORT
      LAYER M5 ;
        RECT  47.376 105.732 47.4 105.816 ;
    END
  END b[360]
  PIN b[361]
    DIRECTION OUTPUT ;
    USE SIGNAL ;
    PORT
      LAYER M5 ;
        RECT  47.472 105.732 47.496 105.816 ;
    END
  END b[361]
  PIN b[362]
    DIRECTION OUTPUT ;
    USE SIGNAL ;
    PORT
      LAYER M5 ;
        RECT  47.568 105.732 47.592 105.816 ;
    END
  END b[362]
  PIN b[363]
    DIRECTION OUTPUT ;
    USE SIGNAL ;
    PORT
      LAYER M5 ;
        RECT  47.664 105.732 47.688 105.816 ;
    END
  END b[363]
  PIN b[364]
    DIRECTION OUTPUT ;
    USE SIGNAL ;
    PORT
      LAYER M5 ;
        RECT  47.76 105.732 47.784 105.816 ;
    END
  END b[364]
  PIN b[365]
    DIRECTION OUTPUT ;
    USE SIGNAL ;
    PORT
      LAYER M5 ;
        RECT  47.856 105.732 47.88 105.816 ;
    END
  END b[365]
  PIN b[366]
    DIRECTION OUTPUT ;
    USE SIGNAL ;
    PORT
      LAYER M5 ;
        RECT  47.952 105.732 47.976 105.816 ;
    END
  END b[366]
  PIN b[367]
    DIRECTION OUTPUT ;
    USE SIGNAL ;
    PORT
      LAYER M5 ;
        RECT  48.048 105.732 48.072 105.816 ;
    END
  END b[367]
  PIN b[368]
    DIRECTION OUTPUT ;
    USE SIGNAL ;
    PORT
      LAYER M5 ;
        RECT  48.144 105.732 48.168 105.816 ;
    END
  END b[368]
  PIN b[369]
    DIRECTION OUTPUT ;
    USE SIGNAL ;
    PORT
      LAYER M5 ;
        RECT  48.24 105.732 48.264 105.816 ;
    END
  END b[369]
  PIN b[36]
    DIRECTION OUTPUT ;
    USE SIGNAL ;
    PORT
      LAYER M3 ;
        RECT  58.356 105.779 58.374 105.816 ;
    END
  END b[36]
  PIN b[370]
    DIRECTION OUTPUT ;
    USE SIGNAL ;
    PORT
      LAYER M5 ;
        RECT  48.336 105.732 48.36 105.816 ;
    END
  END b[370]
  PIN b[371]
    DIRECTION OUTPUT ;
    USE SIGNAL ;
    PORT
      LAYER M5 ;
        RECT  48.432 105.732 48.456 105.816 ;
    END
  END b[371]
  PIN b[372]
    DIRECTION OUTPUT ;
    USE SIGNAL ;
    PORT
      LAYER M5 ;
        RECT  48.528 105.732 48.552 105.816 ;
    END
  END b[372]
  PIN b[373]
    DIRECTION OUTPUT ;
    USE SIGNAL ;
    PORT
      LAYER M5 ;
        RECT  48.624 105.732 48.648 105.816 ;
    END
  END b[373]
  PIN b[374]
    DIRECTION OUTPUT ;
    USE SIGNAL ;
    PORT
      LAYER M5 ;
        RECT  48.72 105.732 48.744 105.816 ;
    END
  END b[374]
  PIN b[375]
    DIRECTION OUTPUT ;
    USE SIGNAL ;
    PORT
      LAYER M5 ;
        RECT  48.816 105.732 48.84 105.816 ;
    END
  END b[375]
  PIN b[376]
    DIRECTION OUTPUT ;
    USE SIGNAL ;
    PORT
      LAYER M5 ;
        RECT  48.912 105.732 48.936 105.816 ;
    END
  END b[376]
  PIN b[377]
    DIRECTION OUTPUT ;
    USE SIGNAL ;
    PORT
      LAYER M5 ;
        RECT  49.008 105.732 49.032 105.816 ;
    END
  END b[377]
  PIN b[378]
    DIRECTION OUTPUT ;
    USE SIGNAL ;
    PORT
      LAYER M5 ;
        RECT  49.104 105.732 49.128 105.816 ;
    END
  END b[378]
  PIN b[379]
    DIRECTION OUTPUT ;
    USE SIGNAL ;
    PORT
      LAYER M5 ;
        RECT  49.2 105.732 49.224 105.816 ;
    END
  END b[379]
  PIN b[37]
    DIRECTION OUTPUT ;
    USE SIGNAL ;
    PORT
      LAYER M3 ;
        RECT  58.428 105.779 58.446 105.816 ;
    END
  END b[37]
  PIN b[380]
    DIRECTION OUTPUT ;
    USE SIGNAL ;
    PORT
      LAYER M5 ;
        RECT  49.296 105.732 49.32 105.816 ;
    END
  END b[380]
  PIN b[381]
    DIRECTION OUTPUT ;
    USE SIGNAL ;
    PORT
      LAYER M5 ;
        RECT  49.392 105.732 49.416 105.816 ;
    END
  END b[381]
  PIN b[382]
    DIRECTION OUTPUT ;
    USE SIGNAL ;
    PORT
      LAYER M5 ;
        RECT  49.488 105.732 49.512 105.816 ;
    END
  END b[382]
  PIN b[383]
    DIRECTION OUTPUT ;
    USE SIGNAL ;
    PORT
      LAYER M5 ;
        RECT  49.584 105.732 49.608 105.816 ;
    END
  END b[383]
  PIN b[384]
    DIRECTION OUTPUT ;
    USE SIGNAL ;
    PORT
      LAYER M3 ;
        RECT  41.364 105.779 41.382 105.816 ;
    END
  END b[384]
  PIN b[385]
    DIRECTION OUTPUT ;
    USE SIGNAL ;
    PORT
      LAYER M3 ;
        RECT  41.436 105.779 41.454 105.816 ;
    END
  END b[385]
  PIN b[386]
    DIRECTION OUTPUT ;
    USE SIGNAL ;
    PORT
      LAYER M3 ;
        RECT  41.508 105.779 41.526 105.816 ;
    END
  END b[386]
  PIN b[387]
    DIRECTION OUTPUT ;
    USE SIGNAL ;
    PORT
      LAYER M3 ;
        RECT  41.58 105.779 41.598 105.816 ;
    END
  END b[387]
  PIN b[388]
    DIRECTION OUTPUT ;
    USE SIGNAL ;
    PORT
      LAYER M3 ;
        RECT  41.652 105.779 41.67 105.816 ;
    END
  END b[388]
  PIN b[389]
    DIRECTION OUTPUT ;
    USE SIGNAL ;
    PORT
      LAYER M3 ;
        RECT  41.724 105.779 41.742 105.816 ;
    END
  END b[389]
  PIN b[38]
    DIRECTION OUTPUT ;
    USE SIGNAL ;
    PORT
      LAYER M3 ;
        RECT  58.5 105.779 58.518 105.816 ;
    END
  END b[38]
  PIN b[390]
    DIRECTION OUTPUT ;
    USE SIGNAL ;
    PORT
      LAYER M3 ;
        RECT  41.796 105.779 41.814 105.816 ;
    END
  END b[390]
  PIN b[391]
    DIRECTION OUTPUT ;
    USE SIGNAL ;
    PORT
      LAYER M3 ;
        RECT  41.868 105.779 41.886 105.816 ;
    END
  END b[391]
  PIN b[392]
    DIRECTION OUTPUT ;
    USE SIGNAL ;
    PORT
      LAYER M3 ;
        RECT  41.94 105.779 41.958 105.816 ;
    END
  END b[392]
  PIN b[393]
    DIRECTION OUTPUT ;
    USE SIGNAL ;
    PORT
      LAYER M3 ;
        RECT  42.012 105.779 42.03 105.816 ;
    END
  END b[393]
  PIN b[394]
    DIRECTION OUTPUT ;
    USE SIGNAL ;
    PORT
      LAYER M3 ;
        RECT  42.084 105.779 42.102 105.816 ;
    END
  END b[394]
  PIN b[395]
    DIRECTION OUTPUT ;
    USE SIGNAL ;
    PORT
      LAYER M3 ;
        RECT  42.156 105.779 42.174 105.816 ;
    END
  END b[395]
  PIN b[396]
    DIRECTION OUTPUT ;
    USE SIGNAL ;
    PORT
      LAYER M3 ;
        RECT  42.228 105.779 42.246 105.816 ;
    END
  END b[396]
  PIN b[397]
    DIRECTION OUTPUT ;
    USE SIGNAL ;
    PORT
      LAYER M3 ;
        RECT  42.3 105.779 42.318 105.816 ;
    END
  END b[397]
  PIN b[398]
    DIRECTION OUTPUT ;
    USE SIGNAL ;
    PORT
      LAYER M3 ;
        RECT  42.372 105.779 42.39 105.816 ;
    END
  END b[398]
  PIN b[399]
    DIRECTION OUTPUT ;
    USE SIGNAL ;
    PORT
      LAYER M3 ;
        RECT  42.444 105.779 42.462 105.816 ;
    END
  END b[399]
  PIN b[39]
    DIRECTION OUTPUT ;
    USE SIGNAL ;
    PORT
      LAYER M3 ;
        RECT  58.572 105.779 58.59 105.816 ;
    END
  END b[39]
  PIN b[3]
    DIRECTION OUTPUT ;
    USE SIGNAL ;
    PORT
      LAYER M3 ;
        RECT  55.98 105.779 55.998 105.816 ;
    END
  END b[3]
  PIN b[400]
    DIRECTION OUTPUT ;
    USE SIGNAL ;
    PORT
      LAYER M3 ;
        RECT  42.516 105.779 42.534 105.816 ;
    END
  END b[400]
  PIN b[401]
    DIRECTION OUTPUT ;
    USE SIGNAL ;
    PORT
      LAYER M3 ;
        RECT  42.588 105.779 42.606 105.816 ;
    END
  END b[401]
  PIN b[402]
    DIRECTION OUTPUT ;
    USE SIGNAL ;
    PORT
      LAYER M3 ;
        RECT  42.66 105.779 42.678 105.816 ;
    END
  END b[402]
  PIN b[403]
    DIRECTION OUTPUT ;
    USE SIGNAL ;
    PORT
      LAYER M3 ;
        RECT  42.732 105.779 42.75 105.816 ;
    END
  END b[403]
  PIN b[404]
    DIRECTION OUTPUT ;
    USE SIGNAL ;
    PORT
      LAYER M3 ;
        RECT  42.804 105.779 42.822 105.816 ;
    END
  END b[404]
  PIN b[405]
    DIRECTION OUTPUT ;
    USE SIGNAL ;
    PORT
      LAYER M3 ;
        RECT  42.876 105.779 42.894 105.816 ;
    END
  END b[405]
  PIN b[406]
    DIRECTION OUTPUT ;
    USE SIGNAL ;
    PORT
      LAYER M3 ;
        RECT  42.948 105.779 42.966 105.816 ;
    END
  END b[406]
  PIN b[407]
    DIRECTION OUTPUT ;
    USE SIGNAL ;
    PORT
      LAYER M3 ;
        RECT  43.02 105.779 43.038 105.816 ;
    END
  END b[407]
  PIN b[408]
    DIRECTION OUTPUT ;
    USE SIGNAL ;
    PORT
      LAYER M3 ;
        RECT  43.092 105.779 43.11 105.816 ;
    END
  END b[408]
  PIN b[409]
    DIRECTION OUTPUT ;
    USE SIGNAL ;
    PORT
      LAYER M3 ;
        RECT  43.164 105.779 43.182 105.816 ;
    END
  END b[409]
  PIN b[40]
    DIRECTION OUTPUT ;
    USE SIGNAL ;
    PORT
      LAYER M3 ;
        RECT  58.644 105.779 58.662 105.816 ;
    END
  END b[40]
  PIN b[410]
    DIRECTION OUTPUT ;
    USE SIGNAL ;
    PORT
      LAYER M3 ;
        RECT  43.236 105.779 43.254 105.816 ;
    END
  END b[410]
  PIN b[411]
    DIRECTION OUTPUT ;
    USE SIGNAL ;
    PORT
      LAYER M3 ;
        RECT  43.308 105.779 43.326 105.816 ;
    END
  END b[411]
  PIN b[412]
    DIRECTION OUTPUT ;
    USE SIGNAL ;
    PORT
      LAYER M3 ;
        RECT  43.38 105.779 43.398 105.816 ;
    END
  END b[412]
  PIN b[413]
    DIRECTION OUTPUT ;
    USE SIGNAL ;
    PORT
      LAYER M3 ;
        RECT  43.452 105.779 43.47 105.816 ;
    END
  END b[413]
  PIN b[414]
    DIRECTION OUTPUT ;
    USE SIGNAL ;
    PORT
      LAYER M3 ;
        RECT  43.524 105.779 43.542 105.816 ;
    END
  END b[414]
  PIN b[415]
    DIRECTION OUTPUT ;
    USE SIGNAL ;
    PORT
      LAYER M3 ;
        RECT  43.596 105.779 43.614 105.816 ;
    END
  END b[415]
  PIN b[416]
    DIRECTION OUTPUT ;
    USE SIGNAL ;
    PORT
      LAYER M3 ;
        RECT  36.756 105.779 36.774 105.816 ;
    END
  END b[416]
  PIN b[417]
    DIRECTION OUTPUT ;
    USE SIGNAL ;
    PORT
      LAYER M3 ;
        RECT  36.828 105.779 36.846 105.816 ;
    END
  END b[417]
  PIN b[418]
    DIRECTION OUTPUT ;
    USE SIGNAL ;
    PORT
      LAYER M3 ;
        RECT  36.9 105.779 36.918 105.816 ;
    END
  END b[418]
  PIN b[419]
    DIRECTION OUTPUT ;
    USE SIGNAL ;
    PORT
      LAYER M3 ;
        RECT  36.972 105.779 36.99 105.816 ;
    END
  END b[419]
  PIN b[41]
    DIRECTION OUTPUT ;
    USE SIGNAL ;
    PORT
      LAYER M3 ;
        RECT  58.716 105.779 58.734 105.816 ;
    END
  END b[41]
  PIN b[420]
    DIRECTION OUTPUT ;
    USE SIGNAL ;
    PORT
      LAYER M3 ;
        RECT  37.044 105.779 37.062 105.816 ;
    END
  END b[420]
  PIN b[421]
    DIRECTION OUTPUT ;
    USE SIGNAL ;
    PORT
      LAYER M3 ;
        RECT  37.116 105.779 37.134 105.816 ;
    END
  END b[421]
  PIN b[422]
    DIRECTION OUTPUT ;
    USE SIGNAL ;
    PORT
      LAYER M3 ;
        RECT  37.188 105.779 37.206 105.816 ;
    END
  END b[422]
  PIN b[423]
    DIRECTION OUTPUT ;
    USE SIGNAL ;
    PORT
      LAYER M3 ;
        RECT  37.26 105.779 37.278 105.816 ;
    END
  END b[423]
  PIN b[424]
    DIRECTION OUTPUT ;
    USE SIGNAL ;
    PORT
      LAYER M3 ;
        RECT  37.332 105.779 37.35 105.816 ;
    END
  END b[424]
  PIN b[425]
    DIRECTION OUTPUT ;
    USE SIGNAL ;
    PORT
      LAYER M3 ;
        RECT  37.404 105.779 37.422 105.816 ;
    END
  END b[425]
  PIN b[426]
    DIRECTION OUTPUT ;
    USE SIGNAL ;
    PORT
      LAYER M3 ;
        RECT  37.476 105.779 37.494 105.816 ;
    END
  END b[426]
  PIN b[427]
    DIRECTION OUTPUT ;
    USE SIGNAL ;
    PORT
      LAYER M3 ;
        RECT  37.548 105.779 37.566 105.816 ;
    END
  END b[427]
  PIN b[428]
    DIRECTION OUTPUT ;
    USE SIGNAL ;
    PORT
      LAYER M3 ;
        RECT  37.62 105.779 37.638 105.816 ;
    END
  END b[428]
  PIN b[429]
    DIRECTION OUTPUT ;
    USE SIGNAL ;
    PORT
      LAYER M3 ;
        RECT  37.692 105.779 37.71 105.816 ;
    END
  END b[429]
  PIN b[42]
    DIRECTION OUTPUT ;
    USE SIGNAL ;
    PORT
      LAYER M3 ;
        RECT  58.788 105.779 58.806 105.816 ;
    END
  END b[42]
  PIN b[430]
    DIRECTION OUTPUT ;
    USE SIGNAL ;
    PORT
      LAYER M3 ;
        RECT  37.764 105.779 37.782 105.816 ;
    END
  END b[430]
  PIN b[431]
    DIRECTION OUTPUT ;
    USE SIGNAL ;
    PORT
      LAYER M3 ;
        RECT  37.836 105.779 37.854 105.816 ;
    END
  END b[431]
  PIN b[432]
    DIRECTION OUTPUT ;
    USE SIGNAL ;
    PORT
      LAYER M3 ;
        RECT  37.908 105.779 37.926 105.816 ;
    END
  END b[432]
  PIN b[433]
    DIRECTION OUTPUT ;
    USE SIGNAL ;
    PORT
      LAYER M3 ;
        RECT  37.98 105.779 37.998 105.816 ;
    END
  END b[433]
  PIN b[434]
    DIRECTION OUTPUT ;
    USE SIGNAL ;
    PORT
      LAYER M3 ;
        RECT  38.052 105.779 38.07 105.816 ;
    END
  END b[434]
  PIN b[435]
    DIRECTION OUTPUT ;
    USE SIGNAL ;
    PORT
      LAYER M3 ;
        RECT  38.124 105.779 38.142 105.816 ;
    END
  END b[435]
  PIN b[436]
    DIRECTION OUTPUT ;
    USE SIGNAL ;
    PORT
      LAYER M3 ;
        RECT  38.196 105.779 38.214 105.816 ;
    END
  END b[436]
  PIN b[437]
    DIRECTION OUTPUT ;
    USE SIGNAL ;
    PORT
      LAYER M3 ;
        RECT  38.268 105.779 38.286 105.816 ;
    END
  END b[437]
  PIN b[438]
    DIRECTION OUTPUT ;
    USE SIGNAL ;
    PORT
      LAYER M3 ;
        RECT  38.34 105.779 38.358 105.816 ;
    END
  END b[438]
  PIN b[439]
    DIRECTION OUTPUT ;
    USE SIGNAL ;
    PORT
      LAYER M3 ;
        RECT  38.412 105.779 38.43 105.816 ;
    END
  END b[439]
  PIN b[43]
    DIRECTION OUTPUT ;
    USE SIGNAL ;
    PORT
      LAYER M3 ;
        RECT  58.86 105.779 58.878 105.816 ;
    END
  END b[43]
  PIN b[440]
    DIRECTION OUTPUT ;
    USE SIGNAL ;
    PORT
      LAYER M3 ;
        RECT  38.484 105.779 38.502 105.816 ;
    END
  END b[440]
  PIN b[441]
    DIRECTION OUTPUT ;
    USE SIGNAL ;
    PORT
      LAYER M3 ;
        RECT  38.556 105.779 38.574 105.816 ;
    END
  END b[441]
  PIN b[442]
    DIRECTION OUTPUT ;
    USE SIGNAL ;
    PORT
      LAYER M3 ;
        RECT  38.628 105.779 38.646 105.816 ;
    END
  END b[442]
  PIN b[443]
    DIRECTION OUTPUT ;
    USE SIGNAL ;
    PORT
      LAYER M3 ;
        RECT  38.7 105.779 38.718 105.816 ;
    END
  END b[443]
  PIN b[444]
    DIRECTION OUTPUT ;
    USE SIGNAL ;
    PORT
      LAYER M3 ;
        RECT  38.772 105.779 38.79 105.816 ;
    END
  END b[444]
  PIN b[445]
    DIRECTION OUTPUT ;
    USE SIGNAL ;
    PORT
      LAYER M3 ;
        RECT  38.844 105.779 38.862 105.816 ;
    END
  END b[445]
  PIN b[446]
    DIRECTION OUTPUT ;
    USE SIGNAL ;
    PORT
      LAYER M3 ;
        RECT  38.916 105.779 38.934 105.816 ;
    END
  END b[446]
  PIN b[447]
    DIRECTION OUTPUT ;
    USE SIGNAL ;
    PORT
      LAYER M3 ;
        RECT  38.988 105.779 39.006 105.816 ;
    END
  END b[447]
  PIN b[448]
    DIRECTION OUTPUT ;
    USE SIGNAL ;
    PORT
      LAYER M3 ;
        RECT  43.668 105.779 43.686 105.816 ;
    END
  END b[448]
  PIN b[449]
    DIRECTION OUTPUT ;
    USE SIGNAL ;
    PORT
      LAYER M3 ;
        RECT  43.74 105.779 43.758 105.816 ;
    END
  END b[449]
  PIN b[44]
    DIRECTION OUTPUT ;
    USE SIGNAL ;
    PORT
      LAYER M3 ;
        RECT  58.932 105.779 58.95 105.816 ;
    END
  END b[44]
  PIN b[450]
    DIRECTION OUTPUT ;
    USE SIGNAL ;
    PORT
      LAYER M3 ;
        RECT  43.812 105.779 43.83 105.816 ;
    END
  END b[450]
  PIN b[451]
    DIRECTION OUTPUT ;
    USE SIGNAL ;
    PORT
      LAYER M3 ;
        RECT  43.884 105.779 43.902 105.816 ;
    END
  END b[451]
  PIN b[452]
    DIRECTION OUTPUT ;
    USE SIGNAL ;
    PORT
      LAYER M3 ;
        RECT  43.956 105.779 43.974 105.816 ;
    END
  END b[452]
  PIN b[453]
    DIRECTION OUTPUT ;
    USE SIGNAL ;
    PORT
      LAYER M3 ;
        RECT  44.028 105.779 44.046 105.816 ;
    END
  END b[453]
  PIN b[454]
    DIRECTION OUTPUT ;
    USE SIGNAL ;
    PORT
      LAYER M3 ;
        RECT  44.1 105.779 44.118 105.816 ;
    END
  END b[454]
  PIN b[455]
    DIRECTION OUTPUT ;
    USE SIGNAL ;
    PORT
      LAYER M3 ;
        RECT  44.172 105.779 44.19 105.816 ;
    END
  END b[455]
  PIN b[456]
    DIRECTION OUTPUT ;
    USE SIGNAL ;
    PORT
      LAYER M3 ;
        RECT  44.244 105.779 44.262 105.816 ;
    END
  END b[456]
  PIN b[457]
    DIRECTION OUTPUT ;
    USE SIGNAL ;
    PORT
      LAYER M3 ;
        RECT  44.316 105.779 44.334 105.816 ;
    END
  END b[457]
  PIN b[458]
    DIRECTION OUTPUT ;
    USE SIGNAL ;
    PORT
      LAYER M3 ;
        RECT  44.388 105.779 44.406 105.816 ;
    END
  END b[458]
  PIN b[459]
    DIRECTION OUTPUT ;
    USE SIGNAL ;
    PORT
      LAYER M3 ;
        RECT  44.46 105.779 44.478 105.816 ;
    END
  END b[459]
  PIN b[45]
    DIRECTION OUTPUT ;
    USE SIGNAL ;
    PORT
      LAYER M3 ;
        RECT  59.004 105.779 59.022 105.816 ;
    END
  END b[45]
  PIN b[460]
    DIRECTION OUTPUT ;
    USE SIGNAL ;
    PORT
      LAYER M3 ;
        RECT  44.532 105.779 44.55 105.816 ;
    END
  END b[460]
  PIN b[461]
    DIRECTION OUTPUT ;
    USE SIGNAL ;
    PORT
      LAYER M3 ;
        RECT  44.604 105.779 44.622 105.816 ;
    END
  END b[461]
  PIN b[462]
    DIRECTION OUTPUT ;
    USE SIGNAL ;
    PORT
      LAYER M3 ;
        RECT  44.676 105.779 44.694 105.816 ;
    END
  END b[462]
  PIN b[463]
    DIRECTION OUTPUT ;
    USE SIGNAL ;
    PORT
      LAYER M3 ;
        RECT  44.748 105.779 44.766 105.816 ;
    END
  END b[463]
  PIN b[464]
    DIRECTION OUTPUT ;
    USE SIGNAL ;
    PORT
      LAYER M3 ;
        RECT  44.82 105.779 44.838 105.816 ;
    END
  END b[464]
  PIN b[465]
    DIRECTION OUTPUT ;
    USE SIGNAL ;
    PORT
      LAYER M3 ;
        RECT  44.892 105.779 44.91 105.816 ;
    END
  END b[465]
  PIN b[466]
    DIRECTION OUTPUT ;
    USE SIGNAL ;
    PORT
      LAYER M3 ;
        RECT  44.964 105.779 44.982 105.816 ;
    END
  END b[466]
  PIN b[467]
    DIRECTION OUTPUT ;
    USE SIGNAL ;
    PORT
      LAYER M3 ;
        RECT  45.036 105.779 45.054 105.816 ;
    END
  END b[467]
  PIN b[468]
    DIRECTION OUTPUT ;
    USE SIGNAL ;
    PORT
      LAYER M3 ;
        RECT  45.108 105.779 45.126 105.816 ;
    END
  END b[468]
  PIN b[469]
    DIRECTION OUTPUT ;
    USE SIGNAL ;
    PORT
      LAYER M3 ;
        RECT  45.18 105.779 45.198 105.816 ;
    END
  END b[469]
  PIN b[46]
    DIRECTION OUTPUT ;
    USE SIGNAL ;
    PORT
      LAYER M3 ;
        RECT  59.076 105.779 59.094 105.816 ;
    END
  END b[46]
  PIN b[470]
    DIRECTION OUTPUT ;
    USE SIGNAL ;
    PORT
      LAYER M3 ;
        RECT  45.252 105.779 45.27 105.816 ;
    END
  END b[470]
  PIN b[471]
    DIRECTION OUTPUT ;
    USE SIGNAL ;
    PORT
      LAYER M3 ;
        RECT  45.324 105.779 45.342 105.816 ;
    END
  END b[471]
  PIN b[472]
    DIRECTION OUTPUT ;
    USE SIGNAL ;
    PORT
      LAYER M3 ;
        RECT  45.396 105.779 45.414 105.816 ;
    END
  END b[472]
  PIN b[473]
    DIRECTION OUTPUT ;
    USE SIGNAL ;
    PORT
      LAYER M3 ;
        RECT  45.468 105.779 45.486 105.816 ;
    END
  END b[473]
  PIN b[474]
    DIRECTION OUTPUT ;
    USE SIGNAL ;
    PORT
      LAYER M3 ;
        RECT  45.54 105.779 45.558 105.816 ;
    END
  END b[474]
  PIN b[475]
    DIRECTION OUTPUT ;
    USE SIGNAL ;
    PORT
      LAYER M3 ;
        RECT  45.612 105.779 45.63 105.816 ;
    END
  END b[475]
  PIN b[476]
    DIRECTION OUTPUT ;
    USE SIGNAL ;
    PORT
      LAYER M3 ;
        RECT  45.684 105.779 45.702 105.816 ;
    END
  END b[476]
  PIN b[477]
    DIRECTION OUTPUT ;
    USE SIGNAL ;
    PORT
      LAYER M3 ;
        RECT  45.756 105.779 45.774 105.816 ;
    END
  END b[477]
  PIN b[478]
    DIRECTION OUTPUT ;
    USE SIGNAL ;
    PORT
      LAYER M3 ;
        RECT  45.828 105.779 45.846 105.816 ;
    END
  END b[478]
  PIN b[479]
    DIRECTION OUTPUT ;
    USE SIGNAL ;
    PORT
      LAYER M3 ;
        RECT  45.9 105.779 45.918 105.816 ;
    END
  END b[479]
  PIN b[47]
    DIRECTION OUTPUT ;
    USE SIGNAL ;
    PORT
      LAYER M3 ;
        RECT  59.148 105.779 59.166 105.816 ;
    END
  END b[47]
  PIN b[480]
    DIRECTION OUTPUT ;
    USE SIGNAL ;
    PORT
      LAYER M3 ;
        RECT  39.06 105.779 39.078 105.816 ;
    END
  END b[480]
  PIN b[481]
    DIRECTION OUTPUT ;
    USE SIGNAL ;
    PORT
      LAYER M3 ;
        RECT  39.132 105.779 39.15 105.816 ;
    END
  END b[481]
  PIN b[482]
    DIRECTION OUTPUT ;
    USE SIGNAL ;
    PORT
      LAYER M3 ;
        RECT  39.204 105.779 39.222 105.816 ;
    END
  END b[482]
  PIN b[483]
    DIRECTION OUTPUT ;
    USE SIGNAL ;
    PORT
      LAYER M3 ;
        RECT  39.276 105.779 39.294 105.816 ;
    END
  END b[483]
  PIN b[484]
    DIRECTION OUTPUT ;
    USE SIGNAL ;
    PORT
      LAYER M3 ;
        RECT  39.348 105.779 39.366 105.816 ;
    END
  END b[484]
  PIN b[485]
    DIRECTION OUTPUT ;
    USE SIGNAL ;
    PORT
      LAYER M3 ;
        RECT  39.42 105.779 39.438 105.816 ;
    END
  END b[485]
  PIN b[486]
    DIRECTION OUTPUT ;
    USE SIGNAL ;
    PORT
      LAYER M3 ;
        RECT  39.492 105.779 39.51 105.816 ;
    END
  END b[486]
  PIN b[487]
    DIRECTION OUTPUT ;
    USE SIGNAL ;
    PORT
      LAYER M3 ;
        RECT  39.564 105.779 39.582 105.816 ;
    END
  END b[487]
  PIN b[488]
    DIRECTION OUTPUT ;
    USE SIGNAL ;
    PORT
      LAYER M3 ;
        RECT  39.636 105.779 39.654 105.816 ;
    END
  END b[488]
  PIN b[489]
    DIRECTION OUTPUT ;
    USE SIGNAL ;
    PORT
      LAYER M3 ;
        RECT  39.708 105.779 39.726 105.816 ;
    END
  END b[489]
  PIN b[48]
    DIRECTION OUTPUT ;
    USE SIGNAL ;
    PORT
      LAYER M3 ;
        RECT  59.22 105.779 59.238 105.816 ;
    END
  END b[48]
  PIN b[490]
    DIRECTION OUTPUT ;
    USE SIGNAL ;
    PORT
      LAYER M3 ;
        RECT  39.78 105.779 39.798 105.816 ;
    END
  END b[490]
  PIN b[491]
    DIRECTION OUTPUT ;
    USE SIGNAL ;
    PORT
      LAYER M3 ;
        RECT  39.852 105.779 39.87 105.816 ;
    END
  END b[491]
  PIN b[492]
    DIRECTION OUTPUT ;
    USE SIGNAL ;
    PORT
      LAYER M3 ;
        RECT  39.924 105.779 39.942 105.816 ;
    END
  END b[492]
  PIN b[493]
    DIRECTION OUTPUT ;
    USE SIGNAL ;
    PORT
      LAYER M3 ;
        RECT  39.996 105.779 40.014 105.816 ;
    END
  END b[493]
  PIN b[494]
    DIRECTION OUTPUT ;
    USE SIGNAL ;
    PORT
      LAYER M3 ;
        RECT  40.068 105.779 40.086 105.816 ;
    END
  END b[494]
  PIN b[495]
    DIRECTION OUTPUT ;
    USE SIGNAL ;
    PORT
      LAYER M3 ;
        RECT  40.14 105.779 40.158 105.816 ;
    END
  END b[495]
  PIN b[496]
    DIRECTION OUTPUT ;
    USE SIGNAL ;
    PORT
      LAYER M3 ;
        RECT  40.212 105.779 40.23 105.816 ;
    END
  END b[496]
  PIN b[497]
    DIRECTION OUTPUT ;
    USE SIGNAL ;
    PORT
      LAYER M3 ;
        RECT  40.284 105.779 40.302 105.816 ;
    END
  END b[497]
  PIN b[498]
    DIRECTION OUTPUT ;
    USE SIGNAL ;
    PORT
      LAYER M3 ;
        RECT  40.356 105.779 40.374 105.816 ;
    END
  END b[498]
  PIN b[499]
    DIRECTION OUTPUT ;
    USE SIGNAL ;
    PORT
      LAYER M3 ;
        RECT  40.428 105.779 40.446 105.816 ;
    END
  END b[499]
  PIN b[49]
    DIRECTION OUTPUT ;
    USE SIGNAL ;
    PORT
      LAYER M3 ;
        RECT  59.292 105.779 59.31 105.816 ;
    END
  END b[49]
  PIN b[4]
    DIRECTION OUTPUT ;
    USE SIGNAL ;
    PORT
      LAYER M3 ;
        RECT  56.052 105.779 56.07 105.816 ;
    END
  END b[4]
  PIN b[500]
    DIRECTION OUTPUT ;
    USE SIGNAL ;
    PORT
      LAYER M3 ;
        RECT  40.5 105.779 40.518 105.816 ;
    END
  END b[500]
  PIN b[501]
    DIRECTION OUTPUT ;
    USE SIGNAL ;
    PORT
      LAYER M3 ;
        RECT  40.572 105.779 40.59 105.816 ;
    END
  END b[501]
  PIN b[502]
    DIRECTION OUTPUT ;
    USE SIGNAL ;
    PORT
      LAYER M3 ;
        RECT  40.644 105.779 40.662 105.816 ;
    END
  END b[502]
  PIN b[503]
    DIRECTION OUTPUT ;
    USE SIGNAL ;
    PORT
      LAYER M3 ;
        RECT  40.716 105.779 40.734 105.816 ;
    END
  END b[503]
  PIN b[504]
    DIRECTION OUTPUT ;
    USE SIGNAL ;
    PORT
      LAYER M3 ;
        RECT  40.788 105.779 40.806 105.816 ;
    END
  END b[504]
  PIN b[505]
    DIRECTION OUTPUT ;
    USE SIGNAL ;
    PORT
      LAYER M3 ;
        RECT  40.86 105.779 40.878 105.816 ;
    END
  END b[505]
  PIN b[506]
    DIRECTION OUTPUT ;
    USE SIGNAL ;
    PORT
      LAYER M3 ;
        RECT  40.932 105.779 40.95 105.816 ;
    END
  END b[506]
  PIN b[507]
    DIRECTION OUTPUT ;
    USE SIGNAL ;
    PORT
      LAYER M3 ;
        RECT  41.004 105.779 41.022 105.816 ;
    END
  END b[507]
  PIN b[508]
    DIRECTION OUTPUT ;
    USE SIGNAL ;
    PORT
      LAYER M3 ;
        RECT  41.076 105.779 41.094 105.816 ;
    END
  END b[508]
  PIN b[509]
    DIRECTION OUTPUT ;
    USE SIGNAL ;
    PORT
      LAYER M3 ;
        RECT  41.148 105.779 41.166 105.816 ;
    END
  END b[509]
  PIN b[50]
    DIRECTION OUTPUT ;
    USE SIGNAL ;
    PORT
      LAYER M3 ;
        RECT  59.364 105.779 59.382 105.816 ;
    END
  END b[50]
  PIN b[510]
    DIRECTION OUTPUT ;
    USE SIGNAL ;
    PORT
      LAYER M3 ;
        RECT  41.22 105.779 41.238 105.816 ;
    END
  END b[510]
  PIN b[511]
    DIRECTION OUTPUT ;
    USE SIGNAL ;
    PORT
      LAYER M3 ;
        RECT  41.292 105.779 41.31 105.816 ;
    END
  END b[511]
  PIN b[512]
    DIRECTION OUTPUT ;
    USE SIGNAL ;
    PORT
      LAYER M3 ;
        RECT  60.948 105.779 60.966 105.816 ;
    END
  END b[512]
  PIN b[513]
    DIRECTION OUTPUT ;
    USE SIGNAL ;
    PORT
      LAYER M3 ;
        RECT  61.02 105.779 61.038 105.816 ;
    END
  END b[513]
  PIN b[514]
    DIRECTION OUTPUT ;
    USE SIGNAL ;
    PORT
      LAYER M3 ;
        RECT  61.092 105.779 61.11 105.816 ;
    END
  END b[514]
  PIN b[515]
    DIRECTION OUTPUT ;
    USE SIGNAL ;
    PORT
      LAYER M3 ;
        RECT  61.164 105.779 61.182 105.816 ;
    END
  END b[515]
  PIN b[516]
    DIRECTION OUTPUT ;
    USE SIGNAL ;
    PORT
      LAYER M3 ;
        RECT  61.236 105.779 61.254 105.816 ;
    END
  END b[516]
  PIN b[517]
    DIRECTION OUTPUT ;
    USE SIGNAL ;
    PORT
      LAYER M3 ;
        RECT  61.308 105.779 61.326 105.816 ;
    END
  END b[517]
  PIN b[518]
    DIRECTION OUTPUT ;
    USE SIGNAL ;
    PORT
      LAYER M3 ;
        RECT  61.38 105.779 61.398 105.816 ;
    END
  END b[518]
  PIN b[519]
    DIRECTION OUTPUT ;
    USE SIGNAL ;
    PORT
      LAYER M3 ;
        RECT  61.452 105.779 61.47 105.816 ;
    END
  END b[519]
  PIN b[51]
    DIRECTION OUTPUT ;
    USE SIGNAL ;
    PORT
      LAYER M3 ;
        RECT  59.436 105.779 59.454 105.816 ;
    END
  END b[51]
  PIN b[520]
    DIRECTION OUTPUT ;
    USE SIGNAL ;
    PORT
      LAYER M3 ;
        RECT  61.524 105.779 61.542 105.816 ;
    END
  END b[520]
  PIN b[521]
    DIRECTION OUTPUT ;
    USE SIGNAL ;
    PORT
      LAYER M3 ;
        RECT  61.596 105.779 61.614 105.816 ;
    END
  END b[521]
  PIN b[522]
    DIRECTION OUTPUT ;
    USE SIGNAL ;
    PORT
      LAYER M3 ;
        RECT  61.668 105.779 61.686 105.816 ;
    END
  END b[522]
  PIN b[523]
    DIRECTION OUTPUT ;
    USE SIGNAL ;
    PORT
      LAYER M3 ;
        RECT  61.74 105.779 61.758 105.816 ;
    END
  END b[523]
  PIN b[524]
    DIRECTION OUTPUT ;
    USE SIGNAL ;
    PORT
      LAYER M3 ;
        RECT  61.812 105.779 61.83 105.816 ;
    END
  END b[524]
  PIN b[525]
    DIRECTION OUTPUT ;
    USE SIGNAL ;
    PORT
      LAYER M3 ;
        RECT  61.884 105.779 61.902 105.816 ;
    END
  END b[525]
  PIN b[526]
    DIRECTION OUTPUT ;
    USE SIGNAL ;
    PORT
      LAYER M3 ;
        RECT  61.956 105.779 61.974 105.816 ;
    END
  END b[526]
  PIN b[527]
    DIRECTION OUTPUT ;
    USE SIGNAL ;
    PORT
      LAYER M3 ;
        RECT  62.028 105.779 62.046 105.816 ;
    END
  END b[527]
  PIN b[528]
    DIRECTION OUTPUT ;
    USE SIGNAL ;
    PORT
      LAYER M3 ;
        RECT  62.1 105.779 62.118 105.816 ;
    END
  END b[528]
  PIN b[529]
    DIRECTION OUTPUT ;
    USE SIGNAL ;
    PORT
      LAYER M3 ;
        RECT  62.172 105.779 62.19 105.816 ;
    END
  END b[529]
  PIN b[52]
    DIRECTION OUTPUT ;
    USE SIGNAL ;
    PORT
      LAYER M3 ;
        RECT  59.508 105.779 59.526 105.816 ;
    END
  END b[52]
  PIN b[530]
    DIRECTION OUTPUT ;
    USE SIGNAL ;
    PORT
      LAYER M3 ;
        RECT  62.244 105.779 62.262 105.816 ;
    END
  END b[530]
  PIN b[531]
    DIRECTION OUTPUT ;
    USE SIGNAL ;
    PORT
      LAYER M3 ;
        RECT  62.316 105.779 62.334 105.816 ;
    END
  END b[531]
  PIN b[532]
    DIRECTION OUTPUT ;
    USE SIGNAL ;
    PORT
      LAYER M3 ;
        RECT  62.388 105.779 62.406 105.816 ;
    END
  END b[532]
  PIN b[533]
    DIRECTION OUTPUT ;
    USE SIGNAL ;
    PORT
      LAYER M3 ;
        RECT  62.46 105.779 62.478 105.816 ;
    END
  END b[533]
  PIN b[534]
    DIRECTION OUTPUT ;
    USE SIGNAL ;
    PORT
      LAYER M3 ;
        RECT  62.532 105.779 62.55 105.816 ;
    END
  END b[534]
  PIN b[535]
    DIRECTION OUTPUT ;
    USE SIGNAL ;
    PORT
      LAYER M3 ;
        RECT  62.604 105.779 62.622 105.816 ;
    END
  END b[535]
  PIN b[536]
    DIRECTION OUTPUT ;
    USE SIGNAL ;
    PORT
      LAYER M3 ;
        RECT  62.676 105.779 62.694 105.816 ;
    END
  END b[536]
  PIN b[537]
    DIRECTION OUTPUT ;
    USE SIGNAL ;
    PORT
      LAYER M3 ;
        RECT  62.748 105.779 62.766 105.816 ;
    END
  END b[537]
  PIN b[538]
    DIRECTION OUTPUT ;
    USE SIGNAL ;
    PORT
      LAYER M3 ;
        RECT  62.82 105.779 62.838 105.816 ;
    END
  END b[538]
  PIN b[539]
    DIRECTION OUTPUT ;
    USE SIGNAL ;
    PORT
      LAYER M3 ;
        RECT  62.892 105.779 62.91 105.816 ;
    END
  END b[539]
  PIN b[53]
    DIRECTION OUTPUT ;
    USE SIGNAL ;
    PORT
      LAYER M3 ;
        RECT  59.58 105.779 59.598 105.816 ;
    END
  END b[53]
  PIN b[540]
    DIRECTION OUTPUT ;
    USE SIGNAL ;
    PORT
      LAYER M3 ;
        RECT  62.964 105.779 62.982 105.816 ;
    END
  END b[540]
  PIN b[541]
    DIRECTION OUTPUT ;
    USE SIGNAL ;
    PORT
      LAYER M3 ;
        RECT  63.036 105.779 63.054 105.816 ;
    END
  END b[541]
  PIN b[542]
    DIRECTION OUTPUT ;
    USE SIGNAL ;
    PORT
      LAYER M3 ;
        RECT  63.108 105.779 63.126 105.816 ;
    END
  END b[542]
  PIN b[543]
    DIRECTION OUTPUT ;
    USE SIGNAL ;
    PORT
      LAYER M3 ;
        RECT  63.18 105.779 63.198 105.816 ;
    END
  END b[543]
  PIN b[544]
    DIRECTION OUTPUT ;
    USE SIGNAL ;
    PORT
      LAYER M3 ;
        RECT  63.252 105.779 63.27 105.816 ;
    END
  END b[544]
  PIN b[545]
    DIRECTION OUTPUT ;
    USE SIGNAL ;
    PORT
      LAYER M3 ;
        RECT  63.324 105.779 63.342 105.816 ;
    END
  END b[545]
  PIN b[546]
    DIRECTION OUTPUT ;
    USE SIGNAL ;
    PORT
      LAYER M3 ;
        RECT  63.396 105.779 63.414 105.816 ;
    END
  END b[546]
  PIN b[547]
    DIRECTION OUTPUT ;
    USE SIGNAL ;
    PORT
      LAYER M3 ;
        RECT  63.468 105.779 63.486 105.816 ;
    END
  END b[547]
  PIN b[548]
    DIRECTION OUTPUT ;
    USE SIGNAL ;
    PORT
      LAYER M3 ;
        RECT  63.54 105.779 63.558 105.816 ;
    END
  END b[548]
  PIN b[549]
    DIRECTION OUTPUT ;
    USE SIGNAL ;
    PORT
      LAYER M3 ;
        RECT  63.612 105.779 63.63 105.816 ;
    END
  END b[549]
  PIN b[54]
    DIRECTION OUTPUT ;
    USE SIGNAL ;
    PORT
      LAYER M3 ;
        RECT  59.652 105.779 59.67 105.816 ;
    END
  END b[54]
  PIN b[550]
    DIRECTION OUTPUT ;
    USE SIGNAL ;
    PORT
      LAYER M3 ;
        RECT  63.684 105.779 63.702 105.816 ;
    END
  END b[550]
  PIN b[551]
    DIRECTION OUTPUT ;
    USE SIGNAL ;
    PORT
      LAYER M3 ;
        RECT  63.756 105.779 63.774 105.816 ;
    END
  END b[551]
  PIN b[552]
    DIRECTION OUTPUT ;
    USE SIGNAL ;
    PORT
      LAYER M3 ;
        RECT  63.828 105.779 63.846 105.816 ;
    END
  END b[552]
  PIN b[553]
    DIRECTION OUTPUT ;
    USE SIGNAL ;
    PORT
      LAYER M3 ;
        RECT  63.9 105.779 63.918 105.816 ;
    END
  END b[553]
  PIN b[554]
    DIRECTION OUTPUT ;
    USE SIGNAL ;
    PORT
      LAYER M3 ;
        RECT  63.972 105.779 63.99 105.816 ;
    END
  END b[554]
  PIN b[555]
    DIRECTION OUTPUT ;
    USE SIGNAL ;
    PORT
      LAYER M3 ;
        RECT  64.044 105.779 64.062 105.816 ;
    END
  END b[555]
  PIN b[556]
    DIRECTION OUTPUT ;
    USE SIGNAL ;
    PORT
      LAYER M3 ;
        RECT  64.116 105.779 64.134 105.816 ;
    END
  END b[556]
  PIN b[557]
    DIRECTION OUTPUT ;
    USE SIGNAL ;
    PORT
      LAYER M3 ;
        RECT  64.188 105.779 64.206 105.816 ;
    END
  END b[557]
  PIN b[558]
    DIRECTION OUTPUT ;
    USE SIGNAL ;
    PORT
      LAYER M3 ;
        RECT  64.26 105.779 64.278 105.816 ;
    END
  END b[558]
  PIN b[559]
    DIRECTION OUTPUT ;
    USE SIGNAL ;
    PORT
      LAYER M3 ;
        RECT  64.332 105.779 64.35 105.816 ;
    END
  END b[559]
  PIN b[55]
    DIRECTION OUTPUT ;
    USE SIGNAL ;
    PORT
      LAYER M3 ;
        RECT  59.724 105.779 59.742 105.816 ;
    END
  END b[55]
  PIN b[560]
    DIRECTION OUTPUT ;
    USE SIGNAL ;
    PORT
      LAYER M3 ;
        RECT  64.404 105.779 64.422 105.816 ;
    END
  END b[560]
  PIN b[561]
    DIRECTION OUTPUT ;
    USE SIGNAL ;
    PORT
      LAYER M3 ;
        RECT  64.476 105.779 64.494 105.816 ;
    END
  END b[561]
  PIN b[562]
    DIRECTION OUTPUT ;
    USE SIGNAL ;
    PORT
      LAYER M3 ;
        RECT  64.548 105.779 64.566 105.816 ;
    END
  END b[562]
  PIN b[563]
    DIRECTION OUTPUT ;
    USE SIGNAL ;
    PORT
      LAYER M3 ;
        RECT  64.62 105.779 64.638 105.816 ;
    END
  END b[563]
  PIN b[564]
    DIRECTION OUTPUT ;
    USE SIGNAL ;
    PORT
      LAYER M3 ;
        RECT  64.692 105.779 64.71 105.816 ;
    END
  END b[564]
  PIN b[565]
    DIRECTION OUTPUT ;
    USE SIGNAL ;
    PORT
      LAYER M3 ;
        RECT  64.764 105.779 64.782 105.816 ;
    END
  END b[565]
  PIN b[566]
    DIRECTION OUTPUT ;
    USE SIGNAL ;
    PORT
      LAYER M3 ;
        RECT  64.836 105.779 64.854 105.816 ;
    END
  END b[566]
  PIN b[567]
    DIRECTION OUTPUT ;
    USE SIGNAL ;
    PORT
      LAYER M3 ;
        RECT  64.908 105.779 64.926 105.816 ;
    END
  END b[567]
  PIN b[568]
    DIRECTION OUTPUT ;
    USE SIGNAL ;
    PORT
      LAYER M3 ;
        RECT  64.98 105.779 64.998 105.816 ;
    END
  END b[568]
  PIN b[569]
    DIRECTION OUTPUT ;
    USE SIGNAL ;
    PORT
      LAYER M3 ;
        RECT  65.052 105.779 65.07 105.816 ;
    END
  END b[569]
  PIN b[56]
    DIRECTION OUTPUT ;
    USE SIGNAL ;
    PORT
      LAYER M3 ;
        RECT  59.796 105.779 59.814 105.816 ;
    END
  END b[56]
  PIN b[570]
    DIRECTION OUTPUT ;
    USE SIGNAL ;
    PORT
      LAYER M3 ;
        RECT  65.124 105.779 65.142 105.816 ;
    END
  END b[570]
  PIN b[571]
    DIRECTION OUTPUT ;
    USE SIGNAL ;
    PORT
      LAYER M3 ;
        RECT  65.196 105.779 65.214 105.816 ;
    END
  END b[571]
  PIN b[572]
    DIRECTION OUTPUT ;
    USE SIGNAL ;
    PORT
      LAYER M3 ;
        RECT  65.268 105.779 65.286 105.816 ;
    END
  END b[572]
  PIN b[573]
    DIRECTION OUTPUT ;
    USE SIGNAL ;
    PORT
      LAYER M3 ;
        RECT  65.34 105.779 65.358 105.816 ;
    END
  END b[573]
  PIN b[574]
    DIRECTION OUTPUT ;
    USE SIGNAL ;
    PORT
      LAYER M3 ;
        RECT  65.412 105.779 65.43 105.816 ;
    END
  END b[574]
  PIN b[575]
    DIRECTION OUTPUT ;
    USE SIGNAL ;
    PORT
      LAYER M3 ;
        RECT  65.484 105.779 65.502 105.816 ;
    END
  END b[575]
  PIN b[576]
    DIRECTION OUTPUT ;
    USE SIGNAL ;
    PORT
      LAYER M3 ;
        RECT  34.956 105.779 34.974 105.816 ;
    END
  END b[576]
  PIN b[577]
    DIRECTION OUTPUT ;
    USE SIGNAL ;
    PORT
      LAYER M3 ;
        RECT  35.028 105.779 35.046 105.816 ;
    END
  END b[577]
  PIN b[578]
    DIRECTION OUTPUT ;
    USE SIGNAL ;
    PORT
      LAYER M3 ;
        RECT  35.1 105.779 35.118 105.816 ;
    END
  END b[578]
  PIN b[579]
    DIRECTION OUTPUT ;
    USE SIGNAL ;
    PORT
      LAYER M3 ;
        RECT  35.172 105.779 35.19 105.816 ;
    END
  END b[579]
  PIN b[57]
    DIRECTION OUTPUT ;
    USE SIGNAL ;
    PORT
      LAYER M3 ;
        RECT  59.868 105.779 59.886 105.816 ;
    END
  END b[57]
  PIN b[580]
    DIRECTION OUTPUT ;
    USE SIGNAL ;
    PORT
      LAYER M3 ;
        RECT  35.244 105.779 35.262 105.816 ;
    END
  END b[580]
  PIN b[581]
    DIRECTION OUTPUT ;
    USE SIGNAL ;
    PORT
      LAYER M3 ;
        RECT  35.316 105.779 35.334 105.816 ;
    END
  END b[581]
  PIN b[582]
    DIRECTION OUTPUT ;
    USE SIGNAL ;
    PORT
      LAYER M3 ;
        RECT  35.388 105.779 35.406 105.816 ;
    END
  END b[582]
  PIN b[583]
    DIRECTION OUTPUT ;
    USE SIGNAL ;
    PORT
      LAYER M3 ;
        RECT  35.46 105.779 35.478 105.816 ;
    END
  END b[583]
  PIN b[584]
    DIRECTION OUTPUT ;
    USE SIGNAL ;
    PORT
      LAYER M3 ;
        RECT  35.532 105.779 35.55 105.816 ;
    END
  END b[584]
  PIN b[585]
    DIRECTION OUTPUT ;
    USE SIGNAL ;
    PORT
      LAYER M3 ;
        RECT  35.604 105.779 35.622 105.816 ;
    END
  END b[585]
  PIN b[586]
    DIRECTION OUTPUT ;
    USE SIGNAL ;
    PORT
      LAYER M3 ;
        RECT  35.676 105.779 35.694 105.816 ;
    END
  END b[586]
  PIN b[587]
    DIRECTION OUTPUT ;
    USE SIGNAL ;
    PORT
      LAYER M3 ;
        RECT  35.748 105.779 35.766 105.816 ;
    END
  END b[587]
  PIN b[588]
    DIRECTION OUTPUT ;
    USE SIGNAL ;
    PORT
      LAYER M3 ;
        RECT  35.82 105.779 35.838 105.816 ;
    END
  END b[588]
  PIN b[589]
    DIRECTION OUTPUT ;
    USE SIGNAL ;
    PORT
      LAYER M3 ;
        RECT  35.892 105.779 35.91 105.816 ;
    END
  END b[589]
  PIN b[58]
    DIRECTION OUTPUT ;
    USE SIGNAL ;
    PORT
      LAYER M3 ;
        RECT  59.94 105.779 59.958 105.816 ;
    END
  END b[58]
  PIN b[590]
    DIRECTION OUTPUT ;
    USE SIGNAL ;
    PORT
      LAYER M3 ;
        RECT  35.964 105.779 35.982 105.816 ;
    END
  END b[590]
  PIN b[591]
    DIRECTION OUTPUT ;
    USE SIGNAL ;
    PORT
      LAYER M3 ;
        RECT  36.036 105.779 36.054 105.816 ;
    END
  END b[591]
  PIN b[592]
    DIRECTION OUTPUT ;
    USE SIGNAL ;
    PORT
      LAYER M3 ;
        RECT  36.108 105.779 36.126 105.816 ;
    END
  END b[592]
  PIN b[593]
    DIRECTION OUTPUT ;
    USE SIGNAL ;
    PORT
      LAYER M3 ;
        RECT  36.18 105.779 36.198 105.816 ;
    END
  END b[593]
  PIN b[594]
    DIRECTION OUTPUT ;
    USE SIGNAL ;
    PORT
      LAYER M3 ;
        RECT  36.252 105.779 36.27 105.816 ;
    END
  END b[594]
  PIN b[595]
    DIRECTION OUTPUT ;
    USE SIGNAL ;
    PORT
      LAYER M3 ;
        RECT  36.324 105.779 36.342 105.816 ;
    END
  END b[595]
  PIN b[596]
    DIRECTION OUTPUT ;
    USE SIGNAL ;
    PORT
      LAYER M3 ;
        RECT  36.396 105.779 36.414 105.816 ;
    END
  END b[596]
  PIN b[597]
    DIRECTION OUTPUT ;
    USE SIGNAL ;
    PORT
      LAYER M3 ;
        RECT  36.468 105.779 36.486 105.816 ;
    END
  END b[597]
  PIN b[598]
    DIRECTION OUTPUT ;
    USE SIGNAL ;
    PORT
      LAYER M3 ;
        RECT  36.54 105.779 36.558 105.816 ;
    END
  END b[598]
  PIN b[599]
    DIRECTION OUTPUT ;
    USE SIGNAL ;
    PORT
      LAYER M3 ;
        RECT  36.612 105.779 36.63 105.816 ;
    END
  END b[599]
  PIN b[59]
    DIRECTION OUTPUT ;
    USE SIGNAL ;
    PORT
      LAYER M3 ;
        RECT  60.012 105.779 60.03 105.816 ;
    END
  END b[59]
  PIN b[5]
    DIRECTION OUTPUT ;
    USE SIGNAL ;
    PORT
      LAYER M3 ;
        RECT  56.124 105.779 56.142 105.816 ;
    END
  END b[5]
  PIN b[60]
    DIRECTION OUTPUT ;
    USE SIGNAL ;
    PORT
      LAYER M3 ;
        RECT  60.084 105.779 60.102 105.816 ;
    END
  END b[60]
  PIN b[61]
    DIRECTION OUTPUT ;
    USE SIGNAL ;
    PORT
      LAYER M3 ;
        RECT  60.156 105.779 60.174 105.816 ;
    END
  END b[61]
  PIN b[62]
    DIRECTION OUTPUT ;
    USE SIGNAL ;
    PORT
      LAYER M3 ;
        RECT  60.228 105.779 60.246 105.816 ;
    END
  END b[62]
  PIN b[63]
    DIRECTION OUTPUT ;
    USE SIGNAL ;
    PORT
      LAYER M3 ;
        RECT  60.3 105.779 60.318 105.816 ;
    END
  END b[63]
  PIN b[64]
    DIRECTION OUTPUT ;
    USE SIGNAL ;
    PORT
      LAYER M3 ;
        RECT  46.548 105.779 46.566 105.816 ;
    END
  END b[64]
  PIN b[65]
    DIRECTION OUTPUT ;
    USE SIGNAL ;
    PORT
      LAYER M3 ;
        RECT  46.62 105.779 46.638 105.816 ;
    END
  END b[65]
  PIN b[66]
    DIRECTION OUTPUT ;
    USE SIGNAL ;
    PORT
      LAYER M3 ;
        RECT  46.692 105.779 46.71 105.816 ;
    END
  END b[66]
  PIN b[67]
    DIRECTION OUTPUT ;
    USE SIGNAL ;
    PORT
      LAYER M3 ;
        RECT  46.764 105.779 46.782 105.816 ;
    END
  END b[67]
  PIN b[68]
    DIRECTION OUTPUT ;
    USE SIGNAL ;
    PORT
      LAYER M3 ;
        RECT  46.836 105.779 46.854 105.816 ;
    END
  END b[68]
  PIN b[69]
    DIRECTION OUTPUT ;
    USE SIGNAL ;
    PORT
      LAYER M3 ;
        RECT  46.908 105.779 46.926 105.816 ;
    END
  END b[69]
  PIN b[6]
    DIRECTION OUTPUT ;
    USE SIGNAL ;
    PORT
      LAYER M3 ;
        RECT  56.196 105.779 56.214 105.816 ;
    END
  END b[6]
  PIN b[70]
    DIRECTION OUTPUT ;
    USE SIGNAL ;
    PORT
      LAYER M3 ;
        RECT  46.98 105.779 46.998 105.816 ;
    END
  END b[70]
  PIN b[71]
    DIRECTION OUTPUT ;
    USE SIGNAL ;
    PORT
      LAYER M3 ;
        RECT  47.052 105.779 47.07 105.816 ;
    END
  END b[71]
  PIN b[72]
    DIRECTION OUTPUT ;
    USE SIGNAL ;
    PORT
      LAYER M3 ;
        RECT  47.124 105.779 47.142 105.816 ;
    END
  END b[72]
  PIN b[73]
    DIRECTION OUTPUT ;
    USE SIGNAL ;
    PORT
      LAYER M3 ;
        RECT  47.196 105.779 47.214 105.816 ;
    END
  END b[73]
  PIN b[74]
    DIRECTION OUTPUT ;
    USE SIGNAL ;
    PORT
      LAYER M3 ;
        RECT  47.268 105.779 47.286 105.816 ;
    END
  END b[74]
  PIN b[75]
    DIRECTION OUTPUT ;
    USE SIGNAL ;
    PORT
      LAYER M3 ;
        RECT  47.34 105.779 47.358 105.816 ;
    END
  END b[75]
  PIN b[76]
    DIRECTION OUTPUT ;
    USE SIGNAL ;
    PORT
      LAYER M3 ;
        RECT  47.412 105.779 47.43 105.816 ;
    END
  END b[76]
  PIN b[77]
    DIRECTION OUTPUT ;
    USE SIGNAL ;
    PORT
      LAYER M3 ;
        RECT  47.484 105.779 47.502 105.816 ;
    END
  END b[77]
  PIN b[78]
    DIRECTION OUTPUT ;
    USE SIGNAL ;
    PORT
      LAYER M3 ;
        RECT  47.556 105.779 47.574 105.816 ;
    END
  END b[78]
  PIN b[79]
    DIRECTION OUTPUT ;
    USE SIGNAL ;
    PORT
      LAYER M3 ;
        RECT  47.628 105.779 47.646 105.816 ;
    END
  END b[79]
  PIN b[7]
    DIRECTION OUTPUT ;
    USE SIGNAL ;
    PORT
      LAYER M3 ;
        RECT  56.268 105.779 56.286 105.816 ;
    END
  END b[7]
  PIN b[80]
    DIRECTION OUTPUT ;
    USE SIGNAL ;
    PORT
      LAYER M3 ;
        RECT  47.7 105.779 47.718 105.816 ;
    END
  END b[80]
  PIN b[81]
    DIRECTION OUTPUT ;
    USE SIGNAL ;
    PORT
      LAYER M3 ;
        RECT  47.772 105.779 47.79 105.816 ;
    END
  END b[81]
  PIN b[82]
    DIRECTION OUTPUT ;
    USE SIGNAL ;
    PORT
      LAYER M3 ;
        RECT  47.844 105.779 47.862 105.816 ;
    END
  END b[82]
  PIN b[83]
    DIRECTION OUTPUT ;
    USE SIGNAL ;
    PORT
      LAYER M3 ;
        RECT  47.916 105.779 47.934 105.816 ;
    END
  END b[83]
  PIN b[84]
    DIRECTION OUTPUT ;
    USE SIGNAL ;
    PORT
      LAYER M3 ;
        RECT  47.988 105.779 48.006 105.816 ;
    END
  END b[84]
  PIN b[85]
    DIRECTION OUTPUT ;
    USE SIGNAL ;
    PORT
      LAYER M3 ;
        RECT  48.06 105.779 48.078 105.816 ;
    END
  END b[85]
  PIN b[86]
    DIRECTION OUTPUT ;
    USE SIGNAL ;
    PORT
      LAYER M3 ;
        RECT  48.132 105.779 48.15 105.816 ;
    END
  END b[86]
  PIN b[87]
    DIRECTION OUTPUT ;
    USE SIGNAL ;
    PORT
      LAYER M3 ;
        RECT  48.204 105.779 48.222 105.816 ;
    END
  END b[87]
  PIN b[88]
    DIRECTION OUTPUT ;
    USE SIGNAL ;
    PORT
      LAYER M3 ;
        RECT  48.276 105.779 48.294 105.816 ;
    END
  END b[88]
  PIN b[89]
    DIRECTION OUTPUT ;
    USE SIGNAL ;
    PORT
      LAYER M3 ;
        RECT  48.348 105.779 48.366 105.816 ;
    END
  END b[89]
  PIN b[8]
    DIRECTION OUTPUT ;
    USE SIGNAL ;
    PORT
      LAYER M3 ;
        RECT  56.34 105.779 56.358 105.816 ;
    END
  END b[8]
  PIN b[90]
    DIRECTION OUTPUT ;
    USE SIGNAL ;
    PORT
      LAYER M3 ;
        RECT  48.42 105.779 48.438 105.816 ;
    END
  END b[90]
  PIN b[91]
    DIRECTION OUTPUT ;
    USE SIGNAL ;
    PORT
      LAYER M3 ;
        RECT  48.492 105.779 48.51 105.816 ;
    END
  END b[91]
  PIN b[92]
    DIRECTION OUTPUT ;
    USE SIGNAL ;
    PORT
      LAYER M3 ;
        RECT  48.564 105.779 48.582 105.816 ;
    END
  END b[92]
  PIN b[93]
    DIRECTION OUTPUT ;
    USE SIGNAL ;
    PORT
      LAYER M3 ;
        RECT  48.636 105.779 48.654 105.816 ;
    END
  END b[93]
  PIN b[94]
    DIRECTION OUTPUT ;
    USE SIGNAL ;
    PORT
      LAYER M3 ;
        RECT  48.708 105.779 48.726 105.816 ;
    END
  END b[94]
  PIN b[95]
    DIRECTION OUTPUT ;
    USE SIGNAL ;
    PORT
      LAYER M3 ;
        RECT  48.78 105.779 48.798 105.816 ;
    END
  END b[95]
  PIN b[96]
    DIRECTION OUTPUT ;
    USE SIGNAL ;
    PORT
      LAYER M3 ;
        RECT  51.156 105.779 51.174 105.816 ;
    END
  END b[96]
  PIN b[97]
    DIRECTION OUTPUT ;
    USE SIGNAL ;
    PORT
      LAYER M3 ;
        RECT  51.228 105.779 51.246 105.816 ;
    END
  END b[97]
  PIN b[98]
    DIRECTION OUTPUT ;
    USE SIGNAL ;
    PORT
      LAYER M3 ;
        RECT  51.3 105.779 51.318 105.816 ;
    END
  END b[98]
  PIN b[99]
    DIRECTION OUTPUT ;
    USE SIGNAL ;
    PORT
      LAYER M3 ;
        RECT  51.372 105.779 51.39 105.816 ;
    END
  END b[99]
  PIN b[9]
    DIRECTION OUTPUT ;
    USE SIGNAL ;
    PORT
      LAYER M3 ;
        RECT  56.412 105.779 56.43 105.816 ;
    END
  END b[9]
  PIN ck_o
    DIRECTION OUTPUT ;
    USE SIGNAL ;
    PORT
      LAYER M4 ;
        RECT  0 52.752 0.084 52.776 ;
    END
  END ck_o
  PIN ckf
    DIRECTION INPUT ;
    USE SIGNAL ;
    PORT
      LAYER M4 ;
        RECT  0 52.848 0.084 52.872 ;
    END
  END ckf
  PIN ea
    DIRECTION INPUT ;
    USE SIGNAL ;
    PORT
      LAYER M4 ;
        RECT  104.004 79.824 104.088 79.848 ;
    END
  END ea
  PIN eb
    DIRECTION OUTPUT ;
    USE SIGNAL ;
    PORT
      LAYER M3 ;
        RECT  36.684 105.779 36.702 105.816 ;
    END
  END eb
  PIN VDD
    DIRECTION INOUT ;
    USE POWER ;
    PORT
      LAYER M5 ;
        RECT  99.792 2.151 99.912 103.433 ;
        RECT  97.092 2.151 97.212 103.433 ;
        RECT  94.392 2.151 94.512 103.433 ;
        RECT  91.692 2.151 91.812 103.433 ;
        RECT  88.992 2.151 89.112 103.433 ;
        RECT  86.292 2.151 86.412 103.433 ;
        RECT  83.592 2.151 83.712 103.433 ;
        RECT  80.892 2.151 81.012 103.433 ;
        RECT  78.192 2.151 78.312 103.433 ;
        RECT  75.492 2.151 75.612 103.433 ;
        RECT  72.792 2.151 72.912 103.433 ;
        RECT  70.092 2.151 70.212 103.433 ;
        RECT  67.392 2.151 67.512 103.433 ;
        RECT  64.692 2.151 64.812 103.433 ;
        RECT  61.992 2.151 62.112 103.433 ;
        RECT  59.292 2.151 59.412 103.433 ;
        RECT  56.592 2.151 56.712 103.433 ;
        RECT  53.892 2.151 54.012 103.433 ;
        RECT  51.192 2.151 51.312 103.433 ;
        RECT  48.492 2.151 48.612 103.433 ;
        RECT  45.792 2.151 45.912 103.433 ;
        RECT  43.092 2.151 43.212 103.433 ;
        RECT  40.392 2.151 40.512 103.433 ;
        RECT  37.692 2.151 37.812 103.433 ;
        RECT  34.992 2.151 35.112 103.433 ;
        RECT  32.292 2.151 32.412 103.433 ;
        RECT  29.592 2.151 29.712 103.433 ;
        RECT  26.892 2.151 27.012 103.433 ;
        RECT  24.192 2.151 24.312 103.433 ;
        RECT  21.492 2.151 21.612 103.433 ;
        RECT  18.792 2.151 18.912 103.433 ;
        RECT  16.092 2.151 16.212 103.433 ;
        RECT  13.392 2.151 13.512 103.433 ;
        RECT  10.692 2.151 10.812 103.433 ;
        RECT  7.992 2.151 8.112 103.433 ;
        RECT  5.292 2.151 5.412 103.433 ;
        RECT  2.592 2.151 2.712 103.433 ;
    END
  END VDD
  PIN VSS
    DIRECTION INOUT ;
    USE GROUND ;
    PORT
      LAYER M5 ;
        RECT  99.6 2.137 99.72 103.419 ;
        RECT  96.9 2.137 97.02 103.419 ;
        RECT  94.2 2.137 94.32 103.419 ;
        RECT  91.5 2.137 91.62 103.419 ;
        RECT  88.8 2.137 88.92 103.419 ;
        RECT  86.1 2.137 86.22 103.419 ;
        RECT  83.4 2.137 83.52 103.419 ;
        RECT  80.7 2.137 80.82 103.419 ;
        RECT  78 2.137 78.12 103.419 ;
        RECT  75.3 2.137 75.42 103.419 ;
        RECT  72.6 2.137 72.72 103.419 ;
        RECT  69.9 2.137 70.02 103.419 ;
        RECT  67.2 2.137 67.32 103.419 ;
        RECT  64.5 2.137 64.62 103.419 ;
        RECT  61.8 2.137 61.92 103.419 ;
        RECT  59.1 2.137 59.22 103.419 ;
        RECT  56.4 2.137 56.52 103.419 ;
        RECT  53.7 2.137 53.82 103.419 ;
        RECT  51 2.137 51.12 103.419 ;
        RECT  48.3 2.137 48.42 103.419 ;
        RECT  45.6 2.137 45.72 103.419 ;
        RECT  42.9 2.137 43.02 103.419 ;
        RECT  40.2 2.137 40.32 103.419 ;
        RECT  37.5 2.137 37.62 103.419 ;
        RECT  34.8 2.137 34.92 103.419 ;
        RECT  32.1 2.137 32.22 103.419 ;
        RECT  29.4 2.137 29.52 103.419 ;
        RECT  26.7 2.137 26.82 103.419 ;
        RECT  24 2.137 24.12 103.419 ;
        RECT  21.3 2.137 21.42 103.419 ;
        RECT  18.6 2.137 18.72 103.419 ;
        RECT  15.9 2.137 16.02 103.419 ;
        RECT  13.2 2.137 13.32 103.419 ;
        RECT  10.5 2.137 10.62 103.419 ;
        RECT  7.8 2.137 7.92 103.419 ;
        RECT  5.1 2.137 5.22 103.419 ;
        RECT  2.4 2.137 2.52 103.419 ;
    END
  END VSS
  OBS
    LAYER RVTN ;
     RECT  2.16 2.16 101.898 2.295 ;
     RECT  2.16 2.565 101.898 2.835 ;
     RECT  2.16 3.105 101.898 3.375 ;
     RECT  2.16 3.645 101.898 3.915 ;
     RECT  2.16 4.185 101.898 4.455 ;
     RECT  2.16 4.725 101.898 4.995 ;
     RECT  2.16 5.265 101.898 5.535 ;
     RECT  2.16 5.805 101.898 6.075 ;
     RECT  2.16 6.345 101.898 6.615 ;
     RECT  2.16 6.885 101.898 7.155 ;
     RECT  2.16 7.425 101.898 7.695 ;
     RECT  2.16 7.965 101.898 8.235 ;
     RECT  2.16 8.505 101.898 8.775 ;
     RECT  2.16 9.045 101.898 9.315 ;
     RECT  2.16 9.585 101.898 9.855 ;
     RECT  2.16 10.125 101.898 10.395 ;
     RECT  2.16 10.665 101.898 10.935 ;
     RECT  2.16 11.205 101.898 11.475 ;
     RECT  2.16 11.745 101.898 12.015 ;
     RECT  2.16 12.285 101.898 12.555 ;
     RECT  2.16 12.825 101.898 13.095 ;
     RECT  2.16 13.365 101.898 13.635 ;
     RECT  2.16 13.905 101.898 14.175 ;
     RECT  2.16 14.445 101.898 14.715 ;
     RECT  2.16 14.985 101.898 15.255 ;
     RECT  2.16 15.525 101.898 15.795 ;
     RECT  2.16 16.065 101.898 16.335 ;
     RECT  2.16 16.605 101.898 16.875 ;
     RECT  2.16 17.145 101.898 17.415 ;
     RECT  2.16 17.685 101.898 17.955 ;
     RECT  2.16 18.225 101.898 18.495 ;
     RECT  2.16 18.765 101.898 19.035 ;
     RECT  2.16 19.305 101.898 19.575 ;
     RECT  2.16 19.845 101.898 20.115 ;
     RECT  2.16 20.385 101.898 20.655 ;
     RECT  2.16 20.925 101.898 21.195 ;
     RECT  2.16 21.465 101.898 21.735 ;
     RECT  2.16 22.005 101.898 22.275 ;
     RECT  2.16 22.545 101.898 22.815 ;
     RECT  2.16 23.085 101.898 23.355 ;
     RECT  2.16 23.625 101.898 23.895 ;
     RECT  2.16 24.165 101.898 24.435 ;
     RECT  2.16 24.705 101.898 24.975 ;
     RECT  2.16 25.245 101.898 25.515 ;
     RECT  2.16 25.785 101.898 26.055 ;
     RECT  2.16 26.325 101.898 26.595 ;
     RECT  2.16 26.865 101.898 27.135 ;
     RECT  2.16 27.405 101.898 27.675 ;
     RECT  2.16 27.945 101.898 28.215 ;
     RECT  2.16 28.485 101.898 28.755 ;
     RECT  2.16 29.025 101.898 29.295 ;
     RECT  2.16 29.565 101.898 29.835 ;
     RECT  2.16 30.105 101.898 30.375 ;
     RECT  2.16 30.645 101.898 30.915 ;
     RECT  2.16 31.185 101.898 31.455 ;
     RECT  2.16 31.725 101.898 31.995 ;
     RECT  2.16 32.265 101.898 32.535 ;
     RECT  2.16 32.805 101.898 33.075 ;
     RECT  2.16 33.345 101.898 33.615 ;
     RECT  2.16 33.885 101.898 34.155 ;
     RECT  2.16 34.425 101.898 34.695 ;
     RECT  2.16 34.965 101.898 35.235 ;
     RECT  2.16 35.505 101.898 35.775 ;
     RECT  2.16 36.045 101.898 36.315 ;
     RECT  2.16 36.585 101.898 36.855 ;
     RECT  2.16 37.125 101.898 37.395 ;
     RECT  2.16 37.665 101.898 37.935 ;
     RECT  2.16 38.205 101.898 38.475 ;
     RECT  2.16 38.745 101.898 39.015 ;
     RECT  2.16 39.285 101.898 39.555 ;
     RECT  2.16 39.825 101.898 40.095 ;
     RECT  2.16 40.365 101.898 40.635 ;
     RECT  2.16 40.905 101.898 41.175 ;
     RECT  2.16 41.445 101.898 41.715 ;
     RECT  2.16 41.985 101.898 42.255 ;
     RECT  2.16 42.525 101.898 42.795 ;
     RECT  2.16 43.065 101.898 43.335 ;
     RECT  2.16 43.605 101.898 43.875 ;
     RECT  2.16 44.145 101.898 44.415 ;
     RECT  2.16 44.685 101.898 44.955 ;
     RECT  2.16 45.225 101.898 45.495 ;
     RECT  2.16 45.765 101.898 46.035 ;
     RECT  2.16 46.305 101.898 46.575 ;
     RECT  2.16 46.845 101.898 47.115 ;
     RECT  2.16 47.385 101.898 47.655 ;
     RECT  2.16 47.925 101.898 48.195 ;
     RECT  2.16 48.465 101.898 48.735 ;
     RECT  2.16 49.005 101.898 49.275 ;
     RECT  2.16 49.545 101.898 49.815 ;
     RECT  2.16 50.085 101.898 50.355 ;
     RECT  2.16 50.625 101.898 50.895 ;
     RECT  2.16 51.165 101.898 51.435 ;
     RECT  2.16 51.705 101.898 51.975 ;
     RECT  2.16 52.245 101.898 52.515 ;
     RECT  2.16 52.785 101.898 53.055 ;
     RECT  2.16 53.325 101.898 53.595 ;
     RECT  2.16 53.865 101.898 54.135 ;
     RECT  2.16 54.405 101.898 54.675 ;
     RECT  2.16 54.945 101.898 55.215 ;
     RECT  2.16 55.485 101.898 55.755 ;
     RECT  2.16 56.025 101.898 56.295 ;
     RECT  2.16 56.565 101.898 56.835 ;
     RECT  2.16 57.105 101.898 57.375 ;
     RECT  2.16 57.645 101.898 57.915 ;
     RECT  2.16 58.185 101.898 58.455 ;
     RECT  2.16 58.725 101.898 58.995 ;
     RECT  2.16 59.265 101.898 59.535 ;
     RECT  2.16 59.805 101.898 60.075 ;
     RECT  2.16 60.345 101.898 60.615 ;
     RECT  2.16 60.885 101.898 61.155 ;
     RECT  2.16 61.425 101.898 61.695 ;
     RECT  2.16 61.965 101.898 62.235 ;
     RECT  2.16 62.505 101.898 62.775 ;
     RECT  2.16 63.045 101.898 63.315 ;
     RECT  2.16 63.585 101.898 63.855 ;
     RECT  2.16 64.125 101.898 64.395 ;
     RECT  2.16 64.665 101.898 64.935 ;
     RECT  2.16 65.205 101.898 65.475 ;
     RECT  2.16 65.745 101.898 66.015 ;
     RECT  2.16 66.285 101.898 66.555 ;
     RECT  2.16 66.825 101.898 67.095 ;
     RECT  2.16 67.365 101.898 67.635 ;
     RECT  2.16 67.905 101.898 68.175 ;
     RECT  2.16 68.445 101.898 68.715 ;
     RECT  2.16 68.985 101.898 69.255 ;
     RECT  2.16 69.525 101.898 69.795 ;
     RECT  2.16 70.065 101.898 70.335 ;
     RECT  2.16 70.605 101.898 70.875 ;
     RECT  2.16 71.145 101.898 71.415 ;
     RECT  2.16 71.685 101.898 71.955 ;
     RECT  2.16 72.225 101.898 72.495 ;
     RECT  2.16 72.765 101.898 73.035 ;
     RECT  2.16 73.305 101.898 73.575 ;
     RECT  2.16 73.845 101.898 74.115 ;
     RECT  2.16 74.385 101.898 74.655 ;
     RECT  2.16 74.925 101.898 75.195 ;
     RECT  2.16 75.465 101.898 75.735 ;
     RECT  2.16 76.005 101.898 76.275 ;
     RECT  2.16 76.545 101.898 76.815 ;
     RECT  2.16 77.085 101.898 77.355 ;
     RECT  2.16 77.625 101.898 77.895 ;
     RECT  2.16 78.165 101.898 78.435 ;
     RECT  2.16 78.705 101.898 78.975 ;
     RECT  2.16 79.245 101.898 79.515 ;
     RECT  2.16 79.785 101.898 80.055 ;
     RECT  2.16 80.325 101.898 80.595 ;
     RECT  2.16 80.865 101.898 81.135 ;
     RECT  2.16 81.405 101.898 81.675 ;
     RECT  2.16 81.945 101.898 82.215 ;
     RECT  2.16 82.485 101.898 82.755 ;
     RECT  2.16 83.025 101.898 83.295 ;
     RECT  2.16 83.565 101.898 83.835 ;
     RECT  2.16 84.105 101.898 84.375 ;
     RECT  2.16 84.645 101.898 84.915 ;
     RECT  2.16 85.185 101.898 85.455 ;
     RECT  2.16 85.725 101.898 85.995 ;
     RECT  2.16 86.265 101.898 86.535 ;
     RECT  2.16 86.805 101.898 87.075 ;
     RECT  2.16 87.345 101.898 87.615 ;
     RECT  2.16 87.885 101.898 88.155 ;
     RECT  2.16 88.425 101.898 88.695 ;
     RECT  2.16 88.965 101.898 89.235 ;
     RECT  2.16 89.505 101.898 89.775 ;
     RECT  2.16 90.045 101.898 90.315 ;
     RECT  2.16 90.585 101.898 90.855 ;
     RECT  2.16 91.125 101.898 91.395 ;
     RECT  2.16 91.665 101.898 91.935 ;
     RECT  2.16 92.205 101.898 92.475 ;
     RECT  2.16 92.745 101.898 93.015 ;
     RECT  2.16 93.285 101.898 93.555 ;
     RECT  2.16 93.825 101.898 94.095 ;
     RECT  2.16 94.365 101.898 94.635 ;
     RECT  2.16 94.905 101.898 95.175 ;
     RECT  2.16 95.445 101.898 95.715 ;
     RECT  2.16 95.985 101.898 96.255 ;
     RECT  2.16 96.525 101.898 96.795 ;
     RECT  2.16 97.065 101.898 97.335 ;
     RECT  2.16 97.605 101.898 97.875 ;
     RECT  2.16 98.145 101.898 98.415 ;
     RECT  2.16 98.685 101.898 98.955 ;
     RECT  2.16 99.225 101.898 99.495 ;
     RECT  2.16 99.765 101.898 100.035 ;
     RECT  2.16 100.305 101.898 100.575 ;
     RECT  2.16 100.845 101.898 101.115 ;
     RECT  2.16 101.385 101.898 101.655 ;
     RECT  2.16 101.925 101.898 102.195 ;
     RECT  2.16 102.465 101.898 102.735 ;
     RECT  2.16 103.005 101.898 103.275 ;
    LAYER RVTP ;
     RECT  2.16 2.295 101.898 2.565 ;
     RECT  2.16 2.835 101.898 3.105 ;
     RECT  2.16 3.375 101.898 3.645 ;
     RECT  2.16 3.915 101.898 4.185 ;
     RECT  2.16 4.455 101.898 4.725 ;
     RECT  2.16 4.995 101.898 5.265 ;
     RECT  2.16 5.535 101.898 5.805 ;
     RECT  2.16 6.075 101.898 6.345 ;
     RECT  2.16 6.615 101.898 6.885 ;
     RECT  2.16 7.155 101.898 7.425 ;
     RECT  2.16 7.695 101.898 7.965 ;
     RECT  2.16 8.235 101.898 8.505 ;
     RECT  2.16 8.775 101.898 9.045 ;
     RECT  2.16 9.315 101.898 9.585 ;
     RECT  2.16 9.855 101.898 10.125 ;
     RECT  2.16 10.395 101.898 10.665 ;
     RECT  2.16 10.935 101.898 11.205 ;
     RECT  2.16 11.475 101.898 11.745 ;
     RECT  2.16 12.015 101.898 12.285 ;
     RECT  2.16 12.555 101.898 12.825 ;
     RECT  2.16 13.095 101.898 13.365 ;
     RECT  2.16 13.635 101.898 13.905 ;
     RECT  2.16 14.175 101.898 14.445 ;
     RECT  2.16 14.715 101.898 14.985 ;
     RECT  2.16 15.255 101.898 15.525 ;
     RECT  2.16 15.795 101.898 16.065 ;
     RECT  2.16 16.335 101.898 16.605 ;
     RECT  2.16 16.875 101.898 17.145 ;
     RECT  2.16 17.415 101.898 17.685 ;
     RECT  2.16 17.955 101.898 18.225 ;
     RECT  2.16 18.495 101.898 18.765 ;
     RECT  2.16 19.035 101.898 19.305 ;
     RECT  2.16 19.575 101.898 19.845 ;
     RECT  2.16 20.115 101.898 20.385 ;
     RECT  2.16 20.655 101.898 20.925 ;
     RECT  2.16 21.195 101.898 21.465 ;
     RECT  2.16 21.735 101.898 22.005 ;
     RECT  2.16 22.275 101.898 22.545 ;
     RECT  2.16 22.815 101.898 23.085 ;
     RECT  2.16 23.355 101.898 23.625 ;
     RECT  2.16 23.895 101.898 24.165 ;
     RECT  2.16 24.435 101.898 24.705 ;
     RECT  2.16 24.975 101.898 25.245 ;
     RECT  2.16 25.515 101.898 25.785 ;
     RECT  2.16 26.055 101.898 26.325 ;
     RECT  2.16 26.595 101.898 26.865 ;
     RECT  2.16 27.135 101.898 27.405 ;
     RECT  2.16 27.675 101.898 27.945 ;
     RECT  2.16 28.215 101.898 28.485 ;
     RECT  2.16 28.755 101.898 29.025 ;
     RECT  2.16 29.295 101.898 29.565 ;
     RECT  2.16 29.835 101.898 30.105 ;
     RECT  2.16 30.375 101.898 30.645 ;
     RECT  2.16 30.915 101.898 31.185 ;
     RECT  2.16 31.455 101.898 31.725 ;
     RECT  2.16 31.995 101.898 32.265 ;
     RECT  2.16 32.535 101.898 32.805 ;
     RECT  2.16 33.075 101.898 33.345 ;
     RECT  2.16 33.615 101.898 33.885 ;
     RECT  2.16 34.155 101.898 34.425 ;
     RECT  2.16 34.695 101.898 34.965 ;
     RECT  2.16 35.235 101.898 35.505 ;
     RECT  2.16 35.775 101.898 36.045 ;
     RECT  2.16 36.315 101.898 36.585 ;
     RECT  2.16 36.855 101.898 37.125 ;
     RECT  2.16 37.395 101.898 37.665 ;
     RECT  2.16 37.935 101.898 38.205 ;
     RECT  2.16 38.475 101.898 38.745 ;
     RECT  2.16 39.015 101.898 39.285 ;
     RECT  2.16 39.555 101.898 39.825 ;
     RECT  2.16 40.095 101.898 40.365 ;
     RECT  2.16 40.635 101.898 40.905 ;
     RECT  2.16 41.175 101.898 41.445 ;
     RECT  2.16 41.715 101.898 41.985 ;
     RECT  2.16 42.255 101.898 42.525 ;
     RECT  2.16 42.795 101.898 43.065 ;
     RECT  2.16 43.335 101.898 43.605 ;
     RECT  2.16 43.875 101.898 44.145 ;
     RECT  2.16 44.415 101.898 44.685 ;
     RECT  2.16 44.955 101.898 45.225 ;
     RECT  2.16 45.495 101.898 45.765 ;
     RECT  2.16 46.035 101.898 46.305 ;
     RECT  2.16 46.575 101.898 46.845 ;
     RECT  2.16 47.115 101.898 47.385 ;
     RECT  2.16 47.655 101.898 47.925 ;
     RECT  2.16 48.195 101.898 48.465 ;
     RECT  2.16 48.735 101.898 49.005 ;
     RECT  2.16 49.275 101.898 49.545 ;
     RECT  2.16 49.815 101.898 50.085 ;
     RECT  2.16 50.355 101.898 50.625 ;
     RECT  2.16 50.895 101.898 51.165 ;
     RECT  2.16 51.435 101.898 51.705 ;
     RECT  2.16 51.975 101.898 52.245 ;
     RECT  2.16 52.515 101.898 52.785 ;
     RECT  2.16 53.055 101.898 53.325 ;
     RECT  2.16 53.595 101.898 53.865 ;
     RECT  2.16 54.135 101.898 54.405 ;
     RECT  2.16 54.675 101.898 54.945 ;
     RECT  2.16 55.215 101.898 55.485 ;
     RECT  2.16 55.755 101.898 56.025 ;
     RECT  2.16 56.295 101.898 56.565 ;
     RECT  2.16 56.835 101.898 57.105 ;
     RECT  2.16 57.375 101.898 57.645 ;
     RECT  2.16 57.915 101.898 58.185 ;
     RECT  2.16 58.455 101.898 58.725 ;
     RECT  2.16 58.995 101.898 59.265 ;
     RECT  2.16 59.535 101.898 59.805 ;
     RECT  2.16 60.075 101.898 60.345 ;
     RECT  2.16 60.615 101.898 60.885 ;
     RECT  2.16 61.155 101.898 61.425 ;
     RECT  2.16 61.695 101.898 61.965 ;
     RECT  2.16 62.235 101.898 62.505 ;
     RECT  2.16 62.775 101.898 63.045 ;
     RECT  2.16 63.315 101.898 63.585 ;
     RECT  2.16 63.855 101.898 64.125 ;
     RECT  2.16 64.395 101.898 64.665 ;
     RECT  2.16 64.935 101.898 65.205 ;
     RECT  2.16 65.475 101.898 65.745 ;
     RECT  2.16 66.015 101.898 66.285 ;
     RECT  2.16 66.555 101.898 66.825 ;
     RECT  2.16 67.095 101.898 67.365 ;
     RECT  2.16 67.635 101.898 67.905 ;
     RECT  2.16 68.175 101.898 68.445 ;
     RECT  2.16 68.715 101.898 68.985 ;
     RECT  2.16 69.255 101.898 69.525 ;
     RECT  2.16 69.795 101.898 70.065 ;
     RECT  2.16 70.335 101.898 70.605 ;
     RECT  2.16 70.875 101.898 71.145 ;
     RECT  2.16 71.415 101.898 71.685 ;
     RECT  2.16 71.955 101.898 72.225 ;
     RECT  2.16 72.495 101.898 72.765 ;
     RECT  2.16 73.035 101.898 73.305 ;
     RECT  2.16 73.575 101.898 73.845 ;
     RECT  2.16 74.115 101.898 74.385 ;
     RECT  2.16 74.655 101.898 74.925 ;
     RECT  2.16 75.195 101.898 75.465 ;
     RECT  2.16 75.735 101.898 76.005 ;
     RECT  2.16 76.275 101.898 76.545 ;
     RECT  2.16 76.815 101.898 77.085 ;
     RECT  2.16 77.355 101.898 77.625 ;
     RECT  2.16 77.895 101.898 78.165 ;
     RECT  2.16 78.435 101.898 78.705 ;
     RECT  2.16 78.975 101.898 79.245 ;
     RECT  2.16 79.515 101.898 79.785 ;
     RECT  2.16 80.055 101.898 80.325 ;
     RECT  2.16 80.595 101.898 80.865 ;
     RECT  2.16 81.135 101.898 81.405 ;
     RECT  2.16 81.675 101.898 81.945 ;
     RECT  2.16 82.215 101.898 82.485 ;
     RECT  2.16 82.755 101.898 83.025 ;
     RECT  2.16 83.295 101.898 83.565 ;
     RECT  2.16 83.835 101.898 84.105 ;
     RECT  2.16 84.375 101.898 84.645 ;
     RECT  2.16 84.915 101.898 85.185 ;
     RECT  2.16 85.455 101.898 85.725 ;
     RECT  2.16 85.995 101.898 86.265 ;
     RECT  2.16 86.535 101.898 86.805 ;
     RECT  2.16 87.075 101.898 87.345 ;
     RECT  2.16 87.615 101.898 87.885 ;
     RECT  2.16 88.155 101.898 88.425 ;
     RECT  2.16 88.695 101.898 88.965 ;
     RECT  2.16 89.235 101.898 89.505 ;
     RECT  2.16 89.775 101.898 90.045 ;
     RECT  2.16 90.315 101.898 90.585 ;
     RECT  2.16 90.855 101.898 91.125 ;
     RECT  2.16 91.395 101.898 91.665 ;
     RECT  2.16 91.935 101.898 92.205 ;
     RECT  2.16 92.475 101.898 92.745 ;
     RECT  2.16 93.015 101.898 93.285 ;
     RECT  2.16 93.555 101.898 93.825 ;
     RECT  2.16 94.095 101.898 94.365 ;
     RECT  2.16 94.635 101.898 94.905 ;
     RECT  2.16 95.175 101.898 95.445 ;
     RECT  2.16 95.715 101.898 95.985 ;
     RECT  2.16 96.255 101.898 96.525 ;
     RECT  2.16 96.795 101.898 97.065 ;
     RECT  2.16 97.335 101.898 97.605 ;
     RECT  2.16 97.875 101.898 98.145 ;
     RECT  2.16 98.415 101.898 98.685 ;
     RECT  2.16 98.955 101.898 99.225 ;
     RECT  2.16 99.495 101.898 99.765 ;
     RECT  2.16 100.035 101.898 100.305 ;
     RECT  2.16 100.575 101.898 100.845 ;
     RECT  2.16 101.115 101.898 101.385 ;
     RECT  2.16 101.655 101.898 101.925 ;
     RECT  2.16 102.195 101.898 102.465 ;
     RECT  2.16 102.735 101.898 103.005 ;
     RECT  2.16 103.275 101.898 103.41 ;
    LAYER M1 ;
     RECT  2.16 2.151 101.898 103.419 ;
    LAYER M2 ;
     RECT  35.023 105.75 35.095 105.768 ;
     RECT  35.095 105.678 35.159 105.768 ;
     RECT  35.159 105.678 35.231 105.696 ;
     RECT  2.16 2.151 36.823 103.419 ;
     RECT  36.751 105.75 37.471 105.768 ;
     RECT  37.471 105.606 37.859 105.768 ;
     RECT  37.859 105.678 37.895 105.768 ;
     RECT  37.895 105.714 37.967 105.768 ;
     RECT  36.823 2.151 39.919 103.608 ;
     RECT  37.967 105.75 40.099 105.768 ;
     RECT  40.099 105.642 40.451 105.768 ;
     RECT  40.451 105.714 40.559 105.768 ;
     RECT  39.919 2.151 42.071 104.31 ;
     RECT  42.071 2.151 42.467 104.229 ;
     RECT  40.559 105.75 43.051 105.768 ;
     RECT  43.051 105.678 43.159 105.768 ;
     RECT  43.159 105.48 43.259 105.768 ;
     RECT  43.259 105.561 43.295 105.768 ;
     RECT  43.295 105.561 43.835 105.696 ;
     RECT  43.835 105.642 43.871 105.696 ;
     RECT  43.871 105.678 44.023 105.696 ;
     RECT  44.023 105.678 44.591 105.768 ;
     RECT  44.591 105.678 44.663 105.696 ;
     RECT  42.467 2.151 44.735 104.04 ;
     RECT  45.319 105.561 45.391 105.579 ;
     RECT  45.391 105.561 45.419 105.768 ;
     RECT  45.419 105.606 46.103 105.768 ;
     RECT  44.735 2.151 46.751 103.644 ;
     RECT  46.103 105.75 47.011 105.768 ;
     RECT  47.011 105.642 47.371 105.768 ;
     RECT  47.371 105.561 47.479 105.768 ;
     RECT  47.479 105.444 47.723 105.768 ;
     RECT  47.723 105.516 48.299 105.768 ;
     RECT  48.299 105.561 48.443 105.768 ;
     RECT  48.703 104.706 48.803 104.814 ;
     RECT  46.751 2.151 48.847 103.608 ;
     RECT  48.803 104.796 49.019 104.814 ;
     RECT  48.847 2.151 49.199 103.734 ;
     RECT  48.443 105.642 49.207 105.768 ;
     RECT  49.207 105.516 50.495 105.768 ;
     RECT  50.495 105.606 50.963 105.768 ;
     RECT  49.199 2.151 51.295 103.608 ;
     RECT  51.295 2.151 51.431 103.77 ;
     RECT  50.963 105.642 51.727 105.768 ;
     RECT  51.727 105.561 52.331 105.768 ;
     RECT  52.331 105.678 53.167 105.768 ;
     RECT  53.167 105.606 53.707 105.768 ;
     RECT  53.707 105.561 53.887 105.768 ;
     RECT  53.887 104.868 55.175 105.768 ;
     RECT  55.175 105.561 55.283 105.768 ;
     RECT  55.283 105.606 56.371 105.768 ;
     RECT  56.371 105.561 56.507 105.768 ;
     RECT  51.431 2.151 56.767 103.608 ;
     RECT  56.507 105.642 56.939 105.768 ;
     RECT  56.939 105.678 57.847 105.768 ;
     RECT  56.767 2.151 58.343 104.31 ;
     RECT  57.847 105.561 58.423 105.768 ;
     RECT  58.423 105.48 58.495 105.768 ;
     RECT  58.495 105.408 58.711 105.768 ;
     RECT  58.711 105.138 58.811 105.768 ;
     RECT  58.811 105.48 59.711 105.768 ;
     RECT  59.711 105.516 59.819 105.768 ;
     RECT  59.819 105.561 61.087 105.768 ;
     RECT  58.343 2.151 61.699 103.608 ;
     RECT  61.087 105.516 61.699 105.768 ;
     RECT  61.699 2.151 61.835 103.644 ;
     RECT  61.699 105.444 62.051 105.768 ;
     RECT  62.051 105.561 63.283 105.768 ;
     RECT  63.283 105.408 63.851 105.768 ;
     RECT  63.851 105.444 64.139 105.768 ;
     RECT  64.139 105.516 64.931 105.768 ;
     RECT  64.931 105.606 65.183 105.768 ;
     RECT  65.183 105.642 65.399 105.768 ;
     RECT  65.399 105.642 65.435 105.696 ;
     RECT  61.835 2.151 65.471 103.608 ;
     RECT  65.435 105.678 65.543 105.696 ;
     RECT  65.471 2.151 74.687 103.572 ;
     RECT  74.687 2.151 101.898 103.419 ;
     RECT  101.898 20.088 102.083 76.806 ;
     RECT  102.083 20.088 102.515 43.128 ;
     RECT  102.083 43.956 102.515 76.806 ;
     RECT  102.515 20.088 102.587 38.97 ;
     RECT  102.515 43.956 102.587 69.624 ;
     RECT  102.515 70.686 102.587 76.806 ;
     RECT  101.898 77.598 102.587 80.046 ;
     RECT  102.587 20.088 102.623 28.818 ;
     RECT  102.587 29.646 102.623 38.97 ;
     RECT  102.515 39.798 102.623 43.128 ;
     RECT  102.587 56.61 102.623 69.624 ;
     RECT  102.587 70.686 102.623 75.798 ;
     RECT  102.587 76.554 102.623 76.806 ;
     RECT  102.587 77.706 102.623 80.046 ;
     RECT  102.623 29.808 102.659 32.868 ;
     RECT  102.623 33.858 102.659 34.254 ;
     RECT  102.623 37.908 102.659 38.97 ;
     RECT  102.623 39.798 102.659 40.896 ;
     RECT  102.623 41.76 102.659 43.128 ;
     RECT  102.587 44.046 102.659 53.586 ;
     RECT  102.623 56.61 102.659 58.284 ;
     RECT  102.623 63.666 102.659 69.624 ;
     RECT  102.623 74.97 102.659 75.798 ;
     RECT  102.623 22.896 102.695 27.324 ;
     RECT  102.659 29.808 102.695 30.132 ;
     RECT  102.659 41.76 102.695 42.588 ;
     RECT  102.659 56.61 102.695 57.366 ;
     RECT  102.623 59.076 102.695 60.336 ;
     RECT  102.623 61.164 102.695 62.838 ;
     RECT  102.659 63.666 102.695 68.814 ;
     RECT  102.695 22.896 102.803 25.848 ;
     RECT  102.695 61.668 102.803 62.838 ;
     RECT  102.623 20.088 103.199 22.104 ;
     RECT  102.803 22.896 103.199 22.914 ;
     RECT  102.803 23.868 103.199 25.848 ;
     RECT  102.695 27.216 103.199 27.324 ;
     RECT  102.623 28.116 103.199 28.818 ;
     RECT  102.695 30.006 103.199 30.132 ;
     RECT  102.659 30.888 103.199 32.868 ;
     RECT  102.659 33.858 103.199 34.182 ;
     RECT  102.623 35.586 103.199 36.954 ;
     RECT  102.659 38.106 103.199 38.97 ;
     RECT  102.659 39.798 103.199 40.626 ;
     RECT  102.695 41.796 103.199 42.588 ;
     RECT  102.659 44.046 103.199 48.996 ;
     RECT  102.659 49.788 103.199 51.624 ;
     RECT  102.659 52.56 103.199 53.154 ;
     RECT  102.587 54.45 103.199 55.44 ;
     RECT  102.695 56.61 103.199 56.628 ;
     RECT  102.659 58.23 103.199 58.284 ;
     RECT  102.695 59.076 103.199 59.796 ;
     RECT  102.803 61.668 103.199 62.496 ;
     RECT  102.695 63.666 103.199 68.706 ;
     RECT  102.659 69.606 103.199 69.624 ;
     RECT  102.623 70.686 103.199 70.704 ;
     RECT  102.623 71.73 103.199 74.214 ;
     RECT  102.659 75.006 103.199 75.798 ;
     RECT  102.623 76.59 103.199 76.806 ;
     RECT  102.623 77.706 103.199 78.804 ;
     RECT  102.623 79.992 103.199 80.046 ;
     RECT  103.199 20.088 103.235 20.448 ;
     RECT  103.199 21.78 103.235 21.798 ;
     RECT  103.199 30.006 103.235 30.024 ;
     RECT  103.199 30.888 103.235 31.284 ;
     RECT  103.199 32.076 103.235 32.868 ;
     RECT  103.199 36.324 103.235 36.342 ;
     RECT  103.199 41.796 103.235 41.814 ;
     RECT  103.199 44.046 103.235 44.208 ;
     RECT  103.199 45.036 103.235 45.252 ;
     RECT  103.199 47.16 103.235 47.484 ;
     RECT  103.199 50.058 103.235 51.624 ;
     RECT  103.199 59.391 103.235 59.796 ;
     RECT  103.199 64.944 103.235 65.574 ;
     RECT  103.199 67.104 103.235 67.122 ;
     RECT  103.199 68.148 103.235 68.166 ;
     RECT  103.199 73.656 103.235 74.106 ;
     RECT  103.199 75.546 103.235 75.564 ;
     RECT  103.199 76.788 103.235 76.806 ;
     RECT  103.235 20.088 103.271 20.106 ;
     RECT  103.235 30.888 103.271 31.248 ;
     RECT  103.235 32.85 103.271 32.868 ;
     RECT  103.235 44.046 103.271 44.064 ;
     RECT  103.235 45.234 103.271 45.252 ;
     RECT  103.235 47.16 103.271 47.376 ;
     RECT  103.235 50.598 103.271 51.228 ;
     RECT  103.199 55.386 103.271 55.404 ;
     RECT  103.199 58.23 103.271 58.248 ;
     RECT  103.235 59.391 103.271 59.409 ;
     RECT  103.235 64.944 103.271 64.962 ;
     RECT  103.199 80.028 103.271 80.046 ;
     RECT  103.271 30.888 103.955 30.906 ;
     RECT  103.963 29.466 104.063 29.484 ;
    LAYER M3 ;
     RECT  2.415 2.143 2.505 2.413 ;
     RECT  5.115 2.143 5.205 2.413 ;
     RECT  7.815 2.143 7.905 2.413 ;
     RECT  10.515 2.143 10.605 2.413 ;
     RECT  13.215 2.143 13.305 2.413 ;
     RECT  15.915 2.143 16.005 2.413 ;
     RECT  18.615 2.143 18.705 2.413 ;
     RECT  21.315 2.143 21.405 2.413 ;
     RECT  24.015 2.143 24.105 2.413 ;
     RECT  26.715 2.143 26.805 2.413 ;
     RECT  29.415 2.143 29.505 2.413 ;
     RECT  32.115 2.143 32.205 2.413 ;
     RECT  34.815 2.143 34.905 2.413 ;
     RECT  37.515 2.143 37.605 2.413 ;
     RECT  40.215 2.143 40.305 2.413 ;
     RECT  42.915 2.143 43.005 2.413 ;
     RECT  45.615 2.143 45.705 2.413 ;
     RECT  48.315 2.143 48.405 2.413 ;
     RECT  51.015 2.143 51.105 2.413 ;
     RECT  53.715 2.143 53.805 2.413 ;
     RECT  56.415 2.143 56.505 2.413 ;
     RECT  59.115 2.143 59.205 2.413 ;
     RECT  61.815 2.143 61.905 2.413 ;
     RECT  64.515 2.143 64.605 2.413 ;
     RECT  67.215 2.143 67.305 2.413 ;
     RECT  69.915 2.143 70.005 2.413 ;
     RECT  72.615 2.143 72.705 2.413 ;
     RECT  75.315 2.143 75.405 2.413 ;
     RECT  78.015 2.143 78.105 2.413 ;
     RECT  80.715 2.143 80.805 2.413 ;
     RECT  83.415 2.143 83.505 2.413 ;
     RECT  86.115 2.143 86.205 2.413 ;
     RECT  88.815 2.143 88.905 2.413 ;
     RECT  91.515 2.143 91.605 2.413 ;
     RECT  94.215 2.143 94.305 2.413 ;
     RECT  96.915 2.143 97.005 2.413 ;
     RECT  99.615 2.143 99.705 2.413 ;
     RECT  99.615 2.413 99.897 20.011 ;
     RECT  101.088 20.005 101.106 20.011 ;
     RECT  103.176 19.915 103.194 20.011 ;
     RECT  96.915 2.413 97.197 20.047 ;
     RECT  101.016 20.011 101.682 20.047 ;
     RECT  103.176 20.011 103.23 20.083 ;
     RECT  103.176 20.083 103.266 20.107 ;
     RECT  96.912 20.047 97.197 20.155 ;
     RECT  99.615 20.011 99.918 20.191 ;
     RECT  103.14 20.107 103.266 20.191 ;
     RECT  94.215 2.413 94.497 20.281 ;
     RECT  95.364 20.119 95.382 20.281 ;
     RECT  99.216 20.191 99.918 20.299 ;
     RECT  100.944 20.047 101.682 20.299 ;
     RECT  102.6 20.191 103.266 20.333 ;
     RECT  102.6 20.333 103.23 20.453 ;
     RECT  96.912 20.155 97.722 20.461 ;
     RECT  42.915 2.413 43.197 20.587 ;
     RECT  99.216 20.299 101.682 20.623 ;
     RECT  94.215 20.281 95.382 20.672 ;
     RECT  94.215 20.672 96.066 20.683 ;
     RECT  96.876 20.461 97.722 20.683 ;
     RECT  98.676 20.623 101.682 20.683 ;
     RECT  94.215 20.683 101.682 20.779 ;
     RECT  102.6 20.453 103.194 20.779 ;
     RECT  59.115 2.413 59.397 20.965 ;
     RECT  94.215 20.779 103.194 20.993 ;
     RECT  102.564 20.993 103.194 21.451 ;
     RECT  58.608 20.965 59.397 21.541 ;
     RECT  42.696 20.587 43.197 21.631 ;
     RECT  58.284 21.541 59.397 21.631 ;
     RECT  61.815 2.413 62.097 21.703 ;
     RECT  58.212 21.631 59.397 21.731 ;
     RECT  94.215 20.993 101.718 21.739 ;
     RECT  102.564 21.451 103.23 21.739 ;
     RECT  94.215 21.739 103.23 21.803 ;
     RECT  94.215 21.803 103.194 21.965 ;
     RECT  94.215 21.965 100.746 22.027 ;
     RECT  56.415 2.413 56.697 22.045 ;
     RECT  93.96 22.027 100.746 22.109 ;
     RECT  101.556 21.965 103.194 22.109 ;
     RECT  56.016 22.045 56.697 22.171 ;
     RECT  88.815 2.413 89.097 22.171 ;
     RECT  94.032 22.109 100.746 22.199 ;
     RECT  55.944 22.171 56.697 22.271 ;
     RECT  90.54 22.081 90.558 22.271 ;
     RECT  85.248 22.351 85.266 22.469 ;
     RECT  101.556 22.109 102.798 22.469 ;
     RECT  88.815 22.171 89.766 22.621 ;
     RECT  42.372 21.631 43.197 22.711 ;
     RECT  88.38 22.621 89.766 22.891 ;
     RECT  101.988 22.469 102.798 22.891 ;
     RECT  94.14 22.199 100.746 22.981 ;
     RECT  45.615 2.413 45.897 22.987 ;
     RECT  46.944 20.425 46.962 22.987 ;
     RECT  53.715 2.413 53.997 22.987 ;
     RECT  61.815 21.703 62.514 22.987 ;
     RECT  69.915 2.413 70.197 22.987 ;
     RECT  78.015 2.413 78.297 22.987 ;
     RECT  79.02 22.783 79.038 22.987 ;
     RECT  86.115 2.413 86.397 22.987 ;
     RECT  90.612 22.855 90.702 23.081 ;
     RECT  94.14 22.981 101.25 23.083 ;
     RECT  45.615 22.987 45.99 23.117 ;
     RECT  46.764 22.987 46.962 23.117 ;
     RECT  53.715 22.987 54.738 23.117 ;
     RECT  90.648 23.081 90.702 23.125 ;
     RECT  83.415 2.413 83.697 23.161 ;
     RECT  93.96 23.083 101.25 23.189 ;
     RECT  42.372 22.711 43.794 23.251 ;
     RECT  83.415 23.161 83.898 23.315 ;
     RECT  78.015 22.987 79.038 23.323 ;
     RECT  84.636 22.621 84.726 23.431 ;
     RECT  88.308 22.891 89.766 23.585 ;
     RECT  58.608 21.731 59.397 23.629 ;
     RECT  60.732 22.009 60.75 23.629 ;
     RECT  37.515 2.413 37.797 23.665 ;
     RECT  94.215 23.189 101.25 23.701 ;
     RECT  101.988 22.891 103.194 23.701 ;
     RECT  42.372 23.251 44.262 23.791 ;
     RECT  86.115 22.987 86.49 23.803 ;
     RECT  58.608 23.629 60.75 23.819 ;
     RECT  65.628 23.395 65.646 23.819 ;
     RECT  94.215 23.701 103.194 23.819 ;
     RECT  37.515 23.665 38.178 23.827 ;
     RECT  75.315 2.413 75.597 23.827 ;
     RECT  90.648 23.125 90.774 23.855 ;
     RECT  67.215 2.413 67.497 23.863 ;
     RECT  64.515 2.413 64.797 23.899 ;
     RECT  60.192 23.819 60.75 23.927 ;
     RECT  61.815 22.987 62.73 23.927 ;
     RECT  69.915 22.987 70.722 23.933 ;
     RECT  77.4 23.323 79.038 23.933 ;
     RECT  86.115 23.803 86.67 23.933 ;
     RECT  94.215 23.819 100.818 24.125 ;
     RECT  94.215 24.125 95.202 24.205 ;
     RECT  101.628 23.819 103.194 24.233 ;
     RECT  45.615 23.117 45.897 24.241 ;
     RECT  90.648 23.855 90.702 24.367 ;
     RECT  74.664 23.827 75.597 24.395 ;
     RECT  37.008 23.827 38.178 24.403 ;
     RECT  70.956 24.331 70.974 24.431 ;
     RECT  90.612 24.367 90.702 24.467 ;
     RECT  69.915 23.933 70.197 24.511 ;
     RECT  45.615 24.241 46.17 24.539 ;
     RECT  94.068 24.205 95.202 24.539 ;
     RECT  37.008 24.403 38.286 24.601 ;
     RECT  66.888 23.863 67.497 24.601 ;
     RECT  95.94 24.125 100.818 24.601 ;
     RECT  69.84 24.511 70.197 24.629 ;
     RECT  66.744 24.601 67.497 24.701 ;
     RECT  71.676 24.601 71.694 24.701 ;
     RECT  90.648 24.467 90.702 24.709 ;
     RECT  87.696 24.331 87.714 24.773 ;
     RECT  86.115 23.933 86.397 24.781 ;
     RECT  90.648 24.709 90.738 24.809 ;
     RECT  85.788 24.781 86.397 24.899 ;
     RECT  66.78 24.701 67.497 24.935 ;
     RECT  94.215 24.539 95.202 25.015 ;
     RECT  95.94 24.601 100.89 25.015 ;
     RECT  37.008 24.601 38.682 25.051 ;
     RECT  94.215 25.015 100.89 25.195 ;
     RECT  88.815 23.585 89.766 25.205 ;
     RECT  94.215 25.195 101.214 25.285 ;
     RECT  93.78 25.285 101.214 25.291 ;
     RECT  102.024 24.233 103.194 25.291 ;
     RECT  92.7 25.141 92.718 25.321 ;
     RECT  88.815 25.205 89.586 25.439 ;
     RECT  93.78 25.291 103.194 25.439 ;
     RECT  75.315 24.395 75.597 25.483 ;
     RECT  92.7 25.321 92.79 25.511 ;
     RECT  88.815 25.439 89.097 25.555 ;
     RECT  90.648 24.809 90.666 25.583 ;
     RECT  37.008 25.051 38.754 25.681 ;
     RECT  93.852 25.439 103.194 25.853 ;
     RECT  86.115 24.899 86.397 25.861 ;
     RECT  91.515 2.413 91.797 25.861 ;
     RECT  90.684 25.681 90.702 25.889 ;
     RECT  69.915 24.629 70.197 25.963 ;
     RECT  77.4 23.933 78.297 25.963 ;
     RECT  79.02 23.933 79.038 25.963 ;
     RECT  86.076 25.861 86.397 25.987 ;
     RECT  93.852 25.853 102.69 26.015 ;
     RECT  69.915 25.963 70.722 26.093 ;
     RECT  77.4 25.963 79.038 26.093 ;
     RECT  86.004 25.987 86.397 26.123 ;
     RECT  88.344 25.555 89.097 26.123 ;
     RECT  93.96 26.015 102.69 26.159 ;
     RECT  37.008 25.681 39.294 26.257 ;
     RECT  40.215 2.413 40.497 26.257 ;
     RECT  91.515 25.861 92.358 26.321 ;
     RECT  94.215 26.159 100.998 26.381 ;
     RECT  91.515 26.321 91.797 26.401 ;
     RECT  91.44 26.401 91.797 26.519 ;
     RECT  54.936 26.671 54.954 26.825 ;
     RECT  101.952 26.159 102.69 27.019 ;
     RECT  41.904 23.791 44.262 27.067 ;
     RECT  45.615 24.539 45.897 27.067 ;
     RECT  94.215 26.381 100.962 27.103 ;
     RECT  46.944 23.117 46.962 27.139 ;
     RECT  48.315 2.413 48.597 27.139 ;
     RECT  101.952 27.019 103.194 27.149 ;
     RECT  94.215 27.103 101.106 27.211 ;
     RECT  41.904 27.067 45.897 27.409 ;
     RECT  60.732 23.927 60.75 27.445 ;
     RECT  63.648 27.481 63.666 27.599 ;
     RECT  94.215 27.211 101.142 27.643 ;
     RECT  90.684 27.211 90.702 27.671 ;
     RECT  41.904 27.409 46.134 27.679 ;
     RECT  41.904 27.679 46.206 27.715 ;
     RECT  46.944 27.139 48.597 27.715 ;
     RECT  84.636 23.431 84.798 27.751 ;
     RECT  41.904 27.715 48.597 27.779 ;
     RECT  84.636 27.751 85.05 27.841 ;
     RECT  94.215 27.643 101.502 27.979 ;
     RECT  66.888 24.935 67.497 28.021 ;
     RECT  66.492 28.021 67.497 28.139 ;
     RECT  94.215 27.979 101.718 28.267 ;
     RECT  102.492 27.149 103.194 28.267 ;
     RECT  84.636 27.841 85.122 28.481 ;
     RECT  41.904 27.779 46.89 28.651 ;
     RECT  47.628 27.779 48.597 28.651 ;
     RECT  94.215 28.267 103.194 28.823 ;
     RECT  60.732 27.445 60.786 28.831 ;
     RECT  94.215 28.823 102.654 28.859 ;
     RECT  101.628 28.859 102.654 29.057 ;
     RECT  101.988 29.057 102.654 29.291 ;
     RECT  90.648 29.191 90.666 29.371 ;
     RECT  102.024 29.291 102.654 29.399 ;
     RECT  103.968 29.419 103.986 29.461 ;
     RECT  90.648 29.371 90.738 29.489 ;
     RECT  103.968 29.461 104.058 29.489 ;
     RECT  104.04 29.489 104.058 29.501 ;
     RECT  102.492 29.399 102.654 29.561 ;
     RECT  51.015 2.413 51.297 29.569 ;
     RECT  52.74 26.329 52.758 29.605 ;
     RECT  102.564 29.561 102.654 29.611 ;
     RECT  102.564 29.611 102.69 29.707 ;
     RECT  53.715 23.117 53.997 29.803 ;
     RECT  94.215 28.859 100.89 29.803 ;
     RECT  50.976 29.569 51.297 29.875 ;
     RECT  94.215 29.803 100.998 29.875 ;
     RECT  102.564 29.707 103.194 29.899 ;
     RECT  86.115 26.123 86.397 29.911 ;
     RECT  90.648 29.489 90.666 30.029 ;
     RECT  102.564 29.899 103.23 30.029 ;
     RECT  61.815 23.927 62.514 30.145 ;
     RECT  52.632 29.605 52.758 30.181 ;
     RECT  52.092 30.181 52.758 30.271 ;
     RECT  86.115 29.911 86.454 30.271 ;
     RECT  88.815 26.123 89.097 30.271 ;
     RECT  94.215 29.875 101.286 30.283 ;
     RECT  53.715 29.803 54.27 30.307 ;
     RECT  86.115 30.271 86.706 30.307 ;
     RECT  88.815 30.271 89.37 30.307 ;
     RECT  88.815 30.307 89.442 30.331 ;
     RECT  88.815 30.331 89.478 30.371 ;
     RECT  72.615 2.413 72.897 30.379 ;
     RECT  94.215 30.283 101.502 30.379 ;
     RECT  102.564 30.029 103.194 30.379 ;
     RECT  86.115 30.307 86.778 30.443 ;
     RECT  88.815 30.371 89.442 30.443 ;
     RECT  56.415 22.271 56.697 30.451 ;
     RECT  50.904 29.875 51.297 30.649 ;
     RECT  52.092 30.271 52.794 30.649 ;
     RECT  94.215 30.379 103.194 30.859 ;
     RECT  103.932 30.667 103.95 30.859 ;
     RECT  94.215 30.859 103.95 30.911 ;
     RECT  50.904 30.649 52.794 30.955 ;
     RECT  53.715 30.307 54.558 30.955 ;
     RECT  58.608 23.819 59.397 30.991 ;
     RECT  60.12 28.831 60.786 30.991 ;
     RECT  90.72 30.955 90.738 31.117 ;
     RECT  55.728 30.451 56.697 31.189 ;
     RECT  90.648 31.117 90.738 31.217 ;
     RECT  94.215 30.911 103.266 31.253 ;
     RECT  94.215 31.253 103.23 31.289 ;
     RECT  50.904 30.955 54.558 31.423 ;
     RECT  50.256 31.423 54.558 31.657 ;
     RECT  94.215 31.289 103.194 31.709 ;
     RECT  90.648 31.217 90.702 31.721 ;
     RECT  41.904 28.651 48.597 31.801 ;
     RECT  49.86 31.657 54.558 31.801 ;
     RECT  101.664 31.709 103.194 32.071 ;
     RECT  101.664 32.071 103.23 32.333 ;
     RECT  88.815 30.443 89.097 32.341 ;
     RECT  88.308 32.341 89.097 32.459 ;
     RECT  58.608 30.991 60.786 32.467 ;
     RECT  61.815 30.145 63.09 32.467 ;
     RECT  102.456 32.333 103.23 32.491 ;
     RECT  90.648 31.721 90.666 32.503 ;
     RECT  69.915 26.093 70.197 32.575 ;
     RECT  94.215 31.709 100.782 32.587 ;
     RECT  101.664 32.333 101.682 32.587 ;
     RECT  69.588 32.575 70.197 32.611 ;
     RECT  90.648 32.503 90.702 32.809 ;
     RECT  91.476 26.519 91.797 32.809 ;
     RECT  102.456 32.491 103.266 32.873 ;
     RECT  83.415 23.315 83.697 32.881 ;
     RECT  84.636 28.481 84.798 32.881 ;
     RECT  69.588 32.611 70.29 32.999 ;
     RECT  68.652 24.871 68.67 33.007 ;
     RECT  69.588 32.999 70.197 33.007 ;
     RECT  94.215 32.587 101.682 33.067 ;
     RECT  102.456 32.873 102.654 33.067 ;
     RECT  90.648 32.809 91.797 33.071 ;
     RECT  58.608 32.467 63.09 33.115 ;
     RECT  94.215 33.067 102.654 33.115 ;
     RECT  64.515 23.899 64.998 33.349 ;
     RECT  77.4 26.093 78.297 33.421 ;
     RECT  79.02 26.093 79.038 33.421 ;
     RECT  93.78 33.115 102.654 33.421 ;
     RECT  77.4 33.421 79.038 33.539 ;
     RECT  90.648 33.071 90.666 33.539 ;
     RECT  58.608 33.115 63.378 33.583 ;
     RECT  64.188 33.349 64.998 33.583 ;
     RECT  93.744 33.421 102.654 33.683 ;
     RECT  93.744 33.683 101.106 33.821 ;
     RECT  101.916 33.683 102.654 33.835 ;
     RECT  93.744 33.821 101.034 33.845 ;
     RECT  93.744 33.845 100.998 33.965 ;
     RECT  93.744 33.965 100.782 34.115 ;
     RECT  90.684 34.429 90.702 34.529 ;
     RECT  91.476 33.071 91.797 34.619 ;
     RECT  83.415 32.881 84.798 34.627 ;
     RECT  83.16 34.627 84.798 34.799 ;
     RECT  93.744 34.115 100.746 34.891 ;
     RECT  101.916 33.835 103.194 34.891 ;
     RECT  58.608 33.583 64.998 35.203 ;
     RECT  90.324 35.509 90.342 35.671 ;
     RECT  90.324 35.671 90.666 35.771 ;
     RECT  93.744 34.891 103.194 35.807 ;
     RECT  101.988 35.807 103.194 35.879 ;
     RECT  66.6 28.139 67.497 36.121 ;
     RECT  102.024 35.879 103.194 36.139 ;
     RECT  66.492 36.121 67.497 36.239 ;
     RECT  102.024 36.139 103.23 36.347 ;
     RECT  58.608 35.203 65.394 36.355 ;
     RECT  58.608 36.355 65.43 36.509 ;
     RECT  88.815 32.459 89.097 36.589 ;
     RECT  90.324 35.771 90.342 36.589 ;
     RECT  55.548 31.189 56.697 36.661 ;
     RECT  92.628 36.625 92.646 36.661 ;
     RECT  102.024 36.347 103.194 36.959 ;
     RECT  59.115 36.509 65.43 37.165 ;
     RECT  93.744 35.807 101.214 37.195 ;
     RECT  102.024 36.959 102.618 37.195 ;
     RECT  93.744 37.195 102.618 37.463 ;
     RECT  92.628 36.661 92.718 37.741 ;
     RECT  93.744 37.463 100.998 37.769 ;
     RECT  101.916 37.463 102.618 37.771 ;
     RECT  101.916 37.771 102.654 38.101 ;
     RECT  101.916 38.101 103.194 38.201 ;
     RECT  101.988 38.201 103.194 38.309 ;
     RECT  66.6 36.239 67.497 38.443 ;
     RECT  102.564 38.309 103.194 38.471 ;
     RECT  59.115 37.165 65.754 38.551 ;
     RECT  66.564 38.443 67.497 38.551 ;
     RECT  41.904 31.801 54.558 38.821 ;
     RECT  93.744 37.769 100.818 38.983 ;
     RECT  75.315 25.483 75.654 39.019 ;
     RECT  93.744 38.983 101.358 39.115 ;
     RECT  93.744 39.115 101.61 39.209 ;
     RECT  103.176 38.471 103.194 39.211 ;
     RECT  101.556 39.209 101.61 39.361 ;
     RECT  102.492 39.211 103.194 39.361 ;
     RECT  101.556 39.361 103.194 39.623 ;
     RECT  93.744 39.209 100.818 40.171 ;
     RECT  93.744 40.171 101.07 40.433 ;
     RECT  102.024 39.623 103.194 40.631 ;
     RECT  88.815 36.589 90.342 40.711 ;
     RECT  88.815 40.711 90.702 40.937 ;
     RECT  102.024 40.631 102.654 41.035 ;
     RECT  77.4 33.539 78.297 41.251 ;
     RECT  79.02 33.539 79.038 41.251 ;
     RECT  93.744 40.433 100.998 41.323 ;
     RECT  101.916 41.035 102.654 41.323 ;
     RECT  93.744 41.323 102.654 41.419 ;
     RECT  41.544 38.821 54.558 41.611 ;
     RECT  68.652 33.007 70.197 41.611 ;
     RECT  86.115 30.443 86.454 41.611 ;
     RECT  93.744 41.419 102.69 41.611 ;
     RECT  93.744 41.611 103.194 41.707 ;
     RECT  86.115 41.611 86.67 41.741 ;
     RECT  88.815 40.937 90.666 41.755 ;
     RECT  91.515 34.619 91.797 41.755 ;
     RECT  93.744 41.707 103.23 41.819 ;
     RECT  88.815 41.755 91.797 42.053 ;
     RECT  41.544 41.611 54.738 42.557 ;
     RECT  68.652 41.611 70.722 42.557 ;
     RECT  77.4 41.251 79.038 42.557 ;
     RECT  86.115 41.741 86.49 42.557 ;
     RECT  93.744 41.819 103.194 42.593 ;
     RECT  83.415 34.799 84.798 42.601 ;
     RECT  93.744 42.593 102.69 42.605 ;
     RECT  88.815 42.053 90.702 42.719 ;
     RECT  93.744 42.605 102.654 43.181 ;
     RECT  57.888 43.303 57.906 43.375 ;
     RECT  57.6 43.375 57.906 43.411 ;
     RECT  57.6 43.411 57.942 43.529 ;
     RECT  55.548 36.661 56.862 43.645 ;
     RECT  57.6 43.529 57.906 43.645 ;
     RECT  93.744 43.181 102.618 44.041 ;
     RECT  93.744 44.041 103.266 44.045 ;
     RECT  88.815 42.719 90.342 44.113 ;
     RECT  59.115 38.551 67.497 44.419 ;
     RECT  92.592 37.741 92.718 44.617 ;
     RECT  93.744 44.045 101.25 44.617 ;
     RECT  88.815 44.113 90.702 44.689 ;
     RECT  102.024 44.045 103.266 44.753 ;
     RECT  55.548 43.645 57.906 44.761 ;
     RECT  58.824 44.419 67.497 44.761 ;
     RECT  91.515 42.053 91.797 44.761 ;
     RECT  92.592 44.617 101.25 44.761 ;
     RECT  88.815 44.689 90.774 44.789 ;
     RECT  74.808 39.019 75.654 44.851 ;
     RECT  68.652 42.557 70.197 44.887 ;
     RECT  71.964 30.379 72.897 44.887 ;
     RECT  74.52 44.851 75.654 44.909 ;
     RECT  102.528 44.753 103.266 44.951 ;
     RECT  68.652 44.887 70.758 44.987 ;
     RECT  71.964 44.887 73.386 44.987 ;
     RECT  71.964 44.987 72.99 45.023 ;
     RECT  91.515 44.761 101.25 45.193 ;
     RECT  102.6 44.951 103.266 45.257 ;
     RECT  102.6 45.257 103.23 45.485 ;
     RECT  102.6 45.485 103.194 45.491 ;
     RECT  91.515 45.193 101.502 45.581 ;
     RECT  68.652 44.987 70.197 45.739 ;
     RECT  77.4 42.557 78.297 45.739 ;
     RECT  79.02 42.557 79.038 45.739 ;
     RECT  86.115 42.557 86.397 45.739 ;
     RECT  91.515 45.581 100.962 45.761 ;
     RECT  41.544 42.557 54.558 45.805 ;
     RECT  68.652 45.739 70.722 45.869 ;
     RECT  77.4 45.739 79.038 45.869 ;
     RECT  86.115 45.739 86.67 45.869 ;
     RECT  41.544 45.805 54.738 46.201 ;
     RECT  55.548 44.761 67.497 46.201 ;
     RECT  101.988 45.733 102.078 46.219 ;
     RECT  103.176 45.491 103.194 46.219 ;
     RECT  92.592 45.761 100.962 46.315 ;
     RECT  101.988 46.219 103.194 46.315 ;
     RECT  92.592 46.315 103.194 46.643 ;
     RECT  92.592 46.643 101.574 46.685 ;
     RECT  88.815 44.789 90.342 46.921 ;
     RECT  102.672 46.643 103.194 46.987 ;
     RECT  88.815 46.921 90.738 47.111 ;
     RECT  37.008 26.257 40.497 47.281 ;
     RECT  41.544 46.201 67.497 47.281 ;
     RECT  92.592 46.685 101.502 47.501 ;
     RECT  102.672 46.987 103.266 47.563 ;
     RECT  102.6 47.563 103.266 47.755 ;
     RECT  102.528 47.755 103.266 47.947 ;
     RECT  102.024 47.947 103.266 48.173 ;
     RECT  92.592 47.501 101.25 48.271 ;
     RECT  102.024 48.173 103.194 48.271 ;
     RECT  92.592 48.271 103.194 48.389 ;
     RECT  88.815 47.111 90.666 48.497 ;
     RECT  90.648 48.497 90.666 48.541 ;
     RECT  90.648 48.541 90.738 48.767 ;
     RECT  102.024 48.389 103.194 49.001 ;
     RECT  92.592 48.389 101.178 49.279 ;
     RECT  102.024 49.001 102.654 49.279 ;
     RECT  83.415 42.601 85.194 49.343 ;
     RECT  90.648 48.767 90.666 49.621 ;
     RECT  92.592 49.279 102.654 49.771 ;
     RECT  83.415 49.343 84.798 49.883 ;
     RECT  90.648 49.621 90.738 49.891 ;
     RECT  91.515 45.761 91.797 49.891 ;
     RECT  92.592 49.771 103.194 50.053 ;
     RECT  90.648 49.891 91.797 50.093 ;
     RECT  92.592 50.053 103.23 50.347 ;
     RECT  88.815 48.497 89.766 50.387 ;
     RECT  92.592 50.347 103.266 50.423 ;
     RECT  90.648 50.093 90.774 50.459 ;
     RECT  94.104 50.423 103.266 50.459 ;
     RECT  37.008 47.281 67.497 50.549 ;
     RECT  90.648 50.459 90.702 50.549 ;
     RECT  101.484 50.459 103.266 50.573 ;
     RECT  90.684 50.549 90.702 50.585 ;
     RECT  101.628 50.573 103.266 51.233 ;
     RECT  101.628 51.233 103.23 51.269 ;
     RECT  94.104 50.459 100.71 51.367 ;
     RECT  101.916 51.269 103.23 51.629 ;
     RECT  37.008 50.549 54.99 51.871 ;
     RECT  55.728 50.549 67.497 51.871 ;
     RECT  90.756 51.907 90.774 51.943 ;
     RECT  77.4 45.869 78.297 51.979 ;
     RECT  79.02 45.869 79.038 51.979 ;
     RECT  80.715 2.413 80.997 51.979 ;
     RECT  101.916 51.629 103.194 52.015 ;
     RECT  80.136 51.979 80.997 52.051 ;
     RECT  82.332 24.943 82.35 52.051 ;
     RECT  83.415 49.883 83.697 52.051 ;
     RECT  94.104 51.367 100.89 52.051 ;
     RECT  101.664 52.015 103.194 52.051 ;
     RECT  80.136 52.051 81.162 52.169 ;
     RECT  80.208 52.169 81.162 52.205 ;
     RECT  80.208 52.205 80.997 52.241 ;
     RECT  90.648 51.943 90.774 52.277 ;
     RECT  77.4 51.979 79.038 52.439 ;
     RECT  82.332 52.051 83.697 52.439 ;
     RECT  2.415 2.413 2.697 52.681 ;
     RECT  2.412 52.681 2.697 52.825 ;
     RECT  94.104 52.051 103.194 52.889 ;
     RECT  2.376 52.825 2.697 52.951 ;
     RECT  92.592 50.423 93.186 52.951 ;
     RECT  94.104 52.889 101.682 52.951 ;
     RECT  92.592 52.951 101.682 52.979 ;
     RECT  2.304 52.951 2.697 53.021 ;
     RECT  90.648 52.277 90.738 53.131 ;
     RECT  91.515 50.093 91.797 53.131 ;
     RECT  102.6 52.889 103.194 53.165 ;
     RECT  92.592 52.979 101.502 53.261 ;
     RECT  90.648 53.131 91.797 53.357 ;
     RECT  90.648 53.357 90.774 53.429 ;
     RECT  90.648 53.429 90.666 53.519 ;
     RECT  92.592 53.261 101.214 53.519 ;
     RECT  102.6 53.165 102.654 53.611 ;
     RECT  102.564 53.611 102.654 53.707 ;
     RECT  94.104 53.519 101.214 53.897 ;
     RECT  102.024 53.707 102.654 54.131 ;
     RECT  102.492 54.131 102.654 54.187 ;
     RECT  94.14 53.897 101.214 54.401 ;
     RECT  94.215 54.401 101.214 54.571 ;
     RECT  90.648 54.877 90.666 54.985 ;
     RECT  90.648 54.985 90.738 55.013 ;
     RECT  94.215 54.571 101.502 55.051 ;
     RECT  102.492 54.187 103.194 55.051 ;
     RECT  92.592 53.519 93.258 55.247 ;
     RECT  90.72 55.013 90.738 55.283 ;
     RECT  94.215 55.051 103.194 55.381 ;
     RECT  94.215 55.381 103.266 55.565 ;
     RECT  90.648 55.993 90.666 56.065 ;
     RECT  94.215 55.565 102.582 56.237 ;
     RECT  94.215 56.237 100.89 56.285 ;
     RECT  101.628 56.237 102.582 56.363 ;
     RECT  94.215 56.285 100.746 56.371 ;
     RECT  102.492 56.363 102.582 56.395 ;
     RECT  71.964 45.023 72.897 56.443 ;
     RECT  71.856 56.443 72.897 56.461 ;
     RECT  71.748 56.461 72.897 56.491 ;
     RECT  71.748 56.491 73.422 56.525 ;
     RECT  90.648 56.065 90.738 56.561 ;
     RECT  102.492 56.395 103.194 56.633 ;
     RECT  90.72 56.561 90.738 56.641 ;
     RECT  91.515 53.357 91.797 56.641 ;
     RECT  90.72 56.641 91.797 56.669 ;
     RECT  71.856 56.525 73.422 56.759 ;
     RECT  94.068 56.371 100.746 56.759 ;
     RECT  90.792 56.669 91.797 56.831 ;
     RECT  94.068 56.759 100.71 57.101 ;
     RECT  101.628 56.363 101.646 57.163 ;
     RECT  102.492 56.633 102.69 57.163 ;
     RECT  92.592 55.247 93.186 57.173 ;
     RECT  92.664 57.173 93.186 57.209 ;
     RECT  94.215 57.101 100.71 57.335 ;
     RECT  101.628 57.163 102.69 57.371 ;
     RECT  95.976 57.335 100.71 57.437 ;
     RECT  101.628 57.371 102.654 57.451 ;
     RECT  96.012 57.437 100.71 57.569 ;
     RECT  101.448 57.451 102.654 57.569 ;
     RECT  96.588 57.569 100.71 57.649 ;
     RECT  101.448 57.569 101.682 57.649 ;
     RECT  96.588 57.649 101.682 57.713 ;
     RECT  93.168 57.209 93.186 57.883 ;
     RECT  74.808 44.909 75.654 57.991 ;
     RECT  102.6 57.569 102.654 58.225 ;
     RECT  101.664 57.713 101.682 58.315 ;
     RECT  102.6 58.225 103.266 58.315 ;
     RECT  101.664 58.315 103.266 58.379 ;
     RECT  96.588 57.713 100.89 58.495 ;
     RECT  102.024 58.379 103.266 58.523 ;
     RECT  102.492 58.523 103.266 58.637 ;
     RECT  94.215 57.335 95.094 58.651 ;
     RECT  95.976 58.495 100.89 58.651 ;
     RECT  94.215 58.651 100.89 58.781 ;
     RECT  79.02 52.439 79.038 58.919 ;
     RECT  95.76 58.781 100.89 58.987 ;
     RECT  95.76 58.987 100.926 59.161 ;
     RECT  95.76 59.161 100.998 59.261 ;
     RECT  102.492 58.637 103.194 59.269 ;
     RECT  101.988 59.269 103.194 59.386 ;
     RECT  101.988 59.386 103.266 59.789 ;
     RECT  101.988 59.789 103.23 59.801 ;
     RECT  95.76 59.261 100.962 59.873 ;
     RECT  94.215 58.781 94.986 59.971 ;
     RECT  95.76 59.873 97.686 59.971 ;
     RECT  98.604 59.873 100.962 60.007 ;
     RECT  101.988 59.801 102.69 60.007 ;
     RECT  94.215 59.971 97.686 60.859 ;
     RECT  98.604 60.007 102.69 60.859 ;
     RECT  94.215 60.859 102.69 60.917 ;
     RECT  94.215 60.917 100.638 60.953 ;
     RECT  93.168 57.883 93.222 61.123 ;
     RECT  101.412 60.917 102.69 61.349 ;
     RECT  90.324 58.081 90.342 61.393 ;
     RECT  92.988 61.123 93.222 61.393 ;
     RECT  101.484 61.349 102.69 61.421 ;
     RECT  102.024 61.421 102.69 61.483 ;
     RECT  90.324 61.393 90.666 61.493 ;
     RECT  92.916 61.393 93.222 61.493 ;
     RECT  94.215 60.953 100.458 62.167 ;
     RECT  94.215 62.167 100.71 62.203 ;
     RECT  93.168 61.493 93.222 62.239 ;
     RECT  94.215 62.203 101.178 62.401 ;
     RECT  94.215 62.401 101.25 62.473 ;
     RECT  102.024 61.483 103.194 62.473 ;
     RECT  94.215 62.473 103.194 62.501 ;
     RECT  94.215 62.501 102.798 62.573 ;
     RECT  90.324 61.493 90.342 62.941 ;
     RECT  102.456 62.573 102.798 63.077 ;
     RECT  90.324 62.941 90.666 63.121 ;
     RECT  90.324 63.121 90.738 63.275 ;
     RECT  102.492 63.077 102.798 63.499 ;
     RECT  37.008 51.871 67.497 63.815 ;
     RECT  94.215 62.573 101.574 63.883 ;
     RECT  102.492 63.499 103.194 63.883 ;
     RECT  94.215 63.883 103.194 63.887 ;
     RECT  90.324 63.275 90.702 63.923 ;
     RECT  37.008 63.815 65.826 64.129 ;
     RECT  92.916 62.239 93.222 64.129 ;
     RECT  92.916 64.129 93.258 64.319 ;
     RECT  88.056 32.539 88.074 64.363 ;
     RECT  92.988 64.319 93.222 64.391 ;
     RECT  96.912 63.887 103.194 64.391 ;
     RECT  90.324 63.923 90.666 64.589 ;
     RECT  94.215 63.887 96.174 64.651 ;
     RECT  96.912 64.391 101.502 64.651 ;
     RECT  94.215 64.651 101.502 64.685 ;
     RECT  87.804 64.363 88.074 64.697 ;
     RECT  94.215 64.685 100.926 64.781 ;
     RECT  86.115 45.869 86.397 64.831 ;
     RECT  93.168 64.391 93.222 64.859 ;
     RECT  94.215 64.781 100.818 64.859 ;
     RECT  94.215 64.859 100.746 64.931 ;
     RECT  102.6 64.391 103.194 64.939 ;
     RECT  86.115 64.831 86.742 64.967 ;
     RECT  96.228 64.931 100.746 64.967 ;
     RECT  90.324 64.589 90.378 65.003 ;
     RECT  94.215 64.931 95.094 65.129 ;
     RECT  96.228 64.967 100.458 65.129 ;
     RECT  102.6 64.939 103.266 65.165 ;
     RECT  96.915 65.129 100.458 65.713 ;
     RECT  101.196 65.641 101.214 65.713 ;
     RECT  96.915 65.713 101.214 65.741 ;
     RECT  88.815 50.387 89.097 65.749 ;
     RECT  90.324 65.003 90.342 65.749 ;
     RECT  90.324 65.749 90.666 65.849 ;
     RECT  102.6 65.165 103.23 65.933 ;
     RECT  94.215 65.129 94.77 66.019 ;
     RECT  95.724 65.749 95.778 66.019 ;
     RECT  94.215 66.019 95.778 66.181 ;
     RECT  101.628 66.091 101.646 66.181 ;
     RECT  102.6 65.933 103.194 66.181 ;
     RECT  88.815 65.749 89.514 66.245 ;
     RECT  94.215 66.181 96.138 66.253 ;
     RECT  96.915 65.741 100.818 66.253 ;
     RECT  94.215 66.253 100.818 66.479 ;
     RECT  101.628 66.181 103.194 66.901 ;
     RECT  101.484 66.901 103.194 66.955 ;
     RECT  101.484 66.955 103.23 67.127 ;
     RECT  90.324 65.849 90.342 67.261 ;
     RECT  94.215 66.479 100.458 67.333 ;
     RECT  93.168 64.859 93.186 67.405 ;
     RECT  94.215 67.333 100.746 67.405 ;
     RECT  101.484 67.127 103.194 67.405 ;
     RECT  90.324 67.261 90.738 67.442 ;
     RECT  93.168 67.405 103.194 67.559 ;
     RECT  93.168 67.559 100.746 67.595 ;
     RECT  93.168 67.595 100.71 67.973 ;
     RECT  101.484 67.559 103.194 68.141 ;
     RECT  102.564 68.141 103.194 68.143 ;
     RECT  102.564 68.143 103.23 68.333 ;
     RECT  94.215 67.973 100.71 68.341 ;
     RECT  101.484 68.141 101.502 68.341 ;
     RECT  94.215 68.341 101.502 68.369 ;
     RECT  90.324 67.442 90.702 68.449 ;
     RECT  90.324 68.449 90.738 68.521 ;
     RECT  91.515 56.831 91.797 68.521 ;
     RECT  90.324 68.521 91.797 68.711 ;
     RECT  102.564 68.333 103.194 68.717 ;
     RECT  94.215 68.369 101.178 68.747 ;
     RECT  102.564 68.717 102.69 68.819 ;
     RECT  96.048 68.747 101.178 68.945 ;
     RECT  96.336 68.945 101.178 69.163 ;
     RECT  94.215 68.747 95.166 69.223 ;
     RECT  102.564 68.819 102.654 69.259 ;
     RECT  102.492 69.259 102.654 69.448 ;
     RECT  102.456 69.448 102.654 69.485 ;
     RECT  102.492 69.485 102.654 69.601 ;
     RECT  94.068 69.223 95.166 69.691 ;
     RECT  96.336 69.163 101.646 69.691 ;
     RECT  102.492 69.601 103.194 69.773 ;
     RECT  91.515 68.711 91.797 69.799 ;
     RECT  94.068 69.691 101.646 69.827 ;
     RECT  94.068 69.827 100.53 69.899 ;
     RECT  101.34 69.827 101.646 70.097 ;
     RECT  90.324 68.711 90.342 70.123 ;
     RECT  91.515 69.799 91.854 70.123 ;
     RECT  90.324 70.123 91.854 70.133 ;
     RECT  90.324 70.133 91.797 70.259 ;
     RECT  101.34 70.097 101.574 70.445 ;
     RECT  102.492 69.773 102.51 70.603 ;
     RECT  94.215 69.899 100.53 70.681 ;
     RECT  102.492 70.603 102.582 70.681 ;
     RECT  102.492 70.681 103.194 70.879 ;
     RECT  90.324 70.259 90.738 71.069 ;
     RECT  94.215 70.681 100.962 71.165 ;
     RECT  95.436 71.165 100.962 71.311 ;
     RECT  101.988 70.879 103.194 71.311 ;
     RECT  94.215 71.165 94.698 71.609 ;
     RECT  94.215 71.609 94.662 72.379 ;
     RECT  95.436 71.311 103.194 72.379 ;
     RECT  90.324 71.069 90.342 72.463 ;
     RECT  68.652 45.869 70.197 72.527 ;
     RECT  90.324 72.463 90.666 72.689 ;
     RECT  94.215 72.379 103.194 72.841 ;
     RECT  94.176 72.841 103.194 72.959 ;
     RECT  101.988 72.959 103.194 73.103 ;
     RECT  94.176 72.959 101.25 73.277 ;
     RECT  94.176 73.277 101.07 73.381 ;
     RECT  102.024 73.103 103.194 73.483 ;
     RECT  94.14 73.381 101.07 73.499 ;
     RECT  71.964 56.759 72.897 73.543 ;
     RECT  71.892 73.543 72.897 73.841 ;
     RECT  83.415 52.439 83.697 73.849 ;
     RECT  84.78 49.883 84.798 73.849 ;
     RECT  93.168 67.973 93.186 73.849 ;
     RECT  83.415 73.849 84.798 74.039 ;
     RECT  92.592 73.849 93.186 74.075 ;
     RECT  36.792 64.129 65.826 74.093 ;
     RECT  102.024 73.483 103.23 74.111 ;
     RECT  90.324 72.689 90.342 74.119 ;
     RECT  94.14 73.499 100.782 74.155 ;
     RECT  102.024 74.111 103.194 74.155 ;
     RECT  90.324 74.119 90.666 74.191 ;
     RECT  91.515 70.259 91.797 74.191 ;
     RECT  101.916 74.155 103.194 74.281 ;
     RECT  93.744 74.155 100.782 74.489 ;
     RECT  96.264 74.489 100.782 74.539 ;
     RECT  101.88 74.281 103.194 74.539 ;
     RECT  96.264 74.539 103.194 74.615 ;
     RECT  68.652 72.527 68.67 75.029 ;
     RECT  96.264 74.615 100.962 75.259 ;
     RECT  96.048 75.259 100.962 75.361 ;
     RECT  101.7 74.615 103.194 75.361 ;
     RECT  96.048 75.361 103.194 75.533 ;
     RECT  101.988 75.533 103.194 75.541 ;
     RECT  93.744 74.489 95.238 75.811 ;
     RECT  96.048 75.533 101.142 75.811 ;
     RECT  93.744 75.811 101.142 75.929 ;
     RECT  101.988 75.541 103.23 76.343 ;
     RECT  95.832 75.929 101.142 76.351 ;
     RECT  88.056 64.697 88.074 76.541 ;
     RECT  102.456 76.343 103.23 76.577 ;
     RECT  95.832 76.351 101.574 76.649 ;
     RECT  102.564 76.577 103.23 76.649 ;
     RECT  93.744 75.929 95.022 76.747 ;
     RECT  95.832 76.649 100.602 76.747 ;
     RECT  103.212 76.649 103.23 76.811 ;
     RECT  101.34 76.649 101.43 76.919 ;
     RECT  93.744 76.747 100.602 77.009 ;
     RECT  18.615 2.413 18.897 77.515 ;
     RECT  101.412 76.919 101.43 77.515 ;
     RECT  66.6 63.815 67.497 77.585 ;
     RECT  101.412 77.515 102.042 77.593 ;
     RECT  95.94 77.009 100.602 77.665 ;
     RECT  101.412 77.593 102.582 77.701 ;
     RECT  18.615 77.515 19.53 77.755 ;
     RECT  95.94 77.665 100.638 77.791 ;
     RECT  101.412 77.701 103.194 77.791 ;
     RECT  93.744 77.009 95.022 77.963 ;
     RECT  34.815 2.413 35.097 78.061 ;
     RECT  18.615 77.755 19.674 78.089 ;
     RECT  34.815 78.061 35.334 78.169 ;
     RECT  95.94 77.791 103.194 78.403 ;
     RECT  93.744 77.963 94.986 78.709 ;
     RECT  95.724 78.403 103.194 78.709 ;
     RECT  34.815 78.169 35.622 78.943 ;
     RECT  34.815 78.943 35.766 79.213 ;
     RECT  34.815 79.213 35.91 79.519 ;
     RECT  90.324 74.191 91.797 79.583 ;
     RECT  93.744 78.709 103.194 79.583 ;
     RECT  93.744 79.583 101.538 79.709 ;
     RECT  102.6 79.583 103.194 79.745 ;
     RECT  34.815 79.519 35.982 79.753 ;
     RECT  36.792 74.093 65.538 79.753 ;
     RECT  101.412 79.709 101.538 79.781 ;
     RECT  103.176 79.745 103.194 79.819 ;
     RECT  93.744 79.709 100.602 80.015 ;
     RECT  103.176 79.819 103.266 80.015 ;
     RECT  103.248 80.015 103.266 80.051 ;
     RECT  93.744 80.015 94.734 80.123 ;
     RECT  90.324 79.583 90.666 80.249 ;
     RECT  94.215 80.123 94.734 80.249 ;
     RECT  94.215 80.249 94.662 80.357 ;
     RECT  95.544 80.015 100.602 80.357 ;
     RECT  95.94 80.357 100.602 80.429 ;
     RECT  96.915 80.429 100.602 80.519 ;
     RECT  92.592 74.075 92.61 81.707 ;
     RECT  95.94 80.429 96.102 81.743 ;
     RECT  96.915 80.519 100.458 81.941 ;
     RECT  96.084 81.743 96.102 82.013 ;
     RECT  96.915 81.941 99.897 82.049 ;
     RECT  74.556 57.991 75.654 82.291 ;
     RECT  74.556 82.291 75.834 82.409 ;
     RECT  101.412 79.781 101.43 82.409 ;
     RECT  74.556 82.409 75.654 82.445 ;
     RECT  69.588 72.527 70.197 82.453 ;
     RECT  69.588 82.453 70.722 82.589 ;
     RECT  98.388 82.049 99.897 82.679 ;
     RECT  98.856 82.679 99.897 83.219 ;
     RECT  66.78 77.585 67.497 83.497 ;
     RECT  84.78 74.039 84.798 83.525 ;
     RECT  96.915 82.049 97.65 84.209 ;
     RECT  66.78 83.497 68.094 87.035 ;
     RECT  82.332 52.439 82.35 88.925 ;
     RECT  69.588 82.589 70.197 91.319 ;
     RECT  66.78 87.035 67.497 91.471 ;
     RECT  99 83.219 99.897 93.785 ;
     RECT  77.4 52.439 78.297 102.695 ;
     RECT  66.78 91.471 68.094 102.965 ;
     RECT  2.415 53.021 2.697 103.157 ;
     RECT  5.115 2.413 5.397 103.157 ;
     RECT  7.815 2.413 8.097 103.157 ;
     RECT  10.515 2.413 10.797 103.157 ;
     RECT  13.215 2.413 13.497 103.157 ;
     RECT  15.915 2.413 16.197 103.157 ;
     RECT  18.615 78.089 18.897 103.157 ;
     RECT  21.315 2.413 21.597 103.157 ;
     RECT  24.015 2.413 24.297 103.157 ;
     RECT  26.715 2.413 26.997 103.157 ;
     RECT  29.415 2.413 29.697 103.157 ;
     RECT  32.115 2.413 32.397 103.157 ;
     RECT  34.815 79.753 65.538 103.157 ;
     RECT  67.215 102.965 68.094 103.157 ;
     RECT  69.915 91.319 70.197 103.157 ;
     RECT  72.615 73.841 72.897 103.157 ;
     RECT  78.015 102.695 78.297 103.157 ;
     RECT  80.715 52.241 80.997 103.157 ;
     RECT  83.415 74.039 83.697 103.157 ;
     RECT  86.115 64.967 86.397 103.157 ;
     RECT  88.815 66.245 89.097 103.157 ;
     RECT  91.515 79.583 91.797 103.157 ;
     RECT  94.215 80.357 94.497 103.157 ;
     RECT  96.915 84.209 97.197 103.157 ;
     RECT  99.615 93.785 99.897 103.157 ;
     RECT  74.556 82.445 75.597 103.235 ;
     RECT  90.324 80.249 90.342 103.271 ;
     RECT  70.107 103.157 70.197 103.279 ;
     RECT  67.407 103.157 68.094 103.343 ;
     RECT  2.607 103.157 2.697 103.427 ;
     RECT  5.307 103.157 5.397 103.427 ;
     RECT  8.007 103.157 8.097 103.427 ;
     RECT  10.707 103.157 10.797 103.427 ;
     RECT  13.407 103.157 13.497 103.427 ;
     RECT  16.107 103.157 16.197 103.427 ;
     RECT  18.807 103.157 18.897 103.427 ;
     RECT  21.507 103.157 21.597 103.427 ;
     RECT  24.207 103.157 24.297 103.427 ;
     RECT  26.907 103.157 26.997 103.427 ;
     RECT  29.607 103.157 29.697 103.427 ;
     RECT  32.307 103.157 32.397 103.427 ;
     RECT  67.407 103.343 67.497 103.427 ;
     RECT  70.107 103.279 70.758 103.427 ;
     RECT  72.807 103.157 72.897 103.427 ;
     RECT  75.507 103.235 75.597 103.427 ;
     RECT  78.207 103.157 78.297 103.427 ;
     RECT  80.907 103.157 80.997 103.427 ;
     RECT  83.607 103.157 83.697 103.427 ;
     RECT  86.307 103.157 86.397 103.427 ;
     RECT  89.007 103.157 89.097 103.427 ;
     RECT  91.707 103.157 91.797 103.427 ;
     RECT  94.407 103.157 94.497 103.427 ;
     RECT  97.107 103.157 97.197 103.427 ;
     RECT  99.807 103.157 99.897 103.427 ;
     RECT  70.74 103.427 70.758 103.541 ;
     RECT  74.664 103.235 74.682 103.577 ;
     RECT  34.956 103.157 65.538 105.701 ;
     RECT  34.956 105.701 65.502 105.804 ;
    LAYER M4 ;
     RECT  0.06 52.752 0.227 52.872 ;
     RECT  0.227 52.752 2.293 52.776 ;
     RECT  0.181 49.776 2.408 49.8 ;
     RECT  2.293 52.752 2.408 53.016 ;
     RECT  2.408 2.148 2.512 103.152 ;
     RECT  2.512 2.418 2.6 103.152 ;
     RECT  2.6 2.418 2.704 103.422 ;
     RECT  2.704 49.776 5.108 49.8 ;
     RECT  2.704 52.992 5.108 53.016 ;
     RECT  5.108 2.148 5.212 103.152 ;
     RECT  5.212 2.418 5.3 103.152 ;
     RECT  5.3 2.418 5.404 103.422 ;
     RECT  5.404 49.776 7.808 49.8 ;
     RECT  5.404 52.992 7.808 53.016 ;
     RECT  7.808 2.148 7.912 103.152 ;
     RECT  7.912 2.418 8 103.152 ;
     RECT  8 2.418 8.104 103.422 ;
     RECT  8.104 49.776 10.508 49.8 ;
     RECT  8.104 52.992 10.508 53.016 ;
     RECT  10.508 2.148 10.612 103.152 ;
     RECT  10.612 2.418 10.7 103.152 ;
     RECT  10.7 2.418 10.804 103.422 ;
     RECT  10.804 49.776 13.208 49.8 ;
     RECT  10.804 52.992 13.208 53.016 ;
     RECT  13.208 2.148 13.312 103.152 ;
     RECT  13.312 2.418 13.4 103.152 ;
     RECT  13.4 2.418 13.504 103.422 ;
     RECT  13.504 49.776 15.908 49.8 ;
     RECT  13.504 52.992 15.908 53.016 ;
     RECT  15.908 2.148 16.012 103.152 ;
     RECT  16.012 2.418 16.1 103.152 ;
     RECT  16.1 2.418 16.204 103.422 ;
     RECT  16.204 49.776 18.608 49.8 ;
     RECT  16.204 52.992 18.608 53.016 ;
     RECT  18.608 2.148 18.712 103.152 ;
     RECT  18.712 2.418 18.8 103.152 ;
     RECT  18.8 2.418 18.904 103.422 ;
     RECT  18.904 77.52 19.585 77.784 ;
     RECT  18.904 52.992 19.715 53.016 ;
     RECT  19.585 77.76 19.715 77.784 ;
     RECT  18.904 49.776 21.308 49.8 ;
     RECT  18.904 56.496 21.308 56.52 ;
     RECT  18.904 102.432 21.308 102.456 ;
     RECT  21.308 2.148 21.412 103.152 ;
     RECT  21.412 2.418 21.5 103.152 ;
     RECT  21.5 2.418 21.604 103.422 ;
     RECT  21.604 49.776 24.008 49.8 ;
     RECT  21.604 56.496 24.008 56.52 ;
     RECT  21.604 102.432 24.008 102.456 ;
     RECT  24.008 2.148 24.112 103.152 ;
     RECT  24.112 2.418 24.2 103.152 ;
     RECT  24.2 2.418 24.304 103.422 ;
     RECT  24.304 49.776 26.708 49.8 ;
     RECT  24.304 56.496 26.708 56.52 ;
     RECT  24.304 102.432 26.708 102.456 ;
     RECT  26.708 2.148 26.812 103.152 ;
     RECT  26.812 2.418 26.9 103.152 ;
     RECT  26.9 2.418 27.004 103.422 ;
     RECT  27.004 49.776 29.408 49.8 ;
     RECT  27.004 56.496 29.408 56.52 ;
     RECT  27.004 102.432 29.408 102.456 ;
     RECT  29.408 2.148 29.512 103.152 ;
     RECT  29.512 2.418 29.6 103.152 ;
     RECT  29.6 2.418 29.704 103.422 ;
     RECT  29.704 49.776 32.108 49.8 ;
     RECT  29.704 56.496 32.108 56.52 ;
     RECT  29.704 102.432 32.108 102.456 ;
     RECT  32.108 2.148 32.212 103.152 ;
     RECT  32.212 2.418 32.3 103.152 ;
     RECT  32.3 2.418 32.404 103.422 ;
     RECT  32.404 49.776 34.808 49.8 ;
     RECT  32.404 56.496 34.808 56.52 ;
     RECT  32.404 102.432 34.808 102.456 ;
     RECT  34.808 2.148 34.912 103.152 ;
     RECT  34.912 2.418 35 103.152 ;
     RECT  35 2.418 35.104 103.422 ;
     RECT  35.104 49.776 37.508 49.8 ;
     RECT  35.104 56.496 37.508 56.52 ;
     RECT  35.104 102.432 37.508 102.456 ;
     RECT  37.508 2.148 37.612 103.152 ;
     RECT  37.612 2.418 37.7 103.152 ;
     RECT  37.7 2.418 37.804 103.422 ;
     RECT  37.804 49.776 40.208 49.8 ;
     RECT  37.804 56.496 40.208 56.52 ;
     RECT  40.208 2.148 40.312 103.152 ;
     RECT  40.312 2.418 40.4 103.152 ;
     RECT  40.4 2.418 40.504 103.422 ;
     RECT  40.504 49.776 42.908 49.8 ;
     RECT  42.757 51.744 42.908 52.488 ;
     RECT  40.504 56.496 42.908 56.52 ;
     RECT  42.908 2.148 43.012 103.152 ;
     RECT  43.012 2.418 43.1 103.152 ;
     RECT  43.1 2.418 43.204 103.422 ;
     RECT  43.204 102.96 43.301 102.984 ;
     RECT  43.204 100.896 44.173 100.92 ;
     RECT  44.269 78.672 44.417 78.696 ;
     RECT  43.204 23.088 45.608 23.112 ;
     RECT  43.204 49.776 45.608 49.8 ;
     RECT  45.025 52.032 45.608 52.056 ;
     RECT  43.204 56.496 45.608 56.52 ;
     RECT  45.608 2.148 45.712 103.152 ;
     RECT  45.712 2.418 45.8 103.152 ;
     RECT  45.8 2.418 45.904 103.422 ;
     RECT  45.904 64.896 46.649 64.968 ;
     RECT  45.904 51.888 46.685 52.056 ;
     RECT  46.649 64.896 46.757 64.92 ;
     RECT  45.904 22.992 46.793 23.112 ;
     RECT  46.685 51.888 46.793 51.912 ;
     RECT  46.789 103.728 46.981 103.752 ;
     RECT  45.904 78.24 47.041 78.456 ;
     RECT  46.885 63.264 47.069 63.288 ;
     RECT  47.041 78.24 47.152 78.696 ;
     RECT  47.152 78.24 47.153 78.744 ;
     RECT  46.981 103.68 47.173 103.752 ;
     RECT  47.173 103.68 47.189 104.28 ;
     RECT  47.069 63.216 47.228 63.288 ;
     RECT  47.189 104.256 47.297 104.28 ;
     RECT  47.153 78.624 47.333 78.744 ;
     RECT  46.892 105.648 47.365 105.672 ;
     RECT  47.365 104.832 47.477 105.672 ;
     RECT  47.833 64.944 47.916 64.968 ;
     RECT  47.916 64.896 47.989 64.968 ;
     RECT  47.653 103.2 48.005 103.224 ;
     RECT  47.228 63.216 48.085 63.864 ;
     RECT  47.989 64.896 48.085 65.544 ;
     RECT  48.085 63.216 48.193 65.544 ;
     RECT  46.793 23.088 48.308 23.112 ;
     RECT  45.904 49.776 48.308 49.8 ;
     RECT  46.933 53.568 48.308 53.592 ;
     RECT  45.904 56.496 48.308 56.52 ;
     RECT  47.797 61.44 48.308 61.464 ;
     RECT  48.193 62.496 48.308 65.544 ;
     RECT  47.461 67.776 48.308 67.8 ;
     RECT  47.333 78.624 48.308 78.648 ;
     RECT  48.013 82.608 48.308 82.632 ;
     RECT  47.557 98.592 48.308 98.616 ;
     RECT  48.005 102.576 48.308 103.224 ;
     RECT  48.308 2.148 48.412 103.224 ;
     RECT  48.412 2.418 48.5 103.224 ;
     RECT  48.5 2.418 48.604 103.422 ;
     RECT  48.604 58.704 48.773 58.728 ;
     RECT  48.604 101.472 48.803 102.024 ;
     RECT  48.803 102 48.917 102.024 ;
     RECT  47.477 105.456 48.941 105.672 ;
     RECT  48.604 63.6 48.953 66.12 ;
     RECT  48.941 104.88 48.997 105.672 ;
     RECT  48.953 63.6 49.025 63.624 ;
     RECT  48.604 55.824 49.033 56.52 ;
     RECT  48.953 64.752 49.097 66.12 ;
     RECT  48.604 68.352 49.349 68.376 ;
     RECT  48.604 79.2 49.349 80.184 ;
     RECT  48.997 104.88 49.565 105.72 ;
     RECT  49.097 64.752 49.601 65.976 ;
     RECT  49.033 56.496 49.741 56.52 ;
     RECT  49.669 75.264 49.765 75.288 ;
     RECT  49.565 104.88 50.003 104.904 ;
     RECT  49.861 84.912 50.053 84.936 ;
     RECT  49.601 65.136 50.245 65.976 ;
     RECT  48.604 67.2 50.245 67.272 ;
     RECT  48.604 41.712 50.281 41.736 ;
     RECT  49.349 79.2 50.281 79.224 ;
     RECT  50.053 84.816 50.341 84.936 ;
     RECT  50.353 82.272 50.425 82.296 ;
     RECT  50.425 82.272 50.437 82.632 ;
     RECT  49.741 56.496 50.461 57.432 ;
     RECT  50.245 58.704 50.461 58.728 ;
     RECT  50.437 82.176 50.569 82.632 ;
     RECT  49.765 75.264 50.581 75.816 ;
     RECT  50.461 56.496 50.713 58.728 ;
     RECT  50.245 65.136 50.713 67.272 ;
     RECT  50.713 64.656 50.725 67.272 ;
     RECT  50.245 98.592 50.725 98.616 ;
     RECT  50.317 104.256 50.725 104.28 ;
     RECT  50.773 80.784 50.821 80.808 ;
     RECT  50.725 104.064 50.821 104.28 ;
     RECT  50.821 104.016 50.825 104.28 ;
     RECT  50.773 105.6 50.869 105.624 ;
     RECT  50.825 104.016 50.969 104.232 ;
     RECT  50.969 104.016 51.001 104.04 ;
     RECT  48.604 23.088 51.008 23.112 ;
     RECT  50.281 41.712 51.008 42.552 ;
     RECT  48.604 49.776 51.008 49.8 ;
     RECT  50.713 56.208 51.008 58.728 ;
     RECT  50.725 64.368 51.008 67.272 ;
     RECT  50.581 74.304 51.008 75.816 ;
     RECT  50.869 77.376 51.008 77.4 ;
     RECT  50.281 78.672 51.008 79.224 ;
     RECT  50.821 80.352 51.008 80.808 ;
     RECT  50.569 82.08 51.008 82.632 ;
     RECT  50.341 84.816 51.008 84.984 ;
     RECT  50.713 89.472 51.008 89.496 ;
     RECT  50.149 95.136 51.008 95.16 ;
     RECT  50.725 98.592 51.008 99.192 ;
     RECT  50.492 101.472 51.008 101.496 ;
     RECT  51.001 103.728 51.008 104.04 ;
     RECT  51.008 2.148 51.112 104.04 ;
     RECT  51.112 2.418 51.155 104.04 ;
     RECT  50.869 105.6 51.251 105.672 ;
     RECT  51.155 2.418 51.304 103.8 ;
     RECT  51.304 64.656 51.365 64.68 ;
     RECT  51.304 80.352 51.365 80.952 ;
     RECT  51.304 103.152 51.401 103.8 ;
     RECT  51.401 103.152 51.473 103.752 ;
     RECT  51.304 96.912 51.539 96.936 ;
     RECT  51.473 103.152 51.653 103.176 ;
     RECT  51.251 105.648 51.788 105.672 ;
     RECT  51.304 76.368 51.841 76.392 ;
     RECT  51.304 77.376 51.869 77.544 ;
     RECT  51.365 80.928 51.869 80.952 ;
     RECT  51.788 105.648 51.875 105.768 ;
     RECT  51.304 65.952 51.941 65.976 ;
     RECT  51.304 82.464 51.941 84.36 ;
     RECT  51.304 56.496 52.265 58.248 ;
     RECT  52.265 57.936 52.337 58.248 ;
     RECT  51.941 83.76 52.337 84.36 ;
     RECT  52.337 83.808 52.445 84.36 ;
     RECT  51.941 82.464 52.453 82.632 ;
     RECT  51.869 77.52 52.517 77.544 ;
     RECT  51.304 88.896 52.517 88.92 ;
     RECT  51.875 105.648 52.645 105.672 ;
     RECT  52.453 81.6 52.661 82.632 ;
     RECT  52.645 104.832 52.693 105.672 ;
     RECT  52.445 84.336 52.697 84.36 ;
     RECT  52.693 78.672 52.765 78.696 ;
     RECT  52.693 66.144 52.837 66.168 ;
     RECT  52.837 66.144 52.933 66.696 ;
     RECT  52.693 104.736 53.021 105.672 ;
     RECT  53.029 104.256 53.129 104.28 ;
     RECT  52.933 65.76 53.317 66.696 ;
     RECT  53.221 67.776 53.38 67.8 ;
     RECT  53.38 67.728 53.557 67.8 ;
     RECT  53.233 103.056 53.605 103.08 ;
     RECT  53.021 105.456 53.665 105.672 ;
     RECT  51.304 23.088 53.708 23.112 ;
     RECT  51.304 41.712 53.708 42.552 ;
     RECT  51.304 49.008 53.708 49.8 ;
     RECT  52.789 53.568 53.708 53.592 ;
     RECT  52.265 56.496 53.708 56.52 ;
     RECT  52.337 58.224 53.708 58.248 ;
     RECT  51.304 59.808 53.708 59.832 ;
     RECT  53.317 65.52 53.708 66.696 ;
     RECT  53.557 67.728 53.708 68.424 ;
     RECT  53.125 70.08 53.708 70.104 ;
     RECT  51.304 74.304 53.708 74.328 ;
     RECT  52.621 76.512 53.708 76.536 ;
     RECT  52.765 78.672 53.708 78.792 ;
     RECT  52.661 81.6 53.708 82.488 ;
     RECT  53.557 90.336 53.708 90.84 ;
     RECT  53.557 98.448 53.708 98.952 ;
     RECT  52.549 102 53.708 102.024 ;
     RECT  53.605 103.056 53.708 103.656 ;
     RECT  53.708 2.148 53.812 103.656 ;
     RECT  53.665 105.456 53.813 105.768 ;
     RECT  53.812 2.418 54.004 103.656 ;
     RECT  54.004 65.76 54.029 68.376 ;
     RECT  54.029 66.576 54.131 68.376 ;
     RECT  54.004 90.336 54.131 90.84 ;
     RECT  54.004 98.064 54.131 98.952 ;
     RECT  54.131 98.064 54.209 98.856 ;
     RECT  54.004 102.576 54.209 103.656 ;
     RECT  54.004 81.936 54.227 82.776 ;
     RECT  54.131 90.432 54.227 90.744 ;
     RECT  54.209 98.064 54.275 98.76 ;
     RECT  54.209 102.576 54.275 103.56 ;
     RECT  54.227 81.936 54.317 82.68 ;
     RECT  54.275 98.064 54.317 98.568 ;
     RECT  54.004 59.808 54.389 59.832 ;
     RECT  54.004 52.992 54.497 53.592 ;
     RECT  54.497 53.568 54.605 53.592 ;
     RECT  54.317 98.064 54.659 98.088 ;
     RECT  54.004 56.496 54.713 58.248 ;
     RECT  54.004 69.504 54.713 71.256 ;
     RECT  54.004 22.992 54.749 23.112 ;
     RECT  54.004 41.616 54.749 42.552 ;
     RECT  54.131 66.72 54.793 68.376 ;
     RECT  53.813 105.456 54.812 105.72 ;
     RECT  54.004 46.752 54.821 46.776 ;
     RECT  54.713 56.496 54.857 57.192 ;
     RECT  54.004 78.672 54.857 78.792 ;
     RECT  54.004 74.304 54.893 74.76 ;
     RECT  54.857 78.768 54.893 78.792 ;
     RECT  54.317 81.936 54.893 81.96 ;
     RECT  54.812 104.88 54.899 105.72 ;
     RECT  54.713 58.224 54.929 58.248 ;
     RECT  54.899 105.696 55.109 105.72 ;
     RECT  54.793 66.816 55.141 68.376 ;
     RECT  54.713 70.032 55.181 71.256 ;
     RECT  55.177 62.736 55.289 62.76 ;
     RECT  55.141 66.816 55.289 68.952 ;
     RECT  54.004 49.776 55.321 49.8 ;
     RECT  55.321 49.008 55.405 49.8 ;
     RECT  55.181 70.08 55.429 71.256 ;
     RECT  55.249 53.808 55.897 53.832 ;
     RECT  55.429 70.08 55.909 71.832 ;
     RECT  54.004 72.912 55.909 72.936 ;
     RECT  54.749 23.088 56.408 23.112 ;
     RECT  54.749 41.712 56.408 42.552 ;
     RECT  55.405 49.776 56.408 49.8 ;
     RECT  55.681 52.176 56.408 52.2 ;
     RECT  55.897 53.808 56.408 54.648 ;
     RECT  54.857 56.496 56.408 56.52 ;
     RECT  55.289 66.816 56.408 68.328 ;
     RECT  55.909 70.08 56.408 72.936 ;
     RECT  54.893 74.304 56.408 74.328 ;
     RECT  54.004 76.512 56.408 76.536 ;
     RECT  56.197 78.096 56.408 78.12 ;
     RECT  54.275 102.576 56.408 102.6 ;
     RECT  55.964 104.88 56.485 104.904 ;
     RECT  56.408 2.148 56.512 103.152 ;
     RECT  56.512 2.418 56.581 103.152 ;
     RECT  56.485 104.88 56.677 105.288 ;
     RECT  56.581 2.418 56.704 103.56 ;
     RECT  56.677 104.88 56.773 105.624 ;
     RECT  56.704 78.096 56.801 79.272 ;
     RECT  56.773 104.88 56.833 105.72 ;
     RECT  56.704 72.432 56.837 76.92 ;
     RECT  56.704 103.536 56.837 103.56 ;
     RECT  56.833 104.544 56.869 105.72 ;
     RECT  56.869 104.256 56.905 105.72 ;
     RECT  56.905 104.256 56.981 105.768 ;
     RECT  56.704 53.136 57.053 54.648 ;
     RECT  56.837 72.912 57.197 76.92 ;
     RECT  56.704 80.352 57.269 80.376 ;
     RECT  56.704 49.776 57.449 50.76 ;
     RECT  57.197 73.488 57.557 76.92 ;
     RECT  57.053 53.136 57.593 53.928 ;
     RECT  57.557 73.488 57.593 76.536 ;
     RECT  56.704 44.064 57.665 45.624 ;
     RECT  57.593 53.136 57.665 53.832 ;
     RECT  57.593 75.744 57.773 76.536 ;
     RECT  57.692 102.048 57.779 102.072 ;
     RECT  56.801 78.48 57.829 79.272 ;
     RECT  57.665 44.064 57.845 44.952 ;
     RECT  57.925 83.184 58.025 83.208 ;
     RECT  57.593 73.488 58.061 74.76 ;
     RECT  58.117 100.848 58.309 100.872 ;
     RECT  58.373 82.56 58.405 82.584 ;
     RECT  57.449 49.776 58.597 49.8 ;
     RECT  58.405 82.464 58.693 82.584 ;
     RECT  57.665 53.136 58.705 53.352 ;
     RECT  58.705 53.04 58.777 53.352 ;
     RECT  57.773 76.464 58.789 76.536 ;
     RECT  57.845 44.064 58.813 44.712 ;
     RECT  58.453 70.08 58.837 70.104 ;
     RECT  58.837 69.456 58.844 70.104 ;
     RECT  58.597 49.488 59.065 49.8 ;
     RECT  56.704 23.088 59.108 23.112 ;
     RECT  56.704 41.712 59.108 42.552 ;
     RECT  58.813 44.064 59.108 45.576 ;
     RECT  59.065 49.488 59.108 50.04 ;
     RECT  57.877 51.744 59.108 51.768 ;
     RECT  58.777 53.04 59.108 53.592 ;
     RECT  58.957 54.672 59.108 54.696 ;
     RECT  56.704 56.496 59.108 56.52 ;
     RECT  58.844 69.456 59.108 70.728 ;
     RECT  58.933 71.712 59.108 71.736 ;
     RECT  58.061 74.016 59.108 74.76 ;
     RECT  58.789 75.792 59.108 76.536 ;
     RECT  57.829 78.48 59.108 79.752 ;
     RECT  58.693 81.984 59.108 82.584 ;
     RECT  58.645 86.016 59.108 86.04 ;
     RECT  58.309 100.848 59.108 101.448 ;
     RECT  58.921 102.624 59.108 102.648 ;
     RECT  59.108 2.148 59.212 103.152 ;
     RECT  59.212 2.418 59.3 103.152 ;
     RECT  59.3 2.418 59.404 103.422 ;
     RECT  59.404 75.792 59.465 76.536 ;
     RECT  59.404 81.984 59.465 82.008 ;
     RECT  59.404 51.744 59.537 53.352 ;
     RECT  59.404 78.576 59.609 78.696 ;
     RECT  59.404 72.384 59.825 72.408 ;
     RECT  59.609 78.576 59.825 78.6 ;
     RECT  56.981 104.544 59.845 105.768 ;
     RECT  59.404 67.824 59.933 67.848 ;
     RECT  59.404 44.064 59.939 45.576 ;
     RECT  59.404 101.424 60.221 101.448 ;
     RECT  59.845 104.256 60.437 105.768 ;
     RECT  59.537 52.176 60.473 53.352 ;
     RECT  59.939 44.688 60.515 45.576 ;
     RECT  60.437 105.6 60.515 105.768 ;
     RECT  59.465 76.512 60.517 76.536 ;
     RECT  60.437 104.256 60.545 104.28 ;
     RECT  59.404 50.016 60.577 50.04 ;
     RECT  60.515 44.688 60.611 44.712 ;
     RECT  59.404 74.064 60.613 74.328 ;
     RECT  60.473 52.512 60.617 53.352 ;
     RECT  59.404 68.88 60.689 70.776 ;
     RECT  60.709 72.336 60.805 72.36 ;
     RECT  60.613 73.488 60.805 74.328 ;
     RECT  60.617 53.328 60.829 53.352 ;
     RECT  60.689 68.88 60.833 68.904 ;
     RECT  60.689 69.888 61.093 70.776 ;
     RECT  60.577 49.776 61.189 50.04 ;
     RECT  60.937 51.168 61.189 51.192 ;
     RECT  61.093 69.888 61.189 71.16 ;
     RECT  60.805 72.336 61.189 74.328 ;
     RECT  61.244 103.728 61.331 103.752 ;
     RECT  61.189 49.776 61.525 51.192 ;
     RECT  61.513 100.944 61.525 101.112 ;
     RECT  60.515 105.648 61.573 105.768 ;
     RECT  61.525 100.752 61.58 101.112 ;
     RECT  59.404 59.808 61.669 59.832 ;
     RECT  61.525 103.584 61.693 103.608 ;
     RECT  61.484 94.656 61.729 94.68 ;
     RECT  61.573 105.12 61.769 105.768 ;
     RECT  60.661 21.456 61.808 21.48 ;
     RECT  59.404 23.088 61.808 23.112 ;
     RECT  59.404 41.712 61.808 42.552 ;
     RECT  61.525 49.488 61.808 51.192 ;
     RECT  60.829 53.328 61.808 54.072 ;
     RECT  59.404 56.496 61.808 56.52 ;
     RECT  61.669 59.232 61.808 59.832 ;
     RECT  61.621 66.72 61.808 66.744 ;
     RECT  61.573 67.776 61.808 67.8 ;
     RECT  61.189 69.888 61.808 74.328 ;
     RECT  60.517 76.512 61.808 77.496 ;
     RECT  61.429 78.576 61.808 78.888 ;
     RECT  61.657 86.64 61.808 86.664 ;
     RECT  61.729 94.608 61.808 94.68 ;
     RECT  61.729 96.912 61.808 96.936 ;
     RECT  61.525 98.64 61.808 98.664 ;
     RECT  61.58 100.752 61.808 102.072 ;
     RECT  61.693 103.536 61.808 103.608 ;
     RECT  61.769 105.12 61.811 105.72 ;
     RECT  61.808 2.148 61.912 103.608 ;
     RECT  61.912 2.418 62.104 103.608 ;
     RECT  62.104 70.656 62.165 72.264 ;
     RECT  61.811 105.6 62.209 105.72 ;
     RECT  62.104 74.064 62.243 74.328 ;
     RECT  62.104 97.008 62.243 97.032 ;
     RECT  62.104 66.72 62.309 66.888 ;
     RECT  62.209 105.6 62.339 105.672 ;
     RECT  62.104 51.936 62.345 55.224 ;
     RECT  62.165 71.136 62.345 72.264 ;
     RECT  62.104 102.576 62.525 102.6 ;
     RECT  62.104 49.008 62.561 50.952 ;
     RECT  62.345 71.28 62.597 72.264 ;
     RECT  62.309 66.72 62.633 66.744 ;
     RECT  62.104 61.44 62.669 62.712 ;
     RECT  62.104 76.512 62.705 76.92 ;
     RECT  62.104 22.992 62.741 23.112 ;
     RECT  62.104 45.744 62.741 45.864 ;
     RECT  62.104 58.704 62.741 59.256 ;
     RECT  62.104 41.616 62.777 42.552 ;
     RECT  62.104 64.896 62.849 64.968 ;
     RECT  62.345 54.624 62.921 55.224 ;
     RECT  62.917 104.832 63.013 104.904 ;
     RECT  62.849 64.944 63.029 64.968 ;
     RECT  63.013 104.784 63.209 104.904 ;
     RECT  62.104 60.432 63.281 60.456 ;
     RECT  62.597 71.28 63.281 71.496 ;
     RECT  62.821 103.728 63.377 103.752 ;
     RECT  62.561 50.832 63.385 50.952 ;
     RECT  62.345 51.936 63.385 53.352 ;
     RECT  62.921 54.624 63.385 54.648 ;
     RECT  63.385 50.832 63.461 54.648 ;
     RECT  63.377 103.152 63.461 103.752 ;
     RECT  63.461 103.2 63.493 103.752 ;
     RECT  63.461 50.832 63.497 51.912 ;
     RECT  62.669 61.44 63.773 62.136 ;
     RECT  63.493 103.2 63.821 104.28 ;
     RECT  63.773 60.864 63.877 62.136 ;
     RECT  63.709 105.6 63.925 105.72 ;
     RECT  63.821 103.2 64.307 103.8 ;
     RECT  63.877 60.864 64.316 63.096 ;
     RECT  62.104 21.456 64.508 21.48 ;
     RECT  62.741 23.088 64.508 23.112 ;
     RECT  64.021 26.064 64.508 26.088 ;
     RECT  62.777 41.712 64.508 42.552 ;
     RECT  62.741 45.744 64.508 45.768 ;
     RECT  62.561 49.008 64.508 49.8 ;
     RECT  63.497 51.072 64.508 51.912 ;
     RECT  63.461 53.328 64.508 53.688 ;
     RECT  62.104 56.496 64.508 56.52 ;
     RECT  62.741 58.704 64.508 58.728 ;
     RECT  64.316 60.864 64.508 63.288 ;
     RECT  64.465 66.672 64.508 66.696 ;
     RECT  63.281 71.472 64.508 71.496 ;
     RECT  62.243 74.304 64.508 74.328 ;
     RECT  62.705 76.512 64.508 76.536 ;
     RECT  64.307 103.2 64.508 103.752 ;
     RECT  63.925 105.6 64.549 105.768 ;
     RECT  64.508 2.148 64.612 103.752 ;
     RECT  64.549 105.456 64.789 105.768 ;
     RECT  64.612 2.418 64.804 103.752 ;
     RECT  64.804 48.672 64.865 49.8 ;
     RECT  64.789 104.832 64.937 105.768 ;
     RECT  64.804 58.704 64.973 59.016 ;
     RECT  64.804 61.008 64.973 63.096 ;
     RECT  64.804 52.032 65.045 54.888 ;
     RECT  64.804 78.528 65.075 78.648 ;
     RECT  64.804 86.592 65.075 86.616 ;
     RECT  64.804 94.656 65.075 94.68 ;
     RECT  64.804 98.736 65.075 98.856 ;
     RECT  64.804 103.536 65.075 103.752 ;
     RECT  64.804 90.576 65.081 90.696 ;
     RECT  65.075 98.736 65.081 98.76 ;
     RECT  65.075 103.728 65.081 103.752 ;
     RECT  65.075 78.624 65.116 78.648 ;
     RECT  64.804 102.48 65.189 102.504 ;
     RECT  64.937 104.832 65.225 105.72 ;
     RECT  64.804 66.576 65.297 66.696 ;
     RECT  65.297 66.672 65.369 66.696 ;
     RECT  64.973 63.072 65.441 63.096 ;
     RECT  64.973 58.704 65.477 58.728 ;
     RECT  64.973 61.008 65.5 61.944 ;
     RECT  64.865 48.672 65.603 48.696 ;
     RECT  65.225 105.696 65.603 105.72 ;
     RECT  65.045 52.032 65.693 54.12 ;
     RECT  65.5 61.92 65.765 61.944 ;
     RECT  64.804 74.064 65.837 74.328 ;
     RECT  64.865 49.776 65.905 49.8 ;
     RECT  64.804 50.832 65.905 50.856 ;
     RECT  65.905 49.776 65.981 50.856 ;
     RECT  65.981 49.776 66.017 50.76 ;
     RECT  65.693 53.136 66.053 54.072 ;
     RECT  64.804 21.456 67.208 21.48 ;
     RECT  64.804 23.088 67.208 23.928 ;
     RECT  64.804 26.064 67.208 26.088 ;
     RECT  64.804 41.712 67.208 42.552 ;
     RECT  64.804 45.744 67.208 45.768 ;
     RECT  66.017 49.776 67.208 49.8 ;
     RECT  65.693 52.032 67.208 52.056 ;
     RECT  66.053 53.136 67.208 53.352 ;
     RECT  64.804 56.496 67.208 56.52 ;
     RECT  66.517 58.704 67.208 58.728 ;
     RECT  65.837 74.304 67.208 74.328 ;
     RECT  64.804 76.512 67.208 76.536 ;
     RECT  67.208 2.148 67.312 103.152 ;
     RECT  67.312 2.418 67.4 103.152 ;
     RECT  67.4 2.418 67.504 103.422 ;
     RECT  67.504 21.456 69.908 21.48 ;
     RECT  67.504 23.088 69.908 23.928 ;
     RECT  67.504 26.064 69.908 26.088 ;
     RECT  67.504 41.712 69.908 42.552 ;
     RECT  67.504 45.744 69.908 45.768 ;
     RECT  67.504 49.776 69.908 49.8 ;
     RECT  67.504 53.328 69.908 53.352 ;
     RECT  67.504 56.496 69.908 56.52 ;
     RECT  67.504 74.304 69.908 74.328 ;
     RECT  67.504 76.512 69.908 76.536 ;
     RECT  69.908 2.148 70.012 103.152 ;
     RECT  70.012 2.418 70.1 103.152 ;
     RECT  70.1 2.418 70.204 103.422 ;
     RECT  70.204 22.992 70.733 23.928 ;
     RECT  70.204 25.968 70.733 26.088 ;
     RECT  70.204 41.616 70.733 42.552 ;
     RECT  70.204 45.744 70.733 45.864 ;
     RECT  70.204 49.776 71.845 49.8 ;
     RECT  70.204 56.496 71.845 56.52 ;
     RECT  70.204 74.304 71.917 74.328 ;
     RECT  70.733 45.744 72.037 45.768 ;
     RECT  70.204 21.456 72.608 21.48 ;
     RECT  70.733 23.088 72.608 23.928 ;
     RECT  70.733 26.064 72.608 26.088 ;
     RECT  70.733 41.712 72.608 42.552 ;
     RECT  72.037 44.976 72.608 45.768 ;
     RECT  71.845 49.584 72.608 49.8 ;
     RECT  70.204 53.328 72.608 53.352 ;
     RECT  71.845 56.448 72.608 56.52 ;
     RECT  71.917 73.776 72.608 74.328 ;
     RECT  70.204 76.512 72.608 76.536 ;
     RECT  72.608 2.148 72.712 103.152 ;
     RECT  72.712 2.418 72.8 103.152 ;
     RECT  72.8 2.418 72.904 103.422 ;
     RECT  72.904 44.976 73.001 45.768 ;
     RECT  73.001 45.744 74.509 45.768 ;
     RECT  72.904 21.456 75.308 21.48 ;
     RECT  72.904 23.088 75.308 23.928 ;
     RECT  72.904 26.064 75.308 26.088 ;
     RECT  72.904 41.712 75.308 42.552 ;
     RECT  74.509 44.88 75.308 45.768 ;
     RECT  72.904 53.328 75.308 53.352 ;
     RECT  72.904 56.496 75.308 56.52 ;
     RECT  72.904 74.304 75.308 74.328 ;
     RECT  72.904 76.512 75.308 76.536 ;
     RECT  75.308 2.148 75.412 103.152 ;
     RECT  75.412 2.418 75.5 103.152 ;
     RECT  75.5 2.418 75.604 103.422 ;
     RECT  75.604 21.456 78.008 21.48 ;
     RECT  75.604 23.088 78.008 23.928 ;
     RECT  75.604 26.064 78.008 26.088 ;
     RECT  75.604 41.712 78.008 42.552 ;
     RECT  75.604 44.88 78.008 45.768 ;
     RECT  75.604 53.328 78.008 53.352 ;
     RECT  75.604 56.496 78.008 56.52 ;
     RECT  75.604 74.304 78.008 74.328 ;
     RECT  75.604 76.512 78.008 76.536 ;
     RECT  78.008 2.148 78.112 103.152 ;
     RECT  78.112 2.418 78.2 103.152 ;
     RECT  78.2 2.418 78.304 103.422 ;
     RECT  78.304 41.376 78.581 42.552 ;
     RECT  78.304 22.992 78.689 23.928 ;
     RECT  78.304 25.968 78.689 26.088 ;
     RECT  78.581 41.616 78.689 42.552 ;
     RECT  78.304 44.88 78.689 45.864 ;
     RECT  78.304 21.456 80.708 21.48 ;
     RECT  78.689 23.088 80.708 23.928 ;
     RECT  78.689 26.064 80.708 26.088 ;
     RECT  78.689 41.712 80.708 42.552 ;
     RECT  78.689 44.88 80.708 45.768 ;
     RECT  78.304 53.328 80.708 53.352 ;
     RECT  78.304 56.496 80.708 56.52 ;
     RECT  78.304 74.304 80.708 74.328 ;
     RECT  78.304 76.512 80.708 76.536 ;
     RECT  80.708 2.148 80.812 103.152 ;
     RECT  80.812 2.418 80.9 103.152 ;
     RECT  80.9 2.418 81.004 103.422 ;
     RECT  81.004 21.456 83.408 21.48 ;
     RECT  81.004 23.088 83.408 23.928 ;
     RECT  81.004 26.064 83.408 26.088 ;
     RECT  81.004 41.712 83.408 42.552 ;
     RECT  81.004 44.88 83.408 45.768 ;
     RECT  81.004 53.328 83.408 53.352 ;
     RECT  81.004 56.496 83.408 56.52 ;
     RECT  81.004 74.304 83.408 74.328 ;
     RECT  81.004 76.512 83.408 76.536 ;
     RECT  83.408 2.148 83.512 103.152 ;
     RECT  83.512 2.418 83.6 103.152 ;
     RECT  83.6 2.418 83.704 103.422 ;
     RECT  83.704 26.064 84.737 26.088 ;
     RECT  83.704 21.456 86.108 21.48 ;
     RECT  83.704 23.088 86.108 23.928 ;
     RECT  83.704 41.712 86.108 42.552 ;
     RECT  83.704 44.88 86.108 45.768 ;
     RECT  83.704 53.328 86.108 53.352 ;
     RECT  83.704 56.496 86.108 56.52 ;
     RECT  83.704 74.304 86.108 74.328 ;
     RECT  83.704 76.512 86.108 76.536 ;
     RECT  86.108 2.148 86.212 103.152 ;
     RECT  86.212 2.418 86.3 103.152 ;
     RECT  86.3 2.418 86.404 103.422 ;
     RECT  86.404 41.616 86.501 42.552 ;
     RECT  86.501 41.616 86.681 42.456 ;
     RECT  86.404 44.88 86.681 45.864 ;
     RECT  86.404 21.456 88.808 21.48 ;
     RECT  86.404 22.992 88.808 23.928 ;
     RECT  86.681 41.712 88.808 42.456 ;
     RECT  86.681 44.88 88.808 45.768 ;
     RECT  86.404 53.328 88.808 53.352 ;
     RECT  86.404 56.496 88.808 56.52 ;
     RECT  86.404 74.304 88.808 74.328 ;
     RECT  86.404 76.512 88.808 76.536 ;
     RECT  88.808 2.148 88.912 103.152 ;
     RECT  88.912 2.418 89 103.152 ;
     RECT  89 2.418 89.104 103.422 ;
     RECT  89.104 30.336 89.489 30.36 ;
     RECT  89.104 21.456 91.508 21.48 ;
     RECT  89.104 22.992 91.508 23.928 ;
     RECT  89.104 41.712 91.508 42.456 ;
     RECT  89.104 44.88 91.508 45.768 ;
     RECT  90.673 50.064 91.508 50.088 ;
     RECT  89.104 53.328 91.508 53.352 ;
     RECT  89.104 56.496 91.508 56.52 ;
     RECT  90.637 70.128 91.508 70.152 ;
     RECT  89.104 74.304 91.508 74.328 ;
     RECT  89.104 76.512 91.508 76.536 ;
     RECT  91.508 2.148 91.612 103.152 ;
     RECT  91.612 2.418 91.7 103.152 ;
     RECT  91.7 2.418 91.804 103.422 ;
     RECT  91.804 56.496 92.921 56.52 ;
     RECT  92.921 56.448 93.089 56.52 ;
     RECT  91.804 21.456 93.949 21.48 ;
     RECT  93.949 21.456 94.208 22.056 ;
     RECT  91.804 23.088 94.208 23.928 ;
     RECT  91.804 41.712 94.208 42.312 ;
     RECT  91.804 44.88 94.208 45.768 ;
     RECT  91.804 53.328 94.208 53.352 ;
     RECT  93.089 56.496 94.208 56.52 ;
     RECT  91.804 74.304 94.208 74.328 ;
     RECT  91.804 76.512 94.208 76.536 ;
     RECT  94.208 2.148 94.312 103.152 ;
     RECT  94.312 2.418 94.4 103.152 ;
     RECT  94.4 2.418 94.504 103.422 ;
     RECT  94.504 35.856 94.753 37.848 ;
     RECT  94.504 74.064 94.787 79.512 ;
     RECT  94.504 32.928 94.925 34.488 ;
     RECT  94.504 70.56 94.925 72.936 ;
     RECT  94.787 76.512 94.997 79.512 ;
     RECT  94.504 23.568 95.171 25.56 ;
     RECT  94.504 58.656 95.177 58.776 ;
     RECT  94.504 41.616 95.213 49.896 ;
     RECT  94.925 71.808 95.465 72.936 ;
     RECT  94.504 39.84 95.641 39.864 ;
     RECT  95.213 41.616 95.641 49.752 ;
     RECT  95.641 39.84 95.645 49.752 ;
     RECT  94.925 70.56 95.677 70.632 ;
     RECT  95.171 23.568 95.749 23.928 ;
     RECT  94.504 50.88 95.753 57.576 ;
     RECT  94.504 66.672 95.753 68.664 ;
     RECT  95.465 72.912 95.753 72.936 ;
     RECT  94.504 26.736 95.789 31.944 ;
     RECT  94.753 36.48 95.821 37.848 ;
     RECT  95.789 26.736 95.825 26.76 ;
     RECT  94.504 60.432 95.857 61.896 ;
     RECT  94.504 62.976 95.857 64.92 ;
     RECT  95.749 23.328 95.861 23.928 ;
     RECT  95.645 45.552 95.861 49.752 ;
     RECT  95.821 36.432 95.893 37.848 ;
     RECT  94.925 32.928 95.897 34.056 ;
     RECT  95.753 66.672 95.897 68.568 ;
     RECT  95.645 39.84 95.933 44.472 ;
     RECT  94.504 21.456 96.037 22.2 ;
     RECT  95.893 36.432 96.037 38.712 ;
     RECT  95.897 66.672 96.037 68.136 ;
     RECT  96.037 20.688 96.073 22.2 ;
     RECT  95.861 23.328 96.073 23.832 ;
     RECT  95.857 60.432 96.073 64.92 ;
     RECT  96.037 36.432 96.181 38.808 ;
     RECT  95.933 39.84 96.181 40.104 ;
     RECT  94.787 74.064 96.217 75.288 ;
     RECT  95.677 70.224 96.253 70.632 ;
     RECT  94.997 76.512 96.325 76.92 ;
     RECT  96.037 66.576 96.361 68.136 ;
     RECT  96.073 60.384 96.433 64.92 ;
     RECT  95.789 27.744 96.541 31.944 ;
     RECT  95.897 32.928 96.541 33.384 ;
     RECT  96.361 66.528 96.541 68.136 ;
     RECT  95.177 58.656 96.721 58.68 ;
     RECT  96.433 59.712 96.721 64.92 ;
     RECT  96.253 70.128 96.829 70.632 ;
     RECT  95.465 71.808 96.829 71.832 ;
     RECT  94.997 78.72 96.865 79.512 ;
     RECT  95.171 25.2 96.901 25.56 ;
     RECT  96.505 26.592 96.901 26.616 ;
     RECT  96.217 73.536 96.901 75.288 ;
     RECT  96.325 76.464 96.901 76.92 ;
     RECT  96.073 20.688 96.908 23.832 ;
     RECT  96.901 25.2 96.908 26.616 ;
     RECT  96.541 27.744 96.908 33.384 ;
     RECT  96.073 35.28 96.908 35.304 ;
     RECT  96.181 36.432 96.908 40.104 ;
     RECT  95.933 41.136 96.908 44.472 ;
     RECT  95.861 45.648 96.908 49.752 ;
     RECT  95.753 50.88 96.908 54.36 ;
     RECT  95.753 55.44 96.908 57.576 ;
     RECT  96.721 58.656 96.908 64.92 ;
     RECT  96.541 66.336 96.908 68.136 ;
     RECT  96.829 70.128 96.908 71.832 ;
     RECT  96.901 73.536 96.908 76.92 ;
     RECT  96.865 77.952 96.908 79.512 ;
     RECT  96.908 2.148 97.012 103.152 ;
     RECT  97.012 2.418 97.1 103.152 ;
     RECT  97.1 2.418 97.204 103.422 ;
     RECT  97.204 40.992 97.229 76.536 ;
     RECT  97.229 40.992 97.337 70.728 ;
     RECT  97.229 72 97.409 76.536 ;
     RECT  97.204 38.208 97.553 38.664 ;
     RECT  97.409 72 97.619 74.664 ;
     RECT  97.204 77.952 97.633 79.848 ;
     RECT  97.337 40.992 97.697 70.584 ;
     RECT  97.697 40.992 97.885 58.152 ;
     RECT  97.885 40.992 98.021 53.592 ;
     RECT  97.633 77.952 98.165 79.512 ;
     RECT  97.204 20.688 98.201 25.512 ;
     RECT  97.885 54.576 98.237 58.152 ;
     RECT  97.204 26.496 98.305 35.304 ;
     RECT  97.204 36.288 98.305 37.128 ;
     RECT  97.409 75.696 98.305 76.536 ;
     RECT  97.697 60.864 98.413 70.584 ;
     RECT  98.413 60.864 98.485 70.68 ;
     RECT  98.201 20.688 98.489 24.552 ;
     RECT  98.305 26.496 98.521 37.128 ;
     RECT  98.165 78.096 98.525 79.512 ;
     RECT  97.553 38.256 98.561 38.664 ;
     RECT  98.237 56.256 98.561 58.152 ;
     RECT  98.521 26.304 98.593 37.128 ;
     RECT  98.561 38.256 98.593 38.328 ;
     RECT  98.593 26.304 98.599 38.328 ;
     RECT  98.485 60.864 98.627 70.872 ;
     RECT  97.619 72.336 98.665 74.664 ;
     RECT  97.204 39.936 98.737 39.96 ;
     RECT  98.305 75.696 98.845 76.584 ;
     RECT  98.021 41.616 99.025 53.592 ;
     RECT  98.237 54.576 99.025 55.272 ;
     RECT  98.845 75.696 99.061 76.728 ;
     RECT  98.627 65.472 99.097 70.872 ;
     RECT  98.525 78.096 99.133 79.464 ;
     RECT  98.489 21.36 99.241 24.552 ;
     RECT  99.061 75.696 99.253 76.776 ;
     RECT  99.133 77.904 99.253 79.464 ;
     RECT  98.737 39.888 99.277 39.96 ;
     RECT  98.599 26.304 99.313 38.28 ;
     RECT  99.277 39.312 99.349 39.96 ;
     RECT  99.349 39.312 99.421 40.632 ;
     RECT  99.025 41.616 99.421 55.272 ;
     RECT  97.697 59.28 99.493 59.784 ;
     RECT  98.627 60.864 99.493 64.296 ;
     RECT  99.565 20.304 99.608 20.328 ;
     RECT  99.241 21.36 99.608 25.224 ;
     RECT  99.313 26.256 99.608 38.28 ;
     RECT  99.421 39.312 99.608 55.272 ;
     RECT  98.561 56.256 99.608 57.816 ;
     RECT  99.493 59.28 99.608 64.296 ;
     RECT  99.097 65.472 99.608 70.968 ;
     RECT  98.665 72.336 99.608 74.712 ;
     RECT  99.253 75.696 99.608 79.464 ;
     RECT  99.608 2.148 99.712 103.152 ;
     RECT  99.712 2.418 99.8 103.152 ;
     RECT  99.8 2.418 99.904 103.422 ;
     RECT  99.904 36 100.019 43.656 ;
     RECT  99.904 59.04 100.019 63.288 ;
     RECT  99.904 65.52 100.037 68.952 ;
     RECT  100.019 36 100.067 38.184 ;
     RECT  100.019 40.032 100.073 43.656 ;
     RECT  100.067 36 100.108 37.608 ;
     RECT  99.904 45.744 100.109 56.328 ;
     RECT  100.109 45.744 100.217 49.608 ;
     RECT  99.904 77.904 100.289 79.176 ;
     RECT  99.904 57.408 100.325 57.624 ;
     RECT  100.289 78.096 100.325 79.176 ;
     RECT  100.217 45.744 100.361 48.696 ;
     RECT  100.109 50.928 100.361 56.328 ;
     RECT  100.037 65.52 100.433 66.072 ;
     RECT  100.361 46.224 100.505 48.696 ;
     RECT  99.904 76.752 100.505 76.776 ;
     RECT  100.325 78.384 100.505 79.176 ;
     RECT  100.505 78.48 100.541 79.176 ;
     RECT  100.361 51.12 100.577 56.328 ;
     RECT  100.325 57.408 100.649 57.432 ;
     RECT  100.541 78.576 100.865 79.176 ;
     RECT  99.904 29.472 100.897 30.072 ;
     RECT  99.904 31.104 100.897 31.752 ;
     RECT  99.904 33.264 100.897 34.92 ;
     RECT  100.108 36 100.897 37.512 ;
     RECT  100.019 60.048 100.897 63.288 ;
     RECT  99.904 64.368 100.897 64.392 ;
     RECT  100.433 65.52 100.897 66.024 ;
     RECT  100.037 67.056 100.897 68.952 ;
     RECT  99.904 69.984 100.897 70.536 ;
     RECT  100.897 33.264 100.937 37.512 ;
     RECT  99.904 25.2 101.009 28.248 ;
     RECT  99.904 20.016 101.117 24.072 ;
     RECT  100.073 40.848 101.333 43.656 ;
     RECT  101.009 26.352 101.437 28.248 ;
     RECT  100.897 29.472 101.437 31.752 ;
     RECT  100.897 45.168 101.437 45.192 ;
     RECT  100.505 46.224 101.437 48.648 ;
     RECT  101.437 26.352 101.473 31.752 ;
     RECT  100.937 33.264 101.473 35.976 ;
     RECT  101.333 42.48 101.473 43.656 ;
     RECT  100.577 51.12 101.473 51.336 ;
     RECT  100.897 79.632 101.473 79.656 ;
     RECT  101.117 20.4 101.617 24.072 ;
     RECT  101.581 39.12 101.617 39.144 ;
     RECT  100.577 52.464 101.617 56.328 ;
     RECT  101.437 57.456 101.617 57.48 ;
     RECT  100.897 60.048 101.617 66.024 ;
     RECT  100.897 67.056 101.617 70.536 ;
     RECT  100.937 37.104 101.905 37.512 ;
     RECT  101.473 49.968 101.905 51.336 ;
     RECT  101.617 52.464 101.905 57.48 ;
     RECT  99.904 71.616 101.905 73.272 ;
     RECT  99.904 74.544 101.905 75.432 ;
     RECT  100.897 58.992 101.977 59.016 ;
     RECT  101.617 60.048 101.977 70.536 ;
     RECT  101.905 71.616 101.977 75.432 ;
     RECT  101.041 76.608 101.977 76.68 ;
     RECT  100.865 78.576 101.977 78.648 ;
     RECT  101.473 79.632 101.977 79.752 ;
     RECT  101.617 20.4 102.013 24.168 ;
     RECT  101.009 25.2 102.013 25.32 ;
     RECT  101.473 26.352 102.013 35.976 ;
     RECT  101.905 37.104 102.013 38.088 ;
     RECT  101.617 39.12 102.013 39.528 ;
     RECT  101.333 40.848 102.013 41.352 ;
     RECT  101.473 42.48 102.013 44.04 ;
     RECT  101.437 45.168 102.013 48.648 ;
     RECT  101.905 49.968 102.013 57.48 ;
     RECT  101.977 58.992 102.013 76.68 ;
     RECT  102.013 39.12 102.481 41.352 ;
     RECT  102.013 42.48 102.481 77.544 ;
     RECT  102.481 39.12 102.553 77.544 ;
     RECT  101.977 78.576 102.553 79.752 ;
     RECT  102.013 20.4 102.589 38.088 ;
     RECT  102.589 20.208 103.129 38.088 ;
     RECT  103.129 20.112 103.165 38.088 ;
     RECT  102.553 39.12 103.165 79.752 ;
     RECT  103.165 19.92 103.237 79.752 ;
     RECT  103.237 19.92 104.028 79.848 ;
     RECT  104.028 29.472 104.069 29.496 ;
    LAYER M5 ;
     RECT  2.4 2.137 2.52 2.151 ;
     RECT  5.1 2.137 5.22 2.151 ;
     RECT  7.8 2.137 7.92 2.151 ;
     RECT  10.5 2.137 10.62 2.151 ;
     RECT  13.2 2.137 13.32 2.151 ;
     RECT  15.9 2.137 16.02 2.151 ;
     RECT  18.6 2.137 18.72 2.151 ;
     RECT  21.3 2.137 21.42 2.151 ;
     RECT  24 2.137 24.12 2.151 ;
     RECT  26.7 2.137 26.82 2.151 ;
     RECT  29.4 2.137 29.52 2.151 ;
     RECT  32.1 2.137 32.22 2.151 ;
     RECT  34.8 2.137 34.92 2.151 ;
     RECT  37.5 2.137 37.62 2.151 ;
     RECT  40.2 2.137 40.32 2.151 ;
     RECT  42.9 2.137 43.02 2.151 ;
     RECT  45.6 2.137 45.72 2.151 ;
     RECT  48.3 2.137 48.42 2.151 ;
     RECT  51 2.137 51.12 2.151 ;
     RECT  53.7 2.137 53.82 2.151 ;
     RECT  56.4 2.137 56.52 2.151 ;
     RECT  59.1 2.137 59.22 2.151 ;
     RECT  61.8 2.137 61.92 2.151 ;
     RECT  64.5 2.137 64.62 2.151 ;
     RECT  67.2 2.137 67.32 2.151 ;
     RECT  69.9 2.137 70.02 2.151 ;
     RECT  72.6 2.137 72.72 2.151 ;
     RECT  75.3 2.137 75.42 2.151 ;
     RECT  78 2.137 78.12 2.151 ;
     RECT  80.7 2.137 80.82 2.151 ;
     RECT  83.4 2.137 83.52 2.151 ;
     RECT  86.1 2.137 86.22 2.151 ;
     RECT  88.8 2.137 88.92 2.151 ;
     RECT  91.5 2.137 91.62 2.151 ;
     RECT  94.2 2.137 94.32 2.151 ;
     RECT  96.9 2.137 97.02 2.151 ;
     RECT  99.6 2.137 99.72 2.151 ;
     RECT  96.9 2.151 97.212 21.637 ;
     RECT  42.9 2.151 43.212 23.077 ;
     RECT  94.2 2.151 94.512 23.893 ;
     RECT  94.2 23.893 95.16 24.563 ;
     RECT  64.5 2.151 64.812 26.053 ;
     RECT  94.2 24.563 94.512 26.725 ;
     RECT  99.6 2.151 99.912 27.061 ;
     RECT  99.504 27.061 99.912 27.875 ;
     RECT  94.2 26.725 95.016 28.451 ;
     RECT  96.9 21.637 98.136 28.693 ;
     RECT  96.768 28.693 98.136 28.739 ;
     RECT  94.2 28.451 94.512 29.653 ;
     RECT  99.6 27.875 99.912 30.661 ;
     RECT  102.624 30.661 102.648 30.947 ;
     RECT  103.92 30.757 103.944 30.947 ;
     RECT  99.504 30.661 99.912 32.771 ;
     RECT  94.2 29.653 95.16 33.011 ;
     RECT  94.2 33.011 94.824 34.067 ;
     RECT  94.2 34.067 94.512 35.845 ;
     RECT  99.6 32.771 99.912 37.573 ;
     RECT  94.2 35.845 94.728 37.859 ;
     RECT  99.6 37.573 100.056 38.195 ;
     RECT  96.768 28.739 97.212 38.677 ;
     RECT  99.6 38.195 100.008 39.347 ;
     RECT  95.904 38.677 97.212 39.875 ;
     RECT  99.6 39.347 99.912 40.021 ;
     RECT  99.504 40.021 99.912 40.595 ;
     RECT  94.2 37.859 94.512 41.941 ;
     RECT  96.336 39.875 97.212 41.941 ;
     RECT  94.2 41.941 97.212 41.987 ;
     RECT  59.1 2.151 59.412 44.053 ;
     RECT  60.672 21.445 60.696 44.053 ;
     RECT  56.4 2.151 56.712 44.917 ;
     RECT  72.6 2.151 72.912 44.965 ;
     RECT  94.2 41.987 95.448 46.741 ;
     RECT  94.2 46.741 95.592 46.787 ;
     RECT  64.032 26.053 64.812 48.661 ;
     RECT  51 2.151 51.312 48.997 ;
     RECT  61.8 2.151 62.112 48.997 ;
     RECT  64.032 48.661 65.592 48.997 ;
     RECT  59.1 44.053 60.696 49.477 ;
     RECT  61.8 48.997 65.592 49.477 ;
     RECT  72.048 44.965 72.912 49.573 ;
     RECT  94.2 46.787 94.512 51.109 ;
     RECT  95.568 46.787 95.592 51.109 ;
     RECT  94.2 51.109 95.592 51.347 ;
     RECT  42.9 23.077 44.136 51.733 ;
     RECT  56.4 44.917 57.528 51.733 ;
     RECT  58.608 49.477 65.592 51.733 ;
     RECT  99.6 40.595 99.912 52.213 ;
     RECT  96.9 41.987 97.212 52.261 ;
     RECT  99.6 52.213 100.008 52.405 ;
     RECT  42.768 51.733 44.136 52.499 ;
     RECT  0.192 49.765 0.216 52.883 ;
     RECT  18.6 2.151 18.912 52.981 ;
     RECT  53.7 2.151 54.012 52.981 ;
     RECT  55.344 48.997 55.368 52.981 ;
     RECT  99.168 52.405 100.008 53.075 ;
     RECT  51 48.997 51.864 53.557 ;
     RECT  53.7 52.981 55.368 53.557 ;
     RECT  94.2 51.347 95.448 54.035 ;
     RECT  96.9 52.261 97.8 54.085 ;
     RECT  48.3 2.151 48.612 55.813 ;
     RECT  96.9 54.085 97.848 56.293 ;
     RECT  71.856 49.573 72.912 56.483 ;
     RECT  94.2 54.035 94.512 56.821 ;
     RECT  96.336 56.293 97.848 57.059 ;
     RECT  96.9 57.059 97.848 58.117 ;
     RECT  94.2 56.821 94.776 58.787 ;
     RECT  99.6 53.075 99.912 59.029 ;
     RECT  99.6 59.029 100.008 59.507 ;
     RECT  46.944 53.557 46.968 61.429 ;
     RECT  48.3 55.813 48.984 61.429 ;
     RECT  96.9 58.117 98.088 62.629 ;
     RECT  96.9 62.629 98.52 62.675 ;
     RECT  46.944 61.429 48.984 63.253 ;
     RECT  95.664 62.965 95.688 63.539 ;
     RECT  98.496 62.675 98.52 64.309 ;
     RECT  51 53.557 55.368 64.357 ;
     RECT  98.448 64.309 98.616 64.643 ;
     RECT  45.6 2.151 45.912 64.885 ;
     RECT  46.896 63.253 48.984 64.885 ;
     RECT  45.6 64.885 48.984 65.029 ;
     RECT  45.6 65.029 49.128 65.125 ;
     RECT  98.448 64.643 98.472 66.179 ;
     RECT  95.76 66.661 95.784 66.803 ;
     RECT  50.736 64.357 55.368 67.717 ;
     RECT  56.4 51.733 65.592 67.717 ;
     RECT  96.9 62.675 97.212 68.917 ;
     RECT  98.496 66.661 98.52 68.917 ;
     RECT  96.9 68.917 98.52 69.491 ;
     RECT  96.9 69.491 98.136 69.779 ;
     RECT  94.2 58.787 94.512 71.125 ;
     RECT  94.2 71.125 94.872 72.323 ;
     RECT  50.736 67.717 65.592 74.293 ;
     RECT  94.2 72.323 94.512 75.013 ;
     RECT  45.6 65.125 49.608 75.253 ;
     RECT  50.592 74.293 65.592 75.253 ;
     RECT  94.2 75.013 94.776 75.971 ;
     RECT  99.6 59.507 99.912 76.741 ;
     RECT  94.2 75.971 94.512 77.461 ;
     RECT  99.264 76.741 99.912 77.555 ;
     RECT  94.2 77.461 94.776 78.371 ;
     RECT  96.9 69.779 97.608 79.859 ;
     RECT  42.9 52.499 44.136 100.931 ;
     RECT  18.6 52.981 19.704 102.467 ;
     RECT  2.4 2.151 2.712 103.419 ;
     RECT  5.1 2.151 5.412 103.419 ;
     RECT  7.8 2.151 8.112 103.419 ;
     RECT  10.5 2.151 10.812 103.419 ;
     RECT  13.2 2.151 13.512 103.419 ;
     RECT  15.9 2.151 16.212 103.419 ;
     RECT  18.6 102.467 18.912 103.419 ;
     RECT  21.3 2.151 21.612 103.419 ;
     RECT  24 2.151 24.312 103.419 ;
     RECT  26.7 2.151 27.012 103.419 ;
     RECT  29.4 2.151 29.712 103.419 ;
     RECT  32.1 2.151 32.412 103.419 ;
     RECT  34.8 2.151 35.112 103.419 ;
     RECT  37.5 2.151 37.812 103.419 ;
     RECT  40.2 2.151 40.512 103.419 ;
     RECT  42.9 100.931 43.212 103.419 ;
     RECT  45.6 75.253 65.592 103.419 ;
     RECT  67.2 2.151 67.512 103.419 ;
     RECT  69.9 2.151 70.212 103.419 ;
     RECT  72.6 56.483 72.912 103.419 ;
     RECT  75.3 2.151 75.612 103.419 ;
     RECT  78 2.151 78.312 103.419 ;
     RECT  80.7 2.151 81.012 103.419 ;
     RECT  83.4 2.151 83.712 103.419 ;
     RECT  86.1 2.151 86.412 103.419 ;
     RECT  88.8 2.151 89.112 103.419 ;
     RECT  91.5 2.151 91.812 103.419 ;
     RECT  94.2 78.371 94.512 103.419 ;
     RECT  96.9 79.859 97.212 103.419 ;
     RECT  99.6 77.555 99.912 103.419 ;
     RECT  2.592 103.419 2.712 103.433 ;
     RECT  5.292 103.419 5.412 103.433 ;
     RECT  7.992 103.419 8.112 103.433 ;
     RECT  10.692 103.419 10.812 103.433 ;
     RECT  13.392 103.419 13.512 103.433 ;
     RECT  16.092 103.419 16.212 103.433 ;
     RECT  18.792 103.419 18.912 103.433 ;
     RECT  21.492 103.419 21.612 103.433 ;
     RECT  24.192 103.419 24.312 103.433 ;
     RECT  26.892 103.419 27.012 103.433 ;
     RECT  29.592 103.419 29.712 103.433 ;
     RECT  32.292 103.419 32.412 103.433 ;
     RECT  34.992 103.419 35.112 103.433 ;
     RECT  37.692 103.419 37.812 103.433 ;
     RECT  40.392 103.419 40.512 103.433 ;
     RECT  43.092 103.419 43.212 103.433 ;
     RECT  45.792 103.419 65.592 103.433 ;
     RECT  67.392 103.419 67.512 103.433 ;
     RECT  70.092 103.419 70.212 103.433 ;
     RECT  72.792 103.419 72.912 103.433 ;
     RECT  75.492 103.419 75.612 103.433 ;
     RECT  78.192 103.419 78.312 103.433 ;
     RECT  80.892 103.419 81.012 103.433 ;
     RECT  83.592 103.419 83.712 103.433 ;
     RECT  86.292 103.419 86.412 103.433 ;
     RECT  88.992 103.419 89.112 103.433 ;
     RECT  91.692 103.419 91.812 103.433 ;
     RECT  94.392 103.419 94.512 103.433 ;
     RECT  97.092 103.419 97.212 103.433 ;
     RECT  99.792 103.419 99.912 103.433 ;
     RECT  46.608 103.433 65.592 105.731 ;
     RECT  46.608 105.731 64.968 105.744 ;
     RECT  51.84 105.744 51.864 105.779 ;
     RECT  60.576 105.744 60.6 105.779 ;
  END
END qfd_rlyh_600_EN_104x106
END LIBRARY
